VERSION 5.8 ;
BUSBITCHARS "[]" ;
DIVIDERCHAR "/" ;
UNITS
    DATABASE MICRONS 1000 ;
END UNITS

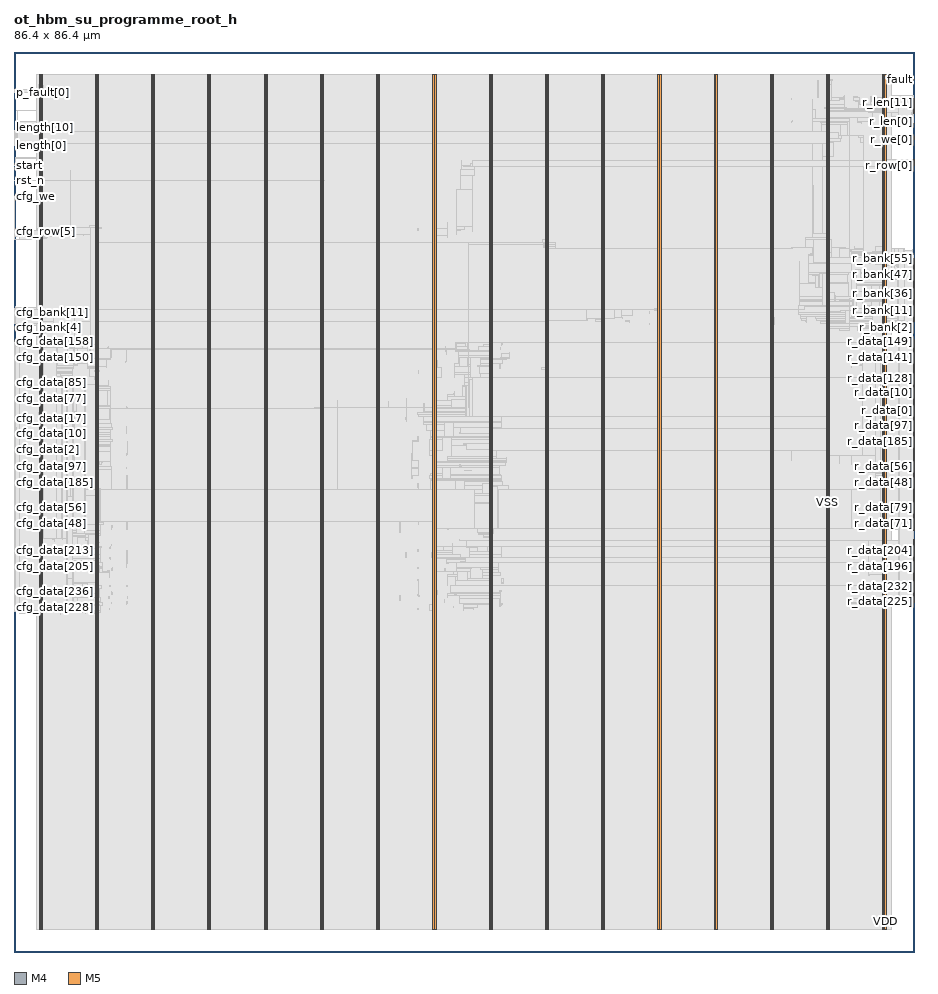
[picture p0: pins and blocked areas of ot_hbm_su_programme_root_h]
MACRO ot_hbm_su_programme_root_h
  FOREIGN ot_hbm_su_programme_root_h 0 0 ;
  CLASS BLOCK ;
  SIZE 86.4 BY 86.4 ;
  PIN cfg_bank[0]
    DIRECTION INPUT ;
    USE SIGNAL ;
    PORT
      LAYER M4 ;
        RECT  0 60.336 0.084 60.36 ;
    END
  END cfg_bank[0]
  PIN cfg_bank[10]
    DIRECTION INPUT ;
    USE SIGNAL ;
    PORT
      LAYER M4 ;
        RECT  0 61.296 0.084 61.32 ;
    END
  END cfg_bank[10]
  PIN cfg_bank[11]
    DIRECTION INPUT ;
    USE SIGNAL ;
    PORT
      LAYER M4 ;
        RECT  0 61.392 0.084 61.416 ;
    END
  END cfg_bank[11]
  PIN cfg_bank[12]
    DIRECTION INPUT ;
    USE SIGNAL ;
    PORT
      LAYER M4 ;
        RECT  0 61.488 0.084 61.512 ;
    END
  END cfg_bank[12]
  PIN cfg_bank[13]
    DIRECTION INPUT ;
    USE SIGNAL ;
    PORT
      LAYER M4 ;
        RECT  0 61.584 0.084 61.608 ;
    END
  END cfg_bank[13]
  PIN cfg_bank[14]
    DIRECTION INPUT ;
    USE SIGNAL ;
    PORT
      LAYER M4 ;
        RECT  0 61.68 0.084 61.704 ;
    END
  END cfg_bank[14]
  PIN cfg_bank[15]
    DIRECTION INPUT ;
    USE SIGNAL ;
    PORT
      LAYER M4 ;
        RECT  0 61.776 0.084 61.8 ;
    END
  END cfg_bank[15]
  PIN cfg_bank[1]
    DIRECTION INPUT ;
    USE SIGNAL ;
    PORT
      LAYER M4 ;
        RECT  0 60.432 0.084 60.456 ;
    END
  END cfg_bank[1]
  PIN cfg_bank[2]
    DIRECTION INPUT ;
    USE SIGNAL ;
    PORT
      LAYER M4 ;
        RECT  0 60.528 0.084 60.552 ;
    END
  END cfg_bank[2]
  PIN cfg_bank[3]
    DIRECTION INPUT ;
    USE SIGNAL ;
    PORT
      LAYER M4 ;
        RECT  0 60.624 0.084 60.648 ;
    END
  END cfg_bank[3]
  PIN cfg_bank[4]
    DIRECTION INPUT ;
    USE SIGNAL ;
    PORT
      LAYER M4 ;
        RECT  0 60.72 0.084 60.744 ;
    END
  END cfg_bank[4]
  PIN cfg_bank[5]
    DIRECTION INPUT ;
    USE SIGNAL ;
    PORT
      LAYER M4 ;
        RECT  0 60.816 0.084 60.84 ;
    END
  END cfg_bank[5]
  PIN cfg_bank[6]
    DIRECTION INPUT ;
    USE SIGNAL ;
    PORT
      LAYER M4 ;
        RECT  0 60.912 0.084 60.936 ;
    END
  END cfg_bank[6]
  PIN cfg_bank[7]
    DIRECTION INPUT ;
    USE SIGNAL ;
    PORT
      LAYER M4 ;
        RECT  0 61.008 0.084 61.032 ;
    END
  END cfg_bank[7]
  PIN cfg_bank[8]
    DIRECTION INPUT ;
    USE SIGNAL ;
    PORT
      LAYER M4 ;
        RECT  0 61.104 0.084 61.128 ;
    END
  END cfg_bank[8]
  PIN cfg_bank[9]
    DIRECTION INPUT ;
    USE SIGNAL ;
    PORT
      LAYER M4 ;
        RECT  0 61.2 0.084 61.224 ;
    END
  END cfg_bank[9]
  PIN cfg_data[0]
    DIRECTION INPUT ;
    USE SIGNAL ;
    PORT
      LAYER M4 ;
        RECT  0 48.816 0.084 48.84 ;
    END
  END cfg_data[0]
  PIN cfg_data[100]
    DIRECTION INPUT ;
    USE SIGNAL ;
    PORT
      LAYER M4 ;
        RECT  0 46.128 0.084 46.152 ;
    END
  END cfg_data[100]
  PIN cfg_data[101]
    DIRECTION INPUT ;
    USE SIGNAL ;
    PORT
      LAYER M4 ;
        RECT  0 46.224 0.084 46.248 ;
    END
  END cfg_data[101]
  PIN cfg_data[102]
    DIRECTION INPUT ;
    USE SIGNAL ;
    PORT
      LAYER M4 ;
        RECT  0 46.32 0.084 46.344 ;
    END
  END cfg_data[102]
  PIN cfg_data[103]
    DIRECTION INPUT ;
    USE SIGNAL ;
    PORT
      LAYER M4 ;
        RECT  0 46.416 0.084 46.44 ;
    END
  END cfg_data[103]
  PIN cfg_data[104]
    DIRECTION INPUT ;
    USE SIGNAL ;
    PORT
      LAYER M4 ;
        RECT  0 46.512 0.084 46.536 ;
    END
  END cfg_data[104]
  PIN cfg_data[105]
    DIRECTION INPUT ;
    USE SIGNAL ;
    PORT
      LAYER M4 ;
        RECT  0 46.608 0.084 46.632 ;
    END
  END cfg_data[105]
  PIN cfg_data[106]
    DIRECTION INPUT ;
    USE SIGNAL ;
    PORT
      LAYER M4 ;
        RECT  0 46.704 0.084 46.728 ;
    END
  END cfg_data[106]
  PIN cfg_data[107]
    DIRECTION INPUT ;
    USE SIGNAL ;
    PORT
      LAYER M4 ;
        RECT  0 46.8 0.084 46.824 ;
    END
  END cfg_data[107]
  PIN cfg_data[108]
    DIRECTION INPUT ;
    USE SIGNAL ;
    PORT
      LAYER M4 ;
        RECT  0 46.896 0.084 46.92 ;
    END
  END cfg_data[108]
  PIN cfg_data[109]
    DIRECTION INPUT ;
    USE SIGNAL ;
    PORT
      LAYER M4 ;
        RECT  0 46.992 0.084 47.016 ;
    END
  END cfg_data[109]
  PIN cfg_data[10]
    DIRECTION INPUT ;
    USE SIGNAL ;
    PORT
      LAYER M4 ;
        RECT  0 49.776 0.084 49.8 ;
    END
  END cfg_data[10]
  PIN cfg_data[110]
    DIRECTION INPUT ;
    USE SIGNAL ;
    PORT
      LAYER M4 ;
        RECT  0 47.088 0.084 47.112 ;
    END
  END cfg_data[110]
  PIN cfg_data[111]
    DIRECTION INPUT ;
    USE SIGNAL ;
    PORT
      LAYER M4 ;
        RECT  0 47.184 0.084 47.208 ;
    END
  END cfg_data[111]
  PIN cfg_data[112]
    DIRECTION INPUT ;
    USE SIGNAL ;
    PORT
      LAYER M4 ;
        RECT  0 47.28 0.084 47.304 ;
    END
  END cfg_data[112]
  PIN cfg_data[113]
    DIRECTION INPUT ;
    USE SIGNAL ;
    PORT
      LAYER M4 ;
        RECT  0 47.376 0.084 47.4 ;
    END
  END cfg_data[113]
  PIN cfg_data[114]
    DIRECTION INPUT ;
    USE SIGNAL ;
    PORT
      LAYER M4 ;
        RECT  0 47.472 0.084 47.496 ;
    END
  END cfg_data[114]
  PIN cfg_data[115]
    DIRECTION INPUT ;
    USE SIGNAL ;
    PORT
      LAYER M4 ;
        RECT  0 47.568 0.084 47.592 ;
    END
  END cfg_data[115]
  PIN cfg_data[116]
    DIRECTION INPUT ;
    USE SIGNAL ;
    PORT
      LAYER M4 ;
        RECT  0 47.664 0.084 47.688 ;
    END
  END cfg_data[116]
  PIN cfg_data[117]
    DIRECTION INPUT ;
    USE SIGNAL ;
    PORT
      LAYER M4 ;
        RECT  0 47.76 0.084 47.784 ;
    END
  END cfg_data[117]
  PIN cfg_data[118]
    DIRECTION INPUT ;
    USE SIGNAL ;
    PORT
      LAYER M4 ;
        RECT  0 47.856 0.084 47.88 ;
    END
  END cfg_data[118]
  PIN cfg_data[119]
    DIRECTION INPUT ;
    USE SIGNAL ;
    PORT
      LAYER M4 ;
        RECT  0 47.952 0.084 47.976 ;
    END
  END cfg_data[119]
  PIN cfg_data[11]
    DIRECTION INPUT ;
    USE SIGNAL ;
    PORT
      LAYER M4 ;
        RECT  0 49.872 0.084 49.896 ;
    END
  END cfg_data[11]
  PIN cfg_data[120]
    DIRECTION INPUT ;
    USE SIGNAL ;
    PORT
      LAYER M4 ;
        RECT  0 48.048 0.084 48.072 ;
    END
  END cfg_data[120]
  PIN cfg_data[121]
    DIRECTION INPUT ;
    USE SIGNAL ;
    PORT
      LAYER M4 ;
        RECT  0 48.144 0.084 48.168 ;
    END
  END cfg_data[121]
  PIN cfg_data[122]
    DIRECTION INPUT ;
    USE SIGNAL ;
    PORT
      LAYER M4 ;
        RECT  0 48.24 0.084 48.264 ;
    END
  END cfg_data[122]
  PIN cfg_data[123]
    DIRECTION INPUT ;
    USE SIGNAL ;
    PORT
      LAYER M4 ;
        RECT  0 48.336 0.084 48.36 ;
    END
  END cfg_data[123]
  PIN cfg_data[124]
    DIRECTION INPUT ;
    USE SIGNAL ;
    PORT
      LAYER M4 ;
        RECT  0 48.432 0.084 48.456 ;
    END
  END cfg_data[124]
  PIN cfg_data[125]
    DIRECTION INPUT ;
    USE SIGNAL ;
    PORT
      LAYER M4 ;
        RECT  0 48.528 0.084 48.552 ;
    END
  END cfg_data[125]
  PIN cfg_data[126]
    DIRECTION INPUT ;
    USE SIGNAL ;
    PORT
      LAYER M4 ;
        RECT  0 48.624 0.084 48.648 ;
    END
  END cfg_data[126]
  PIN cfg_data[127]
    DIRECTION INPUT ;
    USE SIGNAL ;
    PORT
      LAYER M4 ;
        RECT  0 48.72 0.084 48.744 ;
    END
  END cfg_data[127]
  PIN cfg_data[128]
    DIRECTION INPUT ;
    USE SIGNAL ;
    PORT
      LAYER M4 ;
        RECT  0 54.96 0.084 54.984 ;
    END
  END cfg_data[128]
  PIN cfg_data[129]
    DIRECTION INPUT ;
    USE SIGNAL ;
    PORT
      LAYER M4 ;
        RECT  0 55.056 0.084 55.08 ;
    END
  END cfg_data[129]
  PIN cfg_data[12]
    DIRECTION INPUT ;
    USE SIGNAL ;
    PORT
      LAYER M4 ;
        RECT  0 49.968 0.084 49.992 ;
    END
  END cfg_data[12]
  PIN cfg_data[130]
    DIRECTION INPUT ;
    USE SIGNAL ;
    PORT
      LAYER M4 ;
        RECT  0 55.152 0.084 55.176 ;
    END
  END cfg_data[130]
  PIN cfg_data[131]
    DIRECTION INPUT ;
    USE SIGNAL ;
    PORT
      LAYER M4 ;
        RECT  0 55.248 0.084 55.272 ;
    END
  END cfg_data[131]
  PIN cfg_data[132]
    DIRECTION INPUT ;
    USE SIGNAL ;
    PORT
      LAYER M4 ;
        RECT  0 55.344 0.084 55.368 ;
    END
  END cfg_data[132]
  PIN cfg_data[133]
    DIRECTION INPUT ;
    USE SIGNAL ;
    PORT
      LAYER M4 ;
        RECT  0 55.44 0.084 55.464 ;
    END
  END cfg_data[133]
  PIN cfg_data[134]
    DIRECTION INPUT ;
    USE SIGNAL ;
    PORT
      LAYER M4 ;
        RECT  0 55.536 0.084 55.56 ;
    END
  END cfg_data[134]
  PIN cfg_data[135]
    DIRECTION INPUT ;
    USE SIGNAL ;
    PORT
      LAYER M4 ;
        RECT  0 55.632 0.084 55.656 ;
    END
  END cfg_data[135]
  PIN cfg_data[136]
    DIRECTION INPUT ;
    USE SIGNAL ;
    PORT
      LAYER M4 ;
        RECT  0 55.728 0.084 55.752 ;
    END
  END cfg_data[136]
  PIN cfg_data[137]
    DIRECTION INPUT ;
    USE SIGNAL ;
    PORT
      LAYER M4 ;
        RECT  0 55.824 0.084 55.848 ;
    END
  END cfg_data[137]
  PIN cfg_data[138]
    DIRECTION INPUT ;
    USE SIGNAL ;
    PORT
      LAYER M4 ;
        RECT  0 55.92 0.084 55.944 ;
    END
  END cfg_data[138]
  PIN cfg_data[139]
    DIRECTION INPUT ;
    USE SIGNAL ;
    PORT
      LAYER M4 ;
        RECT  0 56.016 0.084 56.04 ;
    END
  END cfg_data[139]
  PIN cfg_data[13]
    DIRECTION INPUT ;
    USE SIGNAL ;
    PORT
      LAYER M4 ;
        RECT  0 50.064 0.084 50.088 ;
    END
  END cfg_data[13]
  PIN cfg_data[140]
    DIRECTION INPUT ;
    USE SIGNAL ;
    PORT
      LAYER M4 ;
        RECT  0 56.112 0.084 56.136 ;
    END
  END cfg_data[140]
  PIN cfg_data[141]
    DIRECTION INPUT ;
    USE SIGNAL ;
    PORT
      LAYER M4 ;
        RECT  0 56.208 0.084 56.232 ;
    END
  END cfg_data[141]
  PIN cfg_data[142]
    DIRECTION INPUT ;
    USE SIGNAL ;
    PORT
      LAYER M4 ;
        RECT  0 56.304 0.084 56.328 ;
    END
  END cfg_data[142]
  PIN cfg_data[143]
    DIRECTION INPUT ;
    USE SIGNAL ;
    PORT
      LAYER M4 ;
        RECT  0 56.4 0.084 56.424 ;
    END
  END cfg_data[143]
  PIN cfg_data[144]
    DIRECTION INPUT ;
    USE SIGNAL ;
    PORT
      LAYER M4 ;
        RECT  0 56.496 0.084 56.52 ;
    END
  END cfg_data[144]
  PIN cfg_data[145]
    DIRECTION INPUT ;
    USE SIGNAL ;
    PORT
      LAYER M4 ;
        RECT  0 56.592 0.084 56.616 ;
    END
  END cfg_data[145]
  PIN cfg_data[146]
    DIRECTION INPUT ;
    USE SIGNAL ;
    PORT
      LAYER M4 ;
        RECT  0 56.688 0.084 56.712 ;
    END
  END cfg_data[146]
  PIN cfg_data[147]
    DIRECTION INPUT ;
    USE SIGNAL ;
    PORT
      LAYER M4 ;
        RECT  0 56.784 0.084 56.808 ;
    END
  END cfg_data[147]
  PIN cfg_data[148]
    DIRECTION INPUT ;
    USE SIGNAL ;
    PORT
      LAYER M4 ;
        RECT  0 56.88 0.084 56.904 ;
    END
  END cfg_data[148]
  PIN cfg_data[149]
    DIRECTION INPUT ;
    USE SIGNAL ;
    PORT
      LAYER M4 ;
        RECT  0 56.976 0.084 57 ;
    END
  END cfg_data[149]
  PIN cfg_data[14]
    DIRECTION INPUT ;
    USE SIGNAL ;
    PORT
      LAYER M4 ;
        RECT  0 50.16 0.084 50.184 ;
    END
  END cfg_data[14]
  PIN cfg_data[150]
    DIRECTION INPUT ;
    USE SIGNAL ;
    PORT
      LAYER M4 ;
        RECT  0 57.072 0.084 57.096 ;
    END
  END cfg_data[150]
  PIN cfg_data[151]
    DIRECTION INPUT ;
    USE SIGNAL ;
    PORT
      LAYER M4 ;
        RECT  0 57.168 0.084 57.192 ;
    END
  END cfg_data[151]
  PIN cfg_data[152]
    DIRECTION INPUT ;
    USE SIGNAL ;
    PORT
      LAYER M4 ;
        RECT  0 57.264 0.084 57.288 ;
    END
  END cfg_data[152]
  PIN cfg_data[153]
    DIRECTION INPUT ;
    USE SIGNAL ;
    PORT
      LAYER M4 ;
        RECT  0 57.36 0.084 57.384 ;
    END
  END cfg_data[153]
  PIN cfg_data[154]
    DIRECTION INPUT ;
    USE SIGNAL ;
    PORT
      LAYER M4 ;
        RECT  0 57.456 0.084 57.48 ;
    END
  END cfg_data[154]
  PIN cfg_data[155]
    DIRECTION INPUT ;
    USE SIGNAL ;
    PORT
      LAYER M4 ;
        RECT  0 57.552 0.084 57.576 ;
    END
  END cfg_data[155]
  PIN cfg_data[156]
    DIRECTION INPUT ;
    USE SIGNAL ;
    PORT
      LAYER M4 ;
        RECT  0 57.648 0.084 57.672 ;
    END
  END cfg_data[156]
  PIN cfg_data[157]
    DIRECTION INPUT ;
    USE SIGNAL ;
    PORT
      LAYER M4 ;
        RECT  0 57.744 0.084 57.768 ;
    END
  END cfg_data[157]
  PIN cfg_data[158]
    DIRECTION INPUT ;
    USE SIGNAL ;
    PORT
      LAYER M4 ;
        RECT  0 57.84 0.084 57.864 ;
    END
  END cfg_data[158]
  PIN cfg_data[159]
    DIRECTION INPUT ;
    USE SIGNAL ;
    PORT
      LAYER M4 ;
        RECT  0 57.936 0.084 57.96 ;
    END
  END cfg_data[159]
  PIN cfg_data[15]
    DIRECTION INPUT ;
    USE SIGNAL ;
    PORT
      LAYER M4 ;
        RECT  0 50.256 0.084 50.28 ;
    END
  END cfg_data[15]
  PIN cfg_data[160]
    DIRECTION INPUT ;
    USE SIGNAL ;
    PORT
      LAYER M4 ;
        RECT  0 42.672 0.084 42.696 ;
    END
  END cfg_data[160]
  PIN cfg_data[161]
    DIRECTION INPUT ;
    USE SIGNAL ;
    PORT
      LAYER M4 ;
        RECT  0 42.768 0.084 42.792 ;
    END
  END cfg_data[161]
  PIN cfg_data[162]
    DIRECTION INPUT ;
    USE SIGNAL ;
    PORT
      LAYER M4 ;
        RECT  0 42.864 0.084 42.888 ;
    END
  END cfg_data[162]
  PIN cfg_data[163]
    DIRECTION INPUT ;
    USE SIGNAL ;
    PORT
      LAYER M4 ;
        RECT  0 42.96 0.084 42.984 ;
    END
  END cfg_data[163]
  PIN cfg_data[164]
    DIRECTION INPUT ;
    USE SIGNAL ;
    PORT
      LAYER M4 ;
        RECT  0 43.056 0.084 43.08 ;
    END
  END cfg_data[164]
  PIN cfg_data[165]
    DIRECTION INPUT ;
    USE SIGNAL ;
    PORT
      LAYER M4 ;
        RECT  0 43.152 0.084 43.176 ;
    END
  END cfg_data[165]
  PIN cfg_data[166]
    DIRECTION INPUT ;
    USE SIGNAL ;
    PORT
      LAYER M4 ;
        RECT  0 43.248 0.084 43.272 ;
    END
  END cfg_data[166]
  PIN cfg_data[167]
    DIRECTION INPUT ;
    USE SIGNAL ;
    PORT
      LAYER M4 ;
        RECT  0 43.344 0.084 43.368 ;
    END
  END cfg_data[167]
  PIN cfg_data[168]
    DIRECTION INPUT ;
    USE SIGNAL ;
    PORT
      LAYER M4 ;
        RECT  0 43.44 0.084 43.464 ;
    END
  END cfg_data[168]
  PIN cfg_data[169]
    DIRECTION INPUT ;
    USE SIGNAL ;
    PORT
      LAYER M4 ;
        RECT  0 43.536 0.084 43.56 ;
    END
  END cfg_data[169]
  PIN cfg_data[16]
    DIRECTION INPUT ;
    USE SIGNAL ;
    PORT
      LAYER M4 ;
        RECT  0 50.352 0.084 50.376 ;
    END
  END cfg_data[16]
  PIN cfg_data[170]
    DIRECTION INPUT ;
    USE SIGNAL ;
    PORT
      LAYER M4 ;
        RECT  0 43.632 0.084 43.656 ;
    END
  END cfg_data[170]
  PIN cfg_data[171]
    DIRECTION INPUT ;
    USE SIGNAL ;
    PORT
      LAYER M4 ;
        RECT  0 43.728 0.084 43.752 ;
    END
  END cfg_data[171]
  PIN cfg_data[172]
    DIRECTION INPUT ;
    USE SIGNAL ;
    PORT
      LAYER M4 ;
        RECT  0 43.824 0.084 43.848 ;
    END
  END cfg_data[172]
  PIN cfg_data[173]
    DIRECTION INPUT ;
    USE SIGNAL ;
    PORT
      LAYER M4 ;
        RECT  0 43.92 0.084 43.944 ;
    END
  END cfg_data[173]
  PIN cfg_data[174]
    DIRECTION INPUT ;
    USE SIGNAL ;
    PORT
      LAYER M4 ;
        RECT  0 44.016 0.084 44.04 ;
    END
  END cfg_data[174]
  PIN cfg_data[175]
    DIRECTION INPUT ;
    USE SIGNAL ;
    PORT
      LAYER M4 ;
        RECT  0 44.112 0.084 44.136 ;
    END
  END cfg_data[175]
  PIN cfg_data[176]
    DIRECTION INPUT ;
    USE SIGNAL ;
    PORT
      LAYER M4 ;
        RECT  0 44.208 0.084 44.232 ;
    END
  END cfg_data[176]
  PIN cfg_data[177]
    DIRECTION INPUT ;
    USE SIGNAL ;
    PORT
      LAYER M4 ;
        RECT  0 44.304 0.084 44.328 ;
    END
  END cfg_data[177]
  PIN cfg_data[178]
    DIRECTION INPUT ;
    USE SIGNAL ;
    PORT
      LAYER M4 ;
        RECT  0 44.4 0.084 44.424 ;
    END
  END cfg_data[178]
  PIN cfg_data[179]
    DIRECTION INPUT ;
    USE SIGNAL ;
    PORT
      LAYER M4 ;
        RECT  0 44.496 0.084 44.52 ;
    END
  END cfg_data[179]
  PIN cfg_data[17]
    DIRECTION INPUT ;
    USE SIGNAL ;
    PORT
      LAYER M4 ;
        RECT  0 50.448 0.084 50.472 ;
    END
  END cfg_data[17]
  PIN cfg_data[180]
    DIRECTION INPUT ;
    USE SIGNAL ;
    PORT
      LAYER M4 ;
        RECT  0 44.592 0.084 44.616 ;
    END
  END cfg_data[180]
  PIN cfg_data[181]
    DIRECTION INPUT ;
    USE SIGNAL ;
    PORT
      LAYER M4 ;
        RECT  0 44.688 0.084 44.712 ;
    END
  END cfg_data[181]
  PIN cfg_data[182]
    DIRECTION INPUT ;
    USE SIGNAL ;
    PORT
      LAYER M4 ;
        RECT  0 44.784 0.084 44.808 ;
    END
  END cfg_data[182]
  PIN cfg_data[183]
    DIRECTION INPUT ;
    USE SIGNAL ;
    PORT
      LAYER M4 ;
        RECT  0 44.88 0.084 44.904 ;
    END
  END cfg_data[183]
  PIN cfg_data[184]
    DIRECTION INPUT ;
    USE SIGNAL ;
    PORT
      LAYER M4 ;
        RECT  0 44.976 0.084 45 ;
    END
  END cfg_data[184]
  PIN cfg_data[185]
    DIRECTION INPUT ;
    USE SIGNAL ;
    PORT
      LAYER M4 ;
        RECT  0 45.072 0.084 45.096 ;
    END
  END cfg_data[185]
  PIN cfg_data[186]
    DIRECTION INPUT ;
    USE SIGNAL ;
    PORT
      LAYER M4 ;
        RECT  0 45.168 0.084 45.192 ;
    END
  END cfg_data[186]
  PIN cfg_data[187]
    DIRECTION INPUT ;
    USE SIGNAL ;
    PORT
      LAYER M4 ;
        RECT  0 45.264 0.084 45.288 ;
    END
  END cfg_data[187]
  PIN cfg_data[188]
    DIRECTION INPUT ;
    USE SIGNAL ;
    PORT
      LAYER M4 ;
        RECT  0 45.36 0.084 45.384 ;
    END
  END cfg_data[188]
  PIN cfg_data[189]
    DIRECTION INPUT ;
    USE SIGNAL ;
    PORT
      LAYER M4 ;
        RECT  0 45.456 0.084 45.48 ;
    END
  END cfg_data[189]
  PIN cfg_data[18]
    DIRECTION INPUT ;
    USE SIGNAL ;
    PORT
      LAYER M4 ;
        RECT  0 50.544 0.084 50.568 ;
    END
  END cfg_data[18]
  PIN cfg_data[190]
    DIRECTION INPUT ;
    USE SIGNAL ;
    PORT
      LAYER M4 ;
        RECT  0 45.552 0.084 45.576 ;
    END
  END cfg_data[190]
  PIN cfg_data[191]
    DIRECTION INPUT ;
    USE SIGNAL ;
    PORT
      LAYER M4 ;
        RECT  0 45.648 0.084 45.672 ;
    END
  END cfg_data[191]
  PIN cfg_data[192]
    DIRECTION INPUT ;
    USE SIGNAL ;
    PORT
      LAYER M4 ;
        RECT  0 35.76 0.084 35.784 ;
    END
  END cfg_data[192]
  PIN cfg_data[193]
    DIRECTION INPUT ;
    USE SIGNAL ;
    PORT
      LAYER M4 ;
        RECT  0 35.856 0.084 35.88 ;
    END
  END cfg_data[193]
  PIN cfg_data[194]
    DIRECTION INPUT ;
    USE SIGNAL ;
    PORT
      LAYER M4 ;
        RECT  0 35.952 0.084 35.976 ;
    END
  END cfg_data[194]
  PIN cfg_data[195]
    DIRECTION INPUT ;
    USE SIGNAL ;
    PORT
      LAYER M4 ;
        RECT  0 36.048 0.084 36.072 ;
    END
  END cfg_data[195]
  PIN cfg_data[196]
    DIRECTION INPUT ;
    USE SIGNAL ;
    PORT
      LAYER M4 ;
        RECT  0 36.144 0.084 36.168 ;
    END
  END cfg_data[196]
  PIN cfg_data[197]
    DIRECTION INPUT ;
    USE SIGNAL ;
    PORT
      LAYER M4 ;
        RECT  0 36.24 0.084 36.264 ;
    END
  END cfg_data[197]
  PIN cfg_data[198]
    DIRECTION INPUT ;
    USE SIGNAL ;
    PORT
      LAYER M4 ;
        RECT  0 36.336 0.084 36.36 ;
    END
  END cfg_data[198]
  PIN cfg_data[199]
    DIRECTION INPUT ;
    USE SIGNAL ;
    PORT
      LAYER M4 ;
        RECT  0 36.432 0.084 36.456 ;
    END
  END cfg_data[199]
  PIN cfg_data[19]
    DIRECTION INPUT ;
    USE SIGNAL ;
    PORT
      LAYER M4 ;
        RECT  0 50.64 0.084 50.664 ;
    END
  END cfg_data[19]
  PIN cfg_data[1]
    DIRECTION INPUT ;
    USE SIGNAL ;
    PORT
      LAYER M4 ;
        RECT  0 48.912 0.084 48.936 ;
    END
  END cfg_data[1]
  PIN cfg_data[200]
    DIRECTION INPUT ;
    USE SIGNAL ;
    PORT
      LAYER M4 ;
        RECT  0 36.528 0.084 36.552 ;
    END
  END cfg_data[200]
  PIN cfg_data[201]
    DIRECTION INPUT ;
    USE SIGNAL ;
    PORT
      LAYER M4 ;
        RECT  0 36.624 0.084 36.648 ;
    END
  END cfg_data[201]
  PIN cfg_data[202]
    DIRECTION INPUT ;
    USE SIGNAL ;
    PORT
      LAYER M4 ;
        RECT  0 36.72 0.084 36.744 ;
    END
  END cfg_data[202]
  PIN cfg_data[203]
    DIRECTION INPUT ;
    USE SIGNAL ;
    PORT
      LAYER M4 ;
        RECT  0 36.816 0.084 36.84 ;
    END
  END cfg_data[203]
  PIN cfg_data[204]
    DIRECTION INPUT ;
    USE SIGNAL ;
    PORT
      LAYER M4 ;
        RECT  0 36.912 0.084 36.936 ;
    END
  END cfg_data[204]
  PIN cfg_data[205]
    DIRECTION INPUT ;
    USE SIGNAL ;
    PORT
      LAYER M4 ;
        RECT  0 37.008 0.084 37.032 ;
    END
  END cfg_data[205]
  PIN cfg_data[206]
    DIRECTION INPUT ;
    USE SIGNAL ;
    PORT
      LAYER M4 ;
        RECT  0 37.104 0.084 37.128 ;
    END
  END cfg_data[206]
  PIN cfg_data[207]
    DIRECTION INPUT ;
    USE SIGNAL ;
    PORT
      LAYER M4 ;
        RECT  0 37.2 0.084 37.224 ;
    END
  END cfg_data[207]
  PIN cfg_data[208]
    DIRECTION INPUT ;
    USE SIGNAL ;
    PORT
      LAYER M4 ;
        RECT  0 37.296 0.084 37.32 ;
    END
  END cfg_data[208]
  PIN cfg_data[209]
    DIRECTION INPUT ;
    USE SIGNAL ;
    PORT
      LAYER M4 ;
        RECT  0 37.392 0.084 37.416 ;
    END
  END cfg_data[209]
  PIN cfg_data[20]
    DIRECTION INPUT ;
    USE SIGNAL ;
    PORT
      LAYER M4 ;
        RECT  0 50.736 0.084 50.76 ;
    END
  END cfg_data[20]
  PIN cfg_data[210]
    DIRECTION INPUT ;
    USE SIGNAL ;
    PORT
      LAYER M4 ;
        RECT  0 37.488 0.084 37.512 ;
    END
  END cfg_data[210]
  PIN cfg_data[211]
    DIRECTION INPUT ;
    USE SIGNAL ;
    PORT
      LAYER M4 ;
        RECT  0 37.584 0.084 37.608 ;
    END
  END cfg_data[211]
  PIN cfg_data[212]
    DIRECTION INPUT ;
    USE SIGNAL ;
    PORT
      LAYER M4 ;
        RECT  0 37.68 0.084 37.704 ;
    END
  END cfg_data[212]
  PIN cfg_data[213]
    DIRECTION INPUT ;
    USE SIGNAL ;
    PORT
      LAYER M4 ;
        RECT  0 37.776 0.084 37.8 ;
    END
  END cfg_data[213]
  PIN cfg_data[214]
    DIRECTION INPUT ;
    USE SIGNAL ;
    PORT
      LAYER M4 ;
        RECT  0 37.872 0.084 37.896 ;
    END
  END cfg_data[214]
  PIN cfg_data[215]
    DIRECTION INPUT ;
    USE SIGNAL ;
    PORT
      LAYER M4 ;
        RECT  0 37.968 0.084 37.992 ;
    END
  END cfg_data[215]
  PIN cfg_data[216]
    DIRECTION INPUT ;
    USE SIGNAL ;
    PORT
      LAYER M4 ;
        RECT  0 38.064 0.084 38.088 ;
    END
  END cfg_data[216]
  PIN cfg_data[217]
    DIRECTION INPUT ;
    USE SIGNAL ;
    PORT
      LAYER M4 ;
        RECT  0 38.16 0.084 38.184 ;
    END
  END cfg_data[217]
  PIN cfg_data[218]
    DIRECTION INPUT ;
    USE SIGNAL ;
    PORT
      LAYER M4 ;
        RECT  0 38.256 0.084 38.28 ;
    END
  END cfg_data[218]
  PIN cfg_data[219]
    DIRECTION INPUT ;
    USE SIGNAL ;
    PORT
      LAYER M4 ;
        RECT  0 38.352 0.084 38.376 ;
    END
  END cfg_data[219]
  PIN cfg_data[21]
    DIRECTION INPUT ;
    USE SIGNAL ;
    PORT
      LAYER M4 ;
        RECT  0 50.832 0.084 50.856 ;
    END
  END cfg_data[21]
  PIN cfg_data[220]
    DIRECTION INPUT ;
    USE SIGNAL ;
    PORT
      LAYER M4 ;
        RECT  0 38.448 0.084 38.472 ;
    END
  END cfg_data[220]
  PIN cfg_data[221]
    DIRECTION INPUT ;
    USE SIGNAL ;
    PORT
      LAYER M4 ;
        RECT  0 38.544 0.084 38.568 ;
    END
  END cfg_data[221]
  PIN cfg_data[222]
    DIRECTION INPUT ;
    USE SIGNAL ;
    PORT
      LAYER M4 ;
        RECT  0 38.64 0.084 38.664 ;
    END
  END cfg_data[222]
  PIN cfg_data[223]
    DIRECTION INPUT ;
    USE SIGNAL ;
    PORT
      LAYER M4 ;
        RECT  0 38.736 0.084 38.76 ;
    END
  END cfg_data[223]
  PIN cfg_data[224]
    DIRECTION INPUT ;
    USE SIGNAL ;
    PORT
      LAYER M4 ;
        RECT  0 32.688 0.084 32.712 ;
    END
  END cfg_data[224]
  PIN cfg_data[225]
    DIRECTION INPUT ;
    USE SIGNAL ;
    PORT
      LAYER M4 ;
        RECT  0 32.784 0.084 32.808 ;
    END
  END cfg_data[225]
  PIN cfg_data[226]
    DIRECTION INPUT ;
    USE SIGNAL ;
    PORT
      LAYER M4 ;
        RECT  0 32.88 0.084 32.904 ;
    END
  END cfg_data[226]
  PIN cfg_data[227]
    DIRECTION INPUT ;
    USE SIGNAL ;
    PORT
      LAYER M4 ;
        RECT  0 32.976 0.084 33 ;
    END
  END cfg_data[227]
  PIN cfg_data[228]
    DIRECTION INPUT ;
    USE SIGNAL ;
    PORT
      LAYER M4 ;
        RECT  0 33.072 0.084 33.096 ;
    END
  END cfg_data[228]
  PIN cfg_data[229]
    DIRECTION INPUT ;
    USE SIGNAL ;
    PORT
      LAYER M4 ;
        RECT  0 33.168 0.084 33.192 ;
    END
  END cfg_data[229]
  PIN cfg_data[22]
    DIRECTION INPUT ;
    USE SIGNAL ;
    PORT
      LAYER M4 ;
        RECT  0 50.928 0.084 50.952 ;
    END
  END cfg_data[22]
  PIN cfg_data[230]
    DIRECTION INPUT ;
    USE SIGNAL ;
    PORT
      LAYER M4 ;
        RECT  0 33.264 0.084 33.288 ;
    END
  END cfg_data[230]
  PIN cfg_data[231]
    DIRECTION INPUT ;
    USE SIGNAL ;
    PORT
      LAYER M4 ;
        RECT  0 33.36 0.084 33.384 ;
    END
  END cfg_data[231]
  PIN cfg_data[232]
    DIRECTION INPUT ;
    USE SIGNAL ;
    PORT
      LAYER M4 ;
        RECT  0 33.456 0.084 33.48 ;
    END
  END cfg_data[232]
  PIN cfg_data[233]
    DIRECTION INPUT ;
    USE SIGNAL ;
    PORT
      LAYER M4 ;
        RECT  0 33.552 0.084 33.576 ;
    END
  END cfg_data[233]
  PIN cfg_data[234]
    DIRECTION INPUT ;
    USE SIGNAL ;
    PORT
      LAYER M4 ;
        RECT  0 33.648 0.084 33.672 ;
    END
  END cfg_data[234]
  PIN cfg_data[235]
    DIRECTION INPUT ;
    USE SIGNAL ;
    PORT
      LAYER M4 ;
        RECT  0 33.744 0.084 33.768 ;
    END
  END cfg_data[235]
  PIN cfg_data[236]
    DIRECTION INPUT ;
    USE SIGNAL ;
    PORT
      LAYER M4 ;
        RECT  0 33.84 0.084 33.864 ;
    END
  END cfg_data[236]
  PIN cfg_data[237]
    DIRECTION INPUT ;
    USE SIGNAL ;
    PORT
      LAYER M4 ;
        RECT  0 33.936 0.084 33.96 ;
    END
  END cfg_data[237]
  PIN cfg_data[238]
    DIRECTION INPUT ;
    USE SIGNAL ;
    PORT
      LAYER M4 ;
        RECT  0 34.032 0.084 34.056 ;
    END
  END cfg_data[238]
  PIN cfg_data[239]
    DIRECTION INPUT ;
    USE SIGNAL ;
    PORT
      LAYER M4 ;
        RECT  0 34.128 0.084 34.152 ;
    END
  END cfg_data[239]
  PIN cfg_data[23]
    DIRECTION INPUT ;
    USE SIGNAL ;
    PORT
      LAYER M4 ;
        RECT  0 51.024 0.084 51.048 ;
    END
  END cfg_data[23]
  PIN cfg_data[240]
    DIRECTION INPUT ;
    USE SIGNAL ;
    PORT
      LAYER M4 ;
        RECT  0 34.224 0.084 34.248 ;
    END
  END cfg_data[240]
  PIN cfg_data[241]
    DIRECTION INPUT ;
    USE SIGNAL ;
    PORT
      LAYER M4 ;
        RECT  0 34.32 0.084 34.344 ;
    END
  END cfg_data[241]
  PIN cfg_data[242]
    DIRECTION INPUT ;
    USE SIGNAL ;
    PORT
      LAYER M4 ;
        RECT  0 34.416 0.084 34.44 ;
    END
  END cfg_data[242]
  PIN cfg_data[243]
    DIRECTION INPUT ;
    USE SIGNAL ;
    PORT
      LAYER M4 ;
        RECT  0 34.512 0.084 34.536 ;
    END
  END cfg_data[243]
  PIN cfg_data[244]
    DIRECTION INPUT ;
    USE SIGNAL ;
    PORT
      LAYER M4 ;
        RECT  0 34.608 0.084 34.632 ;
    END
  END cfg_data[244]
  PIN cfg_data[245]
    DIRECTION INPUT ;
    USE SIGNAL ;
    PORT
      LAYER M4 ;
        RECT  0 34.704 0.084 34.728 ;
    END
  END cfg_data[245]
  PIN cfg_data[246]
    DIRECTION INPUT ;
    USE SIGNAL ;
    PORT
      LAYER M4 ;
        RECT  0 34.8 0.084 34.824 ;
    END
  END cfg_data[246]
  PIN cfg_data[247]
    DIRECTION INPUT ;
    USE SIGNAL ;
    PORT
      LAYER M4 ;
        RECT  0 34.896 0.084 34.92 ;
    END
  END cfg_data[247]
  PIN cfg_data[248]
    DIRECTION INPUT ;
    USE SIGNAL ;
    PORT
      LAYER M4 ;
        RECT  0 34.992 0.084 35.016 ;
    END
  END cfg_data[248]
  PIN cfg_data[249]
    DIRECTION INPUT ;
    USE SIGNAL ;
    PORT
      LAYER M4 ;
        RECT  0 35.088 0.084 35.112 ;
    END
  END cfg_data[249]
  PIN cfg_data[24]
    DIRECTION INPUT ;
    USE SIGNAL ;
    PORT
      LAYER M4 ;
        RECT  0 51.12 0.084 51.144 ;
    END
  END cfg_data[24]
  PIN cfg_data[250]
    DIRECTION INPUT ;
    USE SIGNAL ;
    PORT
      LAYER M4 ;
        RECT  0 35.184 0.084 35.208 ;
    END
  END cfg_data[250]
  PIN cfg_data[251]
    DIRECTION INPUT ;
    USE SIGNAL ;
    PORT
      LAYER M4 ;
        RECT  0 35.28 0.084 35.304 ;
    END
  END cfg_data[251]
  PIN cfg_data[252]
    DIRECTION INPUT ;
    USE SIGNAL ;
    PORT
      LAYER M4 ;
        RECT  0 35.376 0.084 35.4 ;
    END
  END cfg_data[252]
  PIN cfg_data[253]
    DIRECTION INPUT ;
    USE SIGNAL ;
    PORT
      LAYER M4 ;
        RECT  0 35.472 0.084 35.496 ;
    END
  END cfg_data[253]
  PIN cfg_data[254]
    DIRECTION INPUT ;
    USE SIGNAL ;
    PORT
      LAYER M4 ;
        RECT  0 35.568 0.084 35.592 ;
    END
  END cfg_data[254]
  PIN cfg_data[255]
    DIRECTION INPUT ;
    USE SIGNAL ;
    PORT
      LAYER M4 ;
        RECT  0 35.664 0.084 35.688 ;
    END
  END cfg_data[255]
  PIN cfg_data[25]
    DIRECTION INPUT ;
    USE SIGNAL ;
    PORT
      LAYER M4 ;
        RECT  0 51.216 0.084 51.24 ;
    END
  END cfg_data[25]
  PIN cfg_data[26]
    DIRECTION INPUT ;
    USE SIGNAL ;
    PORT
      LAYER M4 ;
        RECT  0 51.312 0.084 51.336 ;
    END
  END cfg_data[26]
  PIN cfg_data[27]
    DIRECTION INPUT ;
    USE SIGNAL ;
    PORT
      LAYER M4 ;
        RECT  0 51.408 0.084 51.432 ;
    END
  END cfg_data[27]
  PIN cfg_data[28]
    DIRECTION INPUT ;
    USE SIGNAL ;
    PORT
      LAYER M4 ;
        RECT  0 51.504 0.084 51.528 ;
    END
  END cfg_data[28]
  PIN cfg_data[29]
    DIRECTION INPUT ;
    USE SIGNAL ;
    PORT
      LAYER M4 ;
        RECT  0 51.6 0.084 51.624 ;
    END
  END cfg_data[29]
  PIN cfg_data[2]
    DIRECTION INPUT ;
    USE SIGNAL ;
    PORT
      LAYER M4 ;
        RECT  0 49.008 0.084 49.032 ;
    END
  END cfg_data[2]
  PIN cfg_data[30]
    DIRECTION INPUT ;
    USE SIGNAL ;
    PORT
      LAYER M4 ;
        RECT  0 51.696 0.084 51.72 ;
    END
  END cfg_data[30]
  PIN cfg_data[31]
    DIRECTION INPUT ;
    USE SIGNAL ;
    PORT
      LAYER M4 ;
        RECT  0 51.792 0.084 51.816 ;
    END
  END cfg_data[31]
  PIN cfg_data[32]
    DIRECTION INPUT ;
    USE SIGNAL ;
    PORT
      LAYER M4 ;
        RECT  0 39.6 0.084 39.624 ;
    END
  END cfg_data[32]
  PIN cfg_data[33]
    DIRECTION INPUT ;
    USE SIGNAL ;
    PORT
      LAYER M4 ;
        RECT  0 39.696 0.084 39.72 ;
    END
  END cfg_data[33]
  PIN cfg_data[34]
    DIRECTION INPUT ;
    USE SIGNAL ;
    PORT
      LAYER M4 ;
        RECT  0 39.792 0.084 39.816 ;
    END
  END cfg_data[34]
  PIN cfg_data[35]
    DIRECTION INPUT ;
    USE SIGNAL ;
    PORT
      LAYER M4 ;
        RECT  0 39.888 0.084 39.912 ;
    END
  END cfg_data[35]
  PIN cfg_data[36]
    DIRECTION INPUT ;
    USE SIGNAL ;
    PORT
      LAYER M4 ;
        RECT  0 39.984 0.084 40.008 ;
    END
  END cfg_data[36]
  PIN cfg_data[37]
    DIRECTION INPUT ;
    USE SIGNAL ;
    PORT
      LAYER M4 ;
        RECT  0 40.08 0.084 40.104 ;
    END
  END cfg_data[37]
  PIN cfg_data[38]
    DIRECTION INPUT ;
    USE SIGNAL ;
    PORT
      LAYER M4 ;
        RECT  0 40.176 0.084 40.2 ;
    END
  END cfg_data[38]
  PIN cfg_data[39]
    DIRECTION INPUT ;
    USE SIGNAL ;
    PORT
      LAYER M4 ;
        RECT  0 40.272 0.084 40.296 ;
    END
  END cfg_data[39]
  PIN cfg_data[3]
    DIRECTION INPUT ;
    USE SIGNAL ;
    PORT
      LAYER M4 ;
        RECT  0 49.104 0.084 49.128 ;
    END
  END cfg_data[3]
  PIN cfg_data[40]
    DIRECTION INPUT ;
    USE SIGNAL ;
    PORT
      LAYER M4 ;
        RECT  0 40.368 0.084 40.392 ;
    END
  END cfg_data[40]
  PIN cfg_data[41]
    DIRECTION INPUT ;
    USE SIGNAL ;
    PORT
      LAYER M4 ;
        RECT  0 40.464 0.084 40.488 ;
    END
  END cfg_data[41]
  PIN cfg_data[42]
    DIRECTION INPUT ;
    USE SIGNAL ;
    PORT
      LAYER M4 ;
        RECT  0 40.56 0.084 40.584 ;
    END
  END cfg_data[42]
  PIN cfg_data[43]
    DIRECTION INPUT ;
    USE SIGNAL ;
    PORT
      LAYER M4 ;
        RECT  0 40.656 0.084 40.68 ;
    END
  END cfg_data[43]
  PIN cfg_data[44]
    DIRECTION INPUT ;
    USE SIGNAL ;
    PORT
      LAYER M4 ;
        RECT  0 40.752 0.084 40.776 ;
    END
  END cfg_data[44]
  PIN cfg_data[45]
    DIRECTION INPUT ;
    USE SIGNAL ;
    PORT
      LAYER M4 ;
        RECT  0 40.848 0.084 40.872 ;
    END
  END cfg_data[45]
  PIN cfg_data[46]
    DIRECTION INPUT ;
    USE SIGNAL ;
    PORT
      LAYER M4 ;
        RECT  0 40.944 0.084 40.968 ;
    END
  END cfg_data[46]
  PIN cfg_data[47]
    DIRECTION INPUT ;
    USE SIGNAL ;
    PORT
      LAYER M4 ;
        RECT  0 41.04 0.084 41.064 ;
    END
  END cfg_data[47]
  PIN cfg_data[48]
    DIRECTION INPUT ;
    USE SIGNAL ;
    PORT
      LAYER M4 ;
        RECT  0 41.136 0.084 41.16 ;
    END
  END cfg_data[48]
  PIN cfg_data[49]
    DIRECTION INPUT ;
    USE SIGNAL ;
    PORT
      LAYER M4 ;
        RECT  0 41.232 0.084 41.256 ;
    END
  END cfg_data[49]
  PIN cfg_data[4]
    DIRECTION INPUT ;
    USE SIGNAL ;
    PORT
      LAYER M4 ;
        RECT  0 49.2 0.084 49.224 ;
    END
  END cfg_data[4]
  PIN cfg_data[50]
    DIRECTION INPUT ;
    USE SIGNAL ;
    PORT
      LAYER M4 ;
        RECT  0 41.328 0.084 41.352 ;
    END
  END cfg_data[50]
  PIN cfg_data[51]
    DIRECTION INPUT ;
    USE SIGNAL ;
    PORT
      LAYER M4 ;
        RECT  0 41.424 0.084 41.448 ;
    END
  END cfg_data[51]
  PIN cfg_data[52]
    DIRECTION INPUT ;
    USE SIGNAL ;
    PORT
      LAYER M4 ;
        RECT  0 41.52 0.084 41.544 ;
    END
  END cfg_data[52]
  PIN cfg_data[53]
    DIRECTION INPUT ;
    USE SIGNAL ;
    PORT
      LAYER M4 ;
        RECT  0 41.616 0.084 41.64 ;
    END
  END cfg_data[53]
  PIN cfg_data[54]
    DIRECTION INPUT ;
    USE SIGNAL ;
    PORT
      LAYER M4 ;
        RECT  0 41.712 0.084 41.736 ;
    END
  END cfg_data[54]
  PIN cfg_data[55]
    DIRECTION INPUT ;
    USE SIGNAL ;
    PORT
      LAYER M4 ;
        RECT  0 41.808 0.084 41.832 ;
    END
  END cfg_data[55]
  PIN cfg_data[56]
    DIRECTION INPUT ;
    USE SIGNAL ;
    PORT
      LAYER M4 ;
        RECT  0 41.904 0.084 41.928 ;
    END
  END cfg_data[56]
  PIN cfg_data[57]
    DIRECTION INPUT ;
    USE SIGNAL ;
    PORT
      LAYER M4 ;
        RECT  0 42 0.084 42.024 ;
    END
  END cfg_data[57]
  PIN cfg_data[58]
    DIRECTION INPUT ;
    USE SIGNAL ;
    PORT
      LAYER M4 ;
        RECT  0 42.096 0.084 42.12 ;
    END
  END cfg_data[58]
  PIN cfg_data[59]
    DIRECTION INPUT ;
    USE SIGNAL ;
    PORT
      LAYER M4 ;
        RECT  0 42.192 0.084 42.216 ;
    END
  END cfg_data[59]
  PIN cfg_data[5]
    DIRECTION INPUT ;
    USE SIGNAL ;
    PORT
      LAYER M4 ;
        RECT  0 49.296 0.084 49.32 ;
    END
  END cfg_data[5]
  PIN cfg_data[60]
    DIRECTION INPUT ;
    USE SIGNAL ;
    PORT
      LAYER M4 ;
        RECT  0 42.288 0.084 42.312 ;
    END
  END cfg_data[60]
  PIN cfg_data[61]
    DIRECTION INPUT ;
    USE SIGNAL ;
    PORT
      LAYER M4 ;
        RECT  0 42.384 0.084 42.408 ;
    END
  END cfg_data[61]
  PIN cfg_data[62]
    DIRECTION INPUT ;
    USE SIGNAL ;
    PORT
      LAYER M4 ;
        RECT  0 42.48 0.084 42.504 ;
    END
  END cfg_data[62]
  PIN cfg_data[63]
    DIRECTION INPUT ;
    USE SIGNAL ;
    PORT
      LAYER M4 ;
        RECT  0 42.576 0.084 42.6 ;
    END
  END cfg_data[63]
  PIN cfg_data[64]
    DIRECTION INPUT ;
    USE SIGNAL ;
    PORT
      LAYER M4 ;
        RECT  0 51.888 0.084 51.912 ;
    END
  END cfg_data[64]
  PIN cfg_data[65]
    DIRECTION INPUT ;
    USE SIGNAL ;
    PORT
      LAYER M4 ;
        RECT  0 51.984 0.084 52.008 ;
    END
  END cfg_data[65]
  PIN cfg_data[66]
    DIRECTION INPUT ;
    USE SIGNAL ;
    PORT
      LAYER M4 ;
        RECT  0 52.08 0.084 52.104 ;
    END
  END cfg_data[66]
  PIN cfg_data[67]
    DIRECTION INPUT ;
    USE SIGNAL ;
    PORT
      LAYER M4 ;
        RECT  0 52.176 0.084 52.2 ;
    END
  END cfg_data[67]
  PIN cfg_data[68]
    DIRECTION INPUT ;
    USE SIGNAL ;
    PORT
      LAYER M4 ;
        RECT  0 52.272 0.084 52.296 ;
    END
  END cfg_data[68]
  PIN cfg_data[69]
    DIRECTION INPUT ;
    USE SIGNAL ;
    PORT
      LAYER M4 ;
        RECT  0 52.368 0.084 52.392 ;
    END
  END cfg_data[69]
  PIN cfg_data[6]
    DIRECTION INPUT ;
    USE SIGNAL ;
    PORT
      LAYER M4 ;
        RECT  0 49.392 0.084 49.416 ;
    END
  END cfg_data[6]
  PIN cfg_data[70]
    DIRECTION INPUT ;
    USE SIGNAL ;
    PORT
      LAYER M4 ;
        RECT  0 52.464 0.084 52.488 ;
    END
  END cfg_data[70]
  PIN cfg_data[71]
    DIRECTION INPUT ;
    USE SIGNAL ;
    PORT
      LAYER M4 ;
        RECT  0 52.56 0.084 52.584 ;
    END
  END cfg_data[71]
  PIN cfg_data[72]
    DIRECTION INPUT ;
    USE SIGNAL ;
    PORT
      LAYER M4 ;
        RECT  0 52.656 0.084 52.68 ;
    END
  END cfg_data[72]
  PIN cfg_data[73]
    DIRECTION INPUT ;
    USE SIGNAL ;
    PORT
      LAYER M4 ;
        RECT  0 52.752 0.084 52.776 ;
    END
  END cfg_data[73]
  PIN cfg_data[74]
    DIRECTION INPUT ;
    USE SIGNAL ;
    PORT
      LAYER M4 ;
        RECT  0 52.848 0.084 52.872 ;
    END
  END cfg_data[74]
  PIN cfg_data[75]
    DIRECTION INPUT ;
    USE SIGNAL ;
    PORT
      LAYER M4 ;
        RECT  0 52.944 0.084 52.968 ;
    END
  END cfg_data[75]
  PIN cfg_data[76]
    DIRECTION INPUT ;
    USE SIGNAL ;
    PORT
      LAYER M4 ;
        RECT  0 53.04 0.084 53.064 ;
    END
  END cfg_data[76]
  PIN cfg_data[77]
    DIRECTION INPUT ;
    USE SIGNAL ;
    PORT
      LAYER M4 ;
        RECT  0 53.136 0.084 53.16 ;
    END
  END cfg_data[77]
  PIN cfg_data[78]
    DIRECTION INPUT ;
    USE SIGNAL ;
    PORT
      LAYER M4 ;
        RECT  0 53.232 0.084 53.256 ;
    END
  END cfg_data[78]
  PIN cfg_data[79]
    DIRECTION INPUT ;
    USE SIGNAL ;
    PORT
      LAYER M4 ;
        RECT  0 53.328 0.084 53.352 ;
    END
  END cfg_data[79]
  PIN cfg_data[7]
    DIRECTION INPUT ;
    USE SIGNAL ;
    PORT
      LAYER M4 ;
        RECT  0 49.488 0.084 49.512 ;
    END
  END cfg_data[7]
  PIN cfg_data[80]
    DIRECTION INPUT ;
    USE SIGNAL ;
    PORT
      LAYER M4 ;
        RECT  0 53.424 0.084 53.448 ;
    END
  END cfg_data[80]
  PIN cfg_data[81]
    DIRECTION INPUT ;
    USE SIGNAL ;
    PORT
      LAYER M4 ;
        RECT  0 53.52 0.084 53.544 ;
    END
  END cfg_data[81]
  PIN cfg_data[82]
    DIRECTION INPUT ;
    USE SIGNAL ;
    PORT
      LAYER M4 ;
        RECT  0 53.616 0.084 53.64 ;
    END
  END cfg_data[82]
  PIN cfg_data[83]
    DIRECTION INPUT ;
    USE SIGNAL ;
    PORT
      LAYER M4 ;
        RECT  0 53.712 0.084 53.736 ;
    END
  END cfg_data[83]
  PIN cfg_data[84]
    DIRECTION INPUT ;
    USE SIGNAL ;
    PORT
      LAYER M4 ;
        RECT  0 53.808 0.084 53.832 ;
    END
  END cfg_data[84]
  PIN cfg_data[85]
    DIRECTION INPUT ;
    USE SIGNAL ;
    PORT
      LAYER M4 ;
        RECT  0 53.904 0.084 53.928 ;
    END
  END cfg_data[85]
  PIN cfg_data[86]
    DIRECTION INPUT ;
    USE SIGNAL ;
    PORT
      LAYER M4 ;
        RECT  0 54 0.084 54.024 ;
    END
  END cfg_data[86]
  PIN cfg_data[87]
    DIRECTION INPUT ;
    USE SIGNAL ;
    PORT
      LAYER M4 ;
        RECT  0 54.096 0.084 54.12 ;
    END
  END cfg_data[87]
  PIN cfg_data[88]
    DIRECTION INPUT ;
    USE SIGNAL ;
    PORT
      LAYER M4 ;
        RECT  0 54.192 0.084 54.216 ;
    END
  END cfg_data[88]
  PIN cfg_data[89]
    DIRECTION INPUT ;
    USE SIGNAL ;
    PORT
      LAYER M4 ;
        RECT  0 54.288 0.084 54.312 ;
    END
  END cfg_data[89]
  PIN cfg_data[8]
    DIRECTION INPUT ;
    USE SIGNAL ;
    PORT
      LAYER M4 ;
        RECT  0 49.584 0.084 49.608 ;
    END
  END cfg_data[8]
  PIN cfg_data[90]
    DIRECTION INPUT ;
    USE SIGNAL ;
    PORT
      LAYER M4 ;
        RECT  0 54.384 0.084 54.408 ;
    END
  END cfg_data[90]
  PIN cfg_data[91]
    DIRECTION INPUT ;
    USE SIGNAL ;
    PORT
      LAYER M4 ;
        RECT  0 54.48 0.084 54.504 ;
    END
  END cfg_data[91]
  PIN cfg_data[92]
    DIRECTION INPUT ;
    USE SIGNAL ;
    PORT
      LAYER M4 ;
        RECT  0 54.576 0.084 54.6 ;
    END
  END cfg_data[92]
  PIN cfg_data[93]
    DIRECTION INPUT ;
    USE SIGNAL ;
    PORT
      LAYER M4 ;
        RECT  0 54.672 0.084 54.696 ;
    END
  END cfg_data[93]
  PIN cfg_data[94]
    DIRECTION INPUT ;
    USE SIGNAL ;
    PORT
      LAYER M4 ;
        RECT  0 54.768 0.084 54.792 ;
    END
  END cfg_data[94]
  PIN cfg_data[95]
    DIRECTION INPUT ;
    USE SIGNAL ;
    PORT
      LAYER M4 ;
        RECT  0 54.864 0.084 54.888 ;
    END
  END cfg_data[95]
  PIN cfg_data[96]
    DIRECTION INPUT ;
    USE SIGNAL ;
    PORT
      LAYER M4 ;
        RECT  0 45.744 0.084 45.768 ;
    END
  END cfg_data[96]
  PIN cfg_data[97]
    DIRECTION INPUT ;
    USE SIGNAL ;
    PORT
      LAYER M4 ;
        RECT  0 45.84 0.084 45.864 ;
    END
  END cfg_data[97]
  PIN cfg_data[98]
    DIRECTION INPUT ;
    USE SIGNAL ;
    PORT
      LAYER M4 ;
        RECT  0 45.936 0.084 45.96 ;
    END
  END cfg_data[98]
  PIN cfg_data[99]
    DIRECTION INPUT ;
    USE SIGNAL ;
    PORT
      LAYER M4 ;
        RECT  0 46.032 0.084 46.056 ;
    END
  END cfg_data[99]
  PIN cfg_data[9]
    DIRECTION INPUT ;
    USE SIGNAL ;
    PORT
      LAYER M4 ;
        RECT  0 49.68 0.084 49.704 ;
    END
  END cfg_data[9]
  PIN cfg_row[0]
    DIRECTION INPUT ;
    USE SIGNAL ;
    PORT
      LAYER M4 ;
        RECT  0 68.688 0.084 68.712 ;
    END
  END cfg_row[0]
  PIN cfg_row[1]
    DIRECTION INPUT ;
    USE SIGNAL ;
    PORT
      LAYER M4 ;
        RECT  0 68.784 0.084 68.808 ;
    END
  END cfg_row[1]
  PIN cfg_row[2]
    DIRECTION INPUT ;
    USE SIGNAL ;
    PORT
      LAYER M4 ;
        RECT  0 68.88 0.084 68.904 ;
    END
  END cfg_row[2]
  PIN cfg_row[3]
    DIRECTION INPUT ;
    USE SIGNAL ;
    PORT
      LAYER M4 ;
        RECT  0 68.976 0.084 69 ;
    END
  END cfg_row[3]
  PIN cfg_row[4]
    DIRECTION INPUT ;
    USE SIGNAL ;
    PORT
      LAYER M4 ;
        RECT  0 69.072 0.084 69.096 ;
    END
  END cfg_row[4]
  PIN cfg_row[5]
    DIRECTION INPUT ;
    USE SIGNAL ;
    PORT
      LAYER M4 ;
        RECT  0 69.168 0.084 69.192 ;
    END
  END cfg_row[5]
  PIN cfg_row[6]
    DIRECTION INPUT ;
    USE SIGNAL ;
    PORT
      LAYER M4 ;
        RECT  0 69.264 0.084 69.288 ;
    END
  END cfg_row[6]
  PIN cfg_we
    DIRECTION INPUT ;
    USE SIGNAL ;
    PORT
      LAYER M4 ;
        RECT  0 72.528 0.084 72.552 ;
    END
  END cfg_we
  PIN clk
    DIRECTION INPUT ;
    USE SIGNAL ;
    PORT
      LAYER M4 ;
        RECT  0 58.512 0.084 58.536 ;
    END
  END clk
  PIN fault
    DIRECTION OUTPUT ;
    USE SIGNAL ;
    PORT
      LAYER M4 ;
        RECT  86.316 83.76 86.4 83.784 ;
    END
  END fault
  PIN length[0]
    DIRECTION INPUT ;
    USE SIGNAL ;
    PORT
      LAYER M4 ;
        RECT  0 77.424 0.084 77.448 ;
    END
  END length[0]
  PIN length[10]
    DIRECTION INPUT ;
    USE SIGNAL ;
    PORT
      LAYER M4 ;
        RECT  0 78.384 0.084 78.408 ;
    END
  END length[10]
  PIN length[11]
    DIRECTION INPUT ;
    USE SIGNAL ;
    PORT
      LAYER M4 ;
        RECT  0 78.48 0.084 78.504 ;
    END
  END length[11]
  PIN length[12]
    DIRECTION INPUT ;
    USE SIGNAL ;
    PORT
      LAYER M4 ;
        RECT  0 78.576 0.084 78.6 ;
    END
  END length[12]
  PIN length[13]
    DIRECTION INPUT ;
    USE SIGNAL ;
    PORT
      LAYER M4 ;
        RECT  0 78.672 0.084 78.696 ;
    END
  END length[13]
  PIN length[14]
    DIRECTION INPUT ;
    USE SIGNAL ;
    PORT
      LAYER M4 ;
        RECT  0 78.768 0.084 78.792 ;
    END
  END length[14]
  PIN length[15]
    DIRECTION INPUT ;
    USE SIGNAL ;
    PORT
      LAYER M4 ;
        RECT  0 78.864 0.084 78.888 ;
    END
  END length[15]
  PIN length[1]
    DIRECTION INPUT ;
    USE SIGNAL ;
    PORT
      LAYER M4 ;
        RECT  0 77.52 0.084 77.544 ;
    END
  END length[1]
  PIN length[2]
    DIRECTION INPUT ;
    USE SIGNAL ;
    PORT
      LAYER M4 ;
        RECT  0 77.616 0.084 77.64 ;
    END
  END length[2]
  PIN length[3]
    DIRECTION INPUT ;
    USE SIGNAL ;
    PORT
      LAYER M4 ;
        RECT  0 77.712 0.084 77.736 ;
    END
  END length[3]
  PIN length[4]
    DIRECTION INPUT ;
    USE SIGNAL ;
    PORT
      LAYER M4 ;
        RECT  0 77.808 0.084 77.832 ;
    END
  END length[4]
  PIN length[5]
    DIRECTION INPUT ;
    USE SIGNAL ;
    PORT
      LAYER M4 ;
        RECT  0 77.904 0.084 77.928 ;
    END
  END length[5]
  PIN length[6]
    DIRECTION INPUT ;
    USE SIGNAL ;
    PORT
      LAYER M4 ;
        RECT  0 78 0.084 78.024 ;
    END
  END length[6]
  PIN length[7]
    DIRECTION INPUT ;
    USE SIGNAL ;
    PORT
      LAYER M4 ;
        RECT  0 78.096 0.084 78.12 ;
    END
  END length[7]
  PIN length[8]
    DIRECTION INPUT ;
    USE SIGNAL ;
    PORT
      LAYER M4 ;
        RECT  0 78.192 0.084 78.216 ;
    END
  END length[8]
  PIN length[9]
    DIRECTION INPUT ;
    USE SIGNAL ;
    PORT
      LAYER M4 ;
        RECT  0 78.288 0.084 78.312 ;
    END
  END length[9]
  PIN p_fault[0]
    DIRECTION INPUT ;
    USE SIGNAL ;
    PORT
      LAYER M4 ;
        RECT  0 82.512 0.084 82.536 ;
    END
  END p_fault[0]
  PIN p_fault[1]
    DIRECTION INPUT ;
    USE SIGNAL ;
    PORT
      LAYER M4 ;
        RECT  0 82.608 0.084 82.632 ;
    END
  END p_fault[1]
  PIN p_fault[2]
    DIRECTION INPUT ;
    USE SIGNAL ;
    PORT
      LAYER M4 ;
        RECT  0 82.704 0.084 82.728 ;
    END
  END p_fault[2]
  PIN p_fault[3]
    DIRECTION INPUT ;
    USE SIGNAL ;
    PORT
      LAYER M4 ;
        RECT  0 82.8 0.084 82.824 ;
    END
  END p_fault[3]
  PIN r_bank[0]
    DIRECTION OUTPUT ;
    USE SIGNAL ;
    PORT
      LAYER M4 ;
        RECT  86.316 60.528 86.4 60.552 ;
    END
  END r_bank[0]
  PIN r_bank[10]
    DIRECTION OUTPUT ;
    USE SIGNAL ;
    PORT
      LAYER M4 ;
        RECT  86.316 61.488 86.4 61.512 ;
    END
  END r_bank[10]
  PIN r_bank[11]
    DIRECTION OUTPUT ;
    USE SIGNAL ;
    PORT
      LAYER M4 ;
        RECT  86.316 61.584 86.4 61.608 ;
    END
  END r_bank[11]
  PIN r_bank[12]
    DIRECTION OUTPUT ;
    USE SIGNAL ;
    PORT
      LAYER M4 ;
        RECT  86.316 61.68 86.4 61.704 ;
    END
  END r_bank[12]
  PIN r_bank[13]
    DIRECTION OUTPUT ;
    USE SIGNAL ;
    PORT
      LAYER M4 ;
        RECT  86.316 61.776 86.4 61.8 ;
    END
  END r_bank[13]
  PIN r_bank[14]
    DIRECTION OUTPUT ;
    USE SIGNAL ;
    PORT
      LAYER M4 ;
        RECT  86.316 61.872 86.4 61.896 ;
    END
  END r_bank[14]
  PIN r_bank[15]
    DIRECTION OUTPUT ;
    USE SIGNAL ;
    PORT
      LAYER M4 ;
        RECT  86.316 61.968 86.4 61.992 ;
    END
  END r_bank[15]
  PIN r_bank[16]
    DIRECTION OUTPUT ;
    USE SIGNAL ;
    PORT
      LAYER M4 ;
        RECT  86.316 62.064 86.4 62.088 ;
    END
  END r_bank[16]
  PIN r_bank[17]
    DIRECTION OUTPUT ;
    USE SIGNAL ;
    PORT
      LAYER M4 ;
        RECT  86.316 62.16 86.4 62.184 ;
    END
  END r_bank[17]
  PIN r_bank[18]
    DIRECTION OUTPUT ;
    USE SIGNAL ;
    PORT
      LAYER M4 ;
        RECT  86.316 62.256 86.4 62.28 ;
    END
  END r_bank[18]
  PIN r_bank[19]
    DIRECTION OUTPUT ;
    USE SIGNAL ;
    PORT
      LAYER M4 ;
        RECT  86.316 62.352 86.4 62.376 ;
    END
  END r_bank[19]
  PIN r_bank[1]
    DIRECTION OUTPUT ;
    USE SIGNAL ;
    PORT
      LAYER M4 ;
        RECT  86.316 60.624 86.4 60.648 ;
    END
  END r_bank[1]
  PIN r_bank[20]
    DIRECTION OUTPUT ;
    USE SIGNAL ;
    PORT
      LAYER M4 ;
        RECT  86.316 62.448 86.4 62.472 ;
    END
  END r_bank[20]
  PIN r_bank[21]
    DIRECTION OUTPUT ;
    USE SIGNAL ;
    PORT
      LAYER M4 ;
        RECT  86.316 62.544 86.4 62.568 ;
    END
  END r_bank[21]
  PIN r_bank[22]
    DIRECTION OUTPUT ;
    USE SIGNAL ;
    PORT
      LAYER M4 ;
        RECT  86.316 62.64 86.4 62.664 ;
    END
  END r_bank[22]
  PIN r_bank[23]
    DIRECTION OUTPUT ;
    USE SIGNAL ;
    PORT
      LAYER M4 ;
        RECT  86.316 62.736 86.4 62.76 ;
    END
  END r_bank[23]
  PIN r_bank[24]
    DIRECTION OUTPUT ;
    USE SIGNAL ;
    PORT
      LAYER M4 ;
        RECT  86.316 62.832 86.4 62.856 ;
    END
  END r_bank[24]
  PIN r_bank[25]
    DIRECTION OUTPUT ;
    USE SIGNAL ;
    PORT
      LAYER M4 ;
        RECT  86.316 62.928 86.4 62.952 ;
    END
  END r_bank[25]
  PIN r_bank[26]
    DIRECTION OUTPUT ;
    USE SIGNAL ;
    PORT
      LAYER M4 ;
        RECT  86.316 63.024 86.4 63.048 ;
    END
  END r_bank[26]
  PIN r_bank[27]
    DIRECTION OUTPUT ;
    USE SIGNAL ;
    PORT
      LAYER M4 ;
        RECT  86.316 63.12 86.4 63.144 ;
    END
  END r_bank[27]
  PIN r_bank[28]
    DIRECTION OUTPUT ;
    USE SIGNAL ;
    PORT
      LAYER M4 ;
        RECT  86.316 63.216 86.4 63.24 ;
    END
  END r_bank[28]
  PIN r_bank[29]
    DIRECTION OUTPUT ;
    USE SIGNAL ;
    PORT
      LAYER M4 ;
        RECT  86.316 63.312 86.4 63.336 ;
    END
  END r_bank[29]
  PIN r_bank[2]
    DIRECTION OUTPUT ;
    USE SIGNAL ;
    PORT
      LAYER M4 ;
        RECT  86.316 60.72 86.4 60.744 ;
    END
  END r_bank[2]
  PIN r_bank[30]
    DIRECTION OUTPUT ;
    USE SIGNAL ;
    PORT
      LAYER M4 ;
        RECT  86.316 63.408 86.4 63.432 ;
    END
  END r_bank[30]
  PIN r_bank[31]
    DIRECTION OUTPUT ;
    USE SIGNAL ;
    PORT
      LAYER M4 ;
        RECT  86.316 63.504 86.4 63.528 ;
    END
  END r_bank[31]
  PIN r_bank[32]
    DIRECTION OUTPUT ;
    USE SIGNAL ;
    PORT
      LAYER M4 ;
        RECT  86.316 63.6 86.4 63.624 ;
    END
  END r_bank[32]
  PIN r_bank[33]
    DIRECTION OUTPUT ;
    USE SIGNAL ;
    PORT
      LAYER M4 ;
        RECT  86.316 63.696 86.4 63.72 ;
    END
  END r_bank[33]
  PIN r_bank[34]
    DIRECTION OUTPUT ;
    USE SIGNAL ;
    PORT
      LAYER M4 ;
        RECT  86.316 63.792 86.4 63.816 ;
    END
  END r_bank[34]
  PIN r_bank[35]
    DIRECTION OUTPUT ;
    USE SIGNAL ;
    PORT
      LAYER M4 ;
        RECT  86.316 63.888 86.4 63.912 ;
    END
  END r_bank[35]
  PIN r_bank[36]
    DIRECTION OUTPUT ;
    USE SIGNAL ;
    PORT
      LAYER M4 ;
        RECT  86.316 63.984 86.4 64.008 ;
    END
  END r_bank[36]
  PIN r_bank[37]
    DIRECTION OUTPUT ;
    USE SIGNAL ;
    PORT
      LAYER M4 ;
        RECT  86.316 64.08 86.4 64.104 ;
    END
  END r_bank[37]
  PIN r_bank[38]
    DIRECTION OUTPUT ;
    USE SIGNAL ;
    PORT
      LAYER M4 ;
        RECT  86.316 64.176 86.4 64.2 ;
    END
  END r_bank[38]
  PIN r_bank[39]
    DIRECTION OUTPUT ;
    USE SIGNAL ;
    PORT
      LAYER M4 ;
        RECT  86.316 64.272 86.4 64.296 ;
    END
  END r_bank[39]
  PIN r_bank[3]
    DIRECTION OUTPUT ;
    USE SIGNAL ;
    PORT
      LAYER M4 ;
        RECT  86.316 60.816 86.4 60.84 ;
    END
  END r_bank[3]
  PIN r_bank[40]
    DIRECTION OUTPUT ;
    USE SIGNAL ;
    PORT
      LAYER M4 ;
        RECT  86.316 64.368 86.4 64.392 ;
    END
  END r_bank[40]
  PIN r_bank[41]
    DIRECTION OUTPUT ;
    USE SIGNAL ;
    PORT
      LAYER M4 ;
        RECT  86.316 64.464 86.4 64.488 ;
    END
  END r_bank[41]
  PIN r_bank[42]
    DIRECTION OUTPUT ;
    USE SIGNAL ;
    PORT
      LAYER M4 ;
        RECT  86.316 64.56 86.4 64.584 ;
    END
  END r_bank[42]
  PIN r_bank[43]
    DIRECTION OUTPUT ;
    USE SIGNAL ;
    PORT
      LAYER M4 ;
        RECT  86.316 64.656 86.4 64.68 ;
    END
  END r_bank[43]
  PIN r_bank[44]
    DIRECTION OUTPUT ;
    USE SIGNAL ;
    PORT
      LAYER M4 ;
        RECT  86.316 64.752 86.4 64.776 ;
    END
  END r_bank[44]
  PIN r_bank[45]
    DIRECTION OUTPUT ;
    USE SIGNAL ;
    PORT
      LAYER M4 ;
        RECT  86.316 64.848 86.4 64.872 ;
    END
  END r_bank[45]
  PIN r_bank[46]
    DIRECTION OUTPUT ;
    USE SIGNAL ;
    PORT
      LAYER M4 ;
        RECT  86.316 64.944 86.4 64.968 ;
    END
  END r_bank[46]
  PIN r_bank[47]
    DIRECTION OUTPUT ;
    USE SIGNAL ;
    PORT
      LAYER M4 ;
        RECT  86.316 65.04 86.4 65.064 ;
    END
  END r_bank[47]
  PIN r_bank[48]
    DIRECTION OUTPUT ;
    USE SIGNAL ;
    PORT
      LAYER M4 ;
        RECT  86.316 65.136 86.4 65.16 ;
    END
  END r_bank[48]
  PIN r_bank[49]
    DIRECTION OUTPUT ;
    USE SIGNAL ;
    PORT
      LAYER M4 ;
        RECT  86.316 65.232 86.4 65.256 ;
    END
  END r_bank[49]
  PIN r_bank[4]
    DIRECTION OUTPUT ;
    USE SIGNAL ;
    PORT
      LAYER M4 ;
        RECT  86.316 60.912 86.4 60.936 ;
    END
  END r_bank[4]
  PIN r_bank[50]
    DIRECTION OUTPUT ;
    USE SIGNAL ;
    PORT
      LAYER M4 ;
        RECT  86.316 65.328 86.4 65.352 ;
    END
  END r_bank[50]
  PIN r_bank[51]
    DIRECTION OUTPUT ;
    USE SIGNAL ;
    PORT
      LAYER M4 ;
        RECT  86.316 65.424 86.4 65.448 ;
    END
  END r_bank[51]
  PIN r_bank[52]
    DIRECTION OUTPUT ;
    USE SIGNAL ;
    PORT
      LAYER M4 ;
        RECT  86.316 65.52 86.4 65.544 ;
    END
  END r_bank[52]
  PIN r_bank[53]
    DIRECTION OUTPUT ;
    USE SIGNAL ;
    PORT
      LAYER M4 ;
        RECT  86.316 65.616 86.4 65.64 ;
    END
  END r_bank[53]
  PIN r_bank[54]
    DIRECTION OUTPUT ;
    USE SIGNAL ;
    PORT
      LAYER M4 ;
        RECT  86.316 65.712 86.4 65.736 ;
    END
  END r_bank[54]
  PIN r_bank[55]
    DIRECTION OUTPUT ;
    USE SIGNAL ;
    PORT
      LAYER M4 ;
        RECT  86.316 65.808 86.4 65.832 ;
    END
  END r_bank[55]
  PIN r_bank[56]
    DIRECTION OUTPUT ;
    USE SIGNAL ;
    PORT
      LAYER M4 ;
        RECT  86.316 65.904 86.4 65.928 ;
    END
  END r_bank[56]
  PIN r_bank[57]
    DIRECTION OUTPUT ;
    USE SIGNAL ;
    PORT
      LAYER M4 ;
        RECT  86.316 66 86.4 66.024 ;
    END
  END r_bank[57]
  PIN r_bank[58]
    DIRECTION OUTPUT ;
    USE SIGNAL ;
    PORT
      LAYER M4 ;
        RECT  86.316 66.096 86.4 66.12 ;
    END
  END r_bank[58]
  PIN r_bank[59]
    DIRECTION OUTPUT ;
    USE SIGNAL ;
    PORT
      LAYER M4 ;
        RECT  86.316 66.192 86.4 66.216 ;
    END
  END r_bank[59]
  PIN r_bank[5]
    DIRECTION OUTPUT ;
    USE SIGNAL ;
    PORT
      LAYER M4 ;
        RECT  86.316 61.008 86.4 61.032 ;
    END
  END r_bank[5]
  PIN r_bank[60]
    DIRECTION OUTPUT ;
    USE SIGNAL ;
    PORT
      LAYER M4 ;
        RECT  86.316 66.288 86.4 66.312 ;
    END
  END r_bank[60]
  PIN r_bank[61]
    DIRECTION OUTPUT ;
    USE SIGNAL ;
    PORT
      LAYER M4 ;
        RECT  86.316 66.384 86.4 66.408 ;
    END
  END r_bank[61]
  PIN r_bank[62]
    DIRECTION OUTPUT ;
    USE SIGNAL ;
    PORT
      LAYER M4 ;
        RECT  86.316 66.48 86.4 66.504 ;
    END
  END r_bank[62]
  PIN r_bank[63]
    DIRECTION OUTPUT ;
    USE SIGNAL ;
    PORT
      LAYER M4 ;
        RECT  86.316 66.576 86.4 66.6 ;
    END
  END r_bank[63]
  PIN r_bank[6]
    DIRECTION OUTPUT ;
    USE SIGNAL ;
    PORT
      LAYER M4 ;
        RECT  86.316 61.104 86.4 61.128 ;
    END
  END r_bank[6]
  PIN r_bank[7]
    DIRECTION OUTPUT ;
    USE SIGNAL ;
    PORT
      LAYER M4 ;
        RECT  86.316 61.2 86.4 61.224 ;
    END
  END r_bank[7]
  PIN r_bank[8]
    DIRECTION OUTPUT ;
    USE SIGNAL ;
    PORT
      LAYER M4 ;
        RECT  86.316 61.296 86.4 61.32 ;
    END
  END r_bank[8]
  PIN r_bank[9]
    DIRECTION OUTPUT ;
    USE SIGNAL ;
    PORT
      LAYER M4 ;
        RECT  86.316 61.392 86.4 61.416 ;
    END
  END r_bank[9]
  PIN r_data[0]
    DIRECTION OUTPUT ;
    USE SIGNAL ;
    PORT
      LAYER M4 ;
        RECT  86.316 52.752 86.4 52.776 ;
    END
  END r_data[0]
  PIN r_data[100]
    DIRECTION OUTPUT ;
    USE SIGNAL ;
    PORT
      LAYER M4 ;
        RECT  86.316 50.064 86.4 50.088 ;
    END
  END r_data[100]
  PIN r_data[101]
    DIRECTION OUTPUT ;
    USE SIGNAL ;
    PORT
      LAYER M4 ;
        RECT  86.316 50.16 86.4 50.184 ;
    END
  END r_data[101]
  PIN r_data[102]
    DIRECTION OUTPUT ;
    USE SIGNAL ;
    PORT
      LAYER M4 ;
        RECT  86.316 50.256 86.4 50.28 ;
    END
  END r_data[102]
  PIN r_data[103]
    DIRECTION OUTPUT ;
    USE SIGNAL ;
    PORT
      LAYER M4 ;
        RECT  86.316 50.352 86.4 50.376 ;
    END
  END r_data[103]
  PIN r_data[104]
    DIRECTION OUTPUT ;
    USE SIGNAL ;
    PORT
      LAYER M4 ;
        RECT  86.316 50.448 86.4 50.472 ;
    END
  END r_data[104]
  PIN r_data[105]
    DIRECTION OUTPUT ;
    USE SIGNAL ;
    PORT
      LAYER M4 ;
        RECT  86.316 50.544 86.4 50.568 ;
    END
  END r_data[105]
  PIN r_data[106]
    DIRECTION OUTPUT ;
    USE SIGNAL ;
    PORT
      LAYER M4 ;
        RECT  86.316 50.64 86.4 50.664 ;
    END
  END r_data[106]
  PIN r_data[107]
    DIRECTION OUTPUT ;
    USE SIGNAL ;
    PORT
      LAYER M4 ;
        RECT  86.316 50.736 86.4 50.76 ;
    END
  END r_data[107]
  PIN r_data[108]
    DIRECTION OUTPUT ;
    USE SIGNAL ;
    PORT
      LAYER M4 ;
        RECT  86.316 50.832 86.4 50.856 ;
    END
  END r_data[108]
  PIN r_data[109]
    DIRECTION OUTPUT ;
    USE SIGNAL ;
    PORT
      LAYER M4 ;
        RECT  86.316 50.928 86.4 50.952 ;
    END
  END r_data[109]
  PIN r_data[10]
    DIRECTION OUTPUT ;
    USE SIGNAL ;
    PORT
      LAYER M4 ;
        RECT  86.316 53.712 86.4 53.736 ;
    END
  END r_data[10]
  PIN r_data[110]
    DIRECTION OUTPUT ;
    USE SIGNAL ;
    PORT
      LAYER M4 ;
        RECT  86.316 51.024 86.4 51.048 ;
    END
  END r_data[110]
  PIN r_data[111]
    DIRECTION OUTPUT ;
    USE SIGNAL ;
    PORT
      LAYER M4 ;
        RECT  86.316 51.12 86.4 51.144 ;
    END
  END r_data[111]
  PIN r_data[112]
    DIRECTION OUTPUT ;
    USE SIGNAL ;
    PORT
      LAYER M4 ;
        RECT  86.316 51.216 86.4 51.24 ;
    END
  END r_data[112]
  PIN r_data[113]
    DIRECTION OUTPUT ;
    USE SIGNAL ;
    PORT
      LAYER M4 ;
        RECT  86.316 51.312 86.4 51.336 ;
    END
  END r_data[113]
  PIN r_data[114]
    DIRECTION OUTPUT ;
    USE SIGNAL ;
    PORT
      LAYER M4 ;
        RECT  86.316 51.408 86.4 51.432 ;
    END
  END r_data[114]
  PIN r_data[115]
    DIRECTION OUTPUT ;
    USE SIGNAL ;
    PORT
      LAYER M4 ;
        RECT  86.316 51.504 86.4 51.528 ;
    END
  END r_data[115]
  PIN r_data[116]
    DIRECTION OUTPUT ;
    USE SIGNAL ;
    PORT
      LAYER M4 ;
        RECT  86.316 51.6 86.4 51.624 ;
    END
  END r_data[116]
  PIN r_data[117]
    DIRECTION OUTPUT ;
    USE SIGNAL ;
    PORT
      LAYER M4 ;
        RECT  86.316 51.696 86.4 51.72 ;
    END
  END r_data[117]
  PIN r_data[118]
    DIRECTION OUTPUT ;
    USE SIGNAL ;
    PORT
      LAYER M4 ;
        RECT  86.316 51.792 86.4 51.816 ;
    END
  END r_data[118]
  PIN r_data[119]
    DIRECTION OUTPUT ;
    USE SIGNAL ;
    PORT
      LAYER M4 ;
        RECT  86.316 51.888 86.4 51.912 ;
    END
  END r_data[119]
  PIN r_data[11]
    DIRECTION OUTPUT ;
    USE SIGNAL ;
    PORT
      LAYER M4 ;
        RECT  86.316 53.808 86.4 53.832 ;
    END
  END r_data[11]
  PIN r_data[120]
    DIRECTION OUTPUT ;
    USE SIGNAL ;
    PORT
      LAYER M4 ;
        RECT  86.316 51.984 86.4 52.008 ;
    END
  END r_data[120]
  PIN r_data[121]
    DIRECTION OUTPUT ;
    USE SIGNAL ;
    PORT
      LAYER M4 ;
        RECT  86.316 52.08 86.4 52.104 ;
    END
  END r_data[121]
  PIN r_data[122]
    DIRECTION OUTPUT ;
    USE SIGNAL ;
    PORT
      LAYER M4 ;
        RECT  86.316 52.176 86.4 52.2 ;
    END
  END r_data[122]
  PIN r_data[123]
    DIRECTION OUTPUT ;
    USE SIGNAL ;
    PORT
      LAYER M4 ;
        RECT  86.316 52.272 86.4 52.296 ;
    END
  END r_data[123]
  PIN r_data[124]
    DIRECTION OUTPUT ;
    USE SIGNAL ;
    PORT
      LAYER M4 ;
        RECT  86.316 52.368 86.4 52.392 ;
    END
  END r_data[124]
  PIN r_data[125]
    DIRECTION OUTPUT ;
    USE SIGNAL ;
    PORT
      LAYER M4 ;
        RECT  86.316 52.464 86.4 52.488 ;
    END
  END r_data[125]
  PIN r_data[126]
    DIRECTION OUTPUT ;
    USE SIGNAL ;
    PORT
      LAYER M4 ;
        RECT  86.316 52.56 86.4 52.584 ;
    END
  END r_data[126]
  PIN r_data[127]
    DIRECTION OUTPUT ;
    USE SIGNAL ;
    PORT
      LAYER M4 ;
        RECT  86.316 52.656 86.4 52.68 ;
    END
  END r_data[127]
  PIN r_data[128]
    DIRECTION OUTPUT ;
    USE SIGNAL ;
    PORT
      LAYER M4 ;
        RECT  86.316 55.824 86.4 55.848 ;
    END
  END r_data[128]
  PIN r_data[129]
    DIRECTION OUTPUT ;
    USE SIGNAL ;
    PORT
      LAYER M4 ;
        RECT  86.316 55.92 86.4 55.944 ;
    END
  END r_data[129]
  PIN r_data[12]
    DIRECTION OUTPUT ;
    USE SIGNAL ;
    PORT
      LAYER M4 ;
        RECT  86.316 53.904 86.4 53.928 ;
    END
  END r_data[12]
  PIN r_data[130]
    DIRECTION OUTPUT ;
    USE SIGNAL ;
    PORT
      LAYER M4 ;
        RECT  86.316 56.016 86.4 56.04 ;
    END
  END r_data[130]
  PIN r_data[131]
    DIRECTION OUTPUT ;
    USE SIGNAL ;
    PORT
      LAYER M4 ;
        RECT  86.316 56.112 86.4 56.136 ;
    END
  END r_data[131]
  PIN r_data[132]
    DIRECTION OUTPUT ;
    USE SIGNAL ;
    PORT
      LAYER M4 ;
        RECT  86.316 56.208 86.4 56.232 ;
    END
  END r_data[132]
  PIN r_data[133]
    DIRECTION OUTPUT ;
    USE SIGNAL ;
    PORT
      LAYER M4 ;
        RECT  86.316 56.304 86.4 56.328 ;
    END
  END r_data[133]
  PIN r_data[134]
    DIRECTION OUTPUT ;
    USE SIGNAL ;
    PORT
      LAYER M4 ;
        RECT  86.316 56.4 86.4 56.424 ;
    END
  END r_data[134]
  PIN r_data[135]
    DIRECTION OUTPUT ;
    USE SIGNAL ;
    PORT
      LAYER M4 ;
        RECT  86.316 56.496 86.4 56.52 ;
    END
  END r_data[135]
  PIN r_data[136]
    DIRECTION OUTPUT ;
    USE SIGNAL ;
    PORT
      LAYER M4 ;
        RECT  86.316 56.592 86.4 56.616 ;
    END
  END r_data[136]
  PIN r_data[137]
    DIRECTION OUTPUT ;
    USE SIGNAL ;
    PORT
      LAYER M4 ;
        RECT  86.316 56.688 86.4 56.712 ;
    END
  END r_data[137]
  PIN r_data[138]
    DIRECTION OUTPUT ;
    USE SIGNAL ;
    PORT
      LAYER M4 ;
        RECT  86.316 56.784 86.4 56.808 ;
    END
  END r_data[138]
  PIN r_data[139]
    DIRECTION OUTPUT ;
    USE SIGNAL ;
    PORT
      LAYER M4 ;
        RECT  86.316 56.88 86.4 56.904 ;
    END
  END r_data[139]
  PIN r_data[13]
    DIRECTION OUTPUT ;
    USE SIGNAL ;
    PORT
      LAYER M4 ;
        RECT  86.316 54 86.4 54.024 ;
    END
  END r_data[13]
  PIN r_data[140]
    DIRECTION OUTPUT ;
    USE SIGNAL ;
    PORT
      LAYER M4 ;
        RECT  86.316 56.976 86.4 57 ;
    END
  END r_data[140]
  PIN r_data[141]
    DIRECTION OUTPUT ;
    USE SIGNAL ;
    PORT
      LAYER M4 ;
        RECT  86.316 57.072 86.4 57.096 ;
    END
  END r_data[141]
  PIN r_data[142]
    DIRECTION OUTPUT ;
    USE SIGNAL ;
    PORT
      LAYER M4 ;
        RECT  86.316 57.168 86.4 57.192 ;
    END
  END r_data[142]
  PIN r_data[143]
    DIRECTION OUTPUT ;
    USE SIGNAL ;
    PORT
      LAYER M4 ;
        RECT  86.316 57.264 86.4 57.288 ;
    END
  END r_data[143]
  PIN r_data[144]
    DIRECTION OUTPUT ;
    USE SIGNAL ;
    PORT
      LAYER M4 ;
        RECT  86.316 57.36 86.4 57.384 ;
    END
  END r_data[144]
  PIN r_data[145]
    DIRECTION OUTPUT ;
    USE SIGNAL ;
    PORT
      LAYER M4 ;
        RECT  86.316 57.456 86.4 57.48 ;
    END
  END r_data[145]
  PIN r_data[146]
    DIRECTION OUTPUT ;
    USE SIGNAL ;
    PORT
      LAYER M4 ;
        RECT  86.316 57.552 86.4 57.576 ;
    END
  END r_data[146]
  PIN r_data[147]
    DIRECTION OUTPUT ;
    USE SIGNAL ;
    PORT
      LAYER M4 ;
        RECT  86.316 57.648 86.4 57.672 ;
    END
  END r_data[147]
  PIN r_data[148]
    DIRECTION OUTPUT ;
    USE SIGNAL ;
    PORT
      LAYER M4 ;
        RECT  86.316 57.744 86.4 57.768 ;
    END
  END r_data[148]
  PIN r_data[149]
    DIRECTION OUTPUT ;
    USE SIGNAL ;
    PORT
      LAYER M4 ;
        RECT  86.316 57.84 86.4 57.864 ;
    END
  END r_data[149]
  PIN r_data[14]
    DIRECTION OUTPUT ;
    USE SIGNAL ;
    PORT
      LAYER M4 ;
        RECT  86.316 54.096 86.4 54.12 ;
    END
  END r_data[14]
  PIN r_data[150]
    DIRECTION OUTPUT ;
    USE SIGNAL ;
    PORT
      LAYER M4 ;
        RECT  86.316 57.936 86.4 57.96 ;
    END
  END r_data[150]
  PIN r_data[151]
    DIRECTION OUTPUT ;
    USE SIGNAL ;
    PORT
      LAYER M4 ;
        RECT  86.316 58.032 86.4 58.056 ;
    END
  END r_data[151]
  PIN r_data[152]
    DIRECTION OUTPUT ;
    USE SIGNAL ;
    PORT
      LAYER M4 ;
        RECT  86.316 58.128 86.4 58.152 ;
    END
  END r_data[152]
  PIN r_data[153]
    DIRECTION OUTPUT ;
    USE SIGNAL ;
    PORT
      LAYER M4 ;
        RECT  86.316 58.224 86.4 58.248 ;
    END
  END r_data[153]
  PIN r_data[154]
    DIRECTION OUTPUT ;
    USE SIGNAL ;
    PORT
      LAYER M4 ;
        RECT  86.316 58.32 86.4 58.344 ;
    END
  END r_data[154]
  PIN r_data[155]
    DIRECTION OUTPUT ;
    USE SIGNAL ;
    PORT
      LAYER M4 ;
        RECT  86.316 58.416 86.4 58.44 ;
    END
  END r_data[155]
  PIN r_data[156]
    DIRECTION OUTPUT ;
    USE SIGNAL ;
    PORT
      LAYER M4 ;
        RECT  86.316 58.512 86.4 58.536 ;
    END
  END r_data[156]
  PIN r_data[157]
    DIRECTION OUTPUT ;
    USE SIGNAL ;
    PORT
      LAYER M4 ;
        RECT  86.316 58.608 86.4 58.632 ;
    END
  END r_data[157]
  PIN r_data[158]
    DIRECTION OUTPUT ;
    USE SIGNAL ;
    PORT
      LAYER M4 ;
        RECT  86.316 58.704 86.4 58.728 ;
    END
  END r_data[158]
  PIN r_data[159]
    DIRECTION OUTPUT ;
    USE SIGNAL ;
    PORT
      LAYER M4 ;
        RECT  86.316 58.8 86.4 58.824 ;
    END
  END r_data[159]
  PIN r_data[15]
    DIRECTION OUTPUT ;
    USE SIGNAL ;
    PORT
      LAYER M4 ;
        RECT  86.316 54.192 86.4 54.216 ;
    END
  END r_data[15]
  PIN r_data[160]
    DIRECTION OUTPUT ;
    USE SIGNAL ;
    PORT
      LAYER M4 ;
        RECT  86.316 46.608 86.4 46.632 ;
    END
  END r_data[160]
  PIN r_data[161]
    DIRECTION OUTPUT ;
    USE SIGNAL ;
    PORT
      LAYER M4 ;
        RECT  86.316 46.704 86.4 46.728 ;
    END
  END r_data[161]
  PIN r_data[162]
    DIRECTION OUTPUT ;
    USE SIGNAL ;
    PORT
      LAYER M4 ;
        RECT  86.316 46.8 86.4 46.824 ;
    END
  END r_data[162]
  PIN r_data[163]
    DIRECTION OUTPUT ;
    USE SIGNAL ;
    PORT
      LAYER M4 ;
        RECT  86.316 46.896 86.4 46.92 ;
    END
  END r_data[163]
  PIN r_data[164]
    DIRECTION OUTPUT ;
    USE SIGNAL ;
    PORT
      LAYER M4 ;
        RECT  86.316 46.992 86.4 47.016 ;
    END
  END r_data[164]
  PIN r_data[165]
    DIRECTION OUTPUT ;
    USE SIGNAL ;
    PORT
      LAYER M4 ;
        RECT  86.316 47.088 86.4 47.112 ;
    END
  END r_data[165]
  PIN r_data[166]
    DIRECTION OUTPUT ;
    USE SIGNAL ;
    PORT
      LAYER M4 ;
        RECT  86.316 47.184 86.4 47.208 ;
    END
  END r_data[166]
  PIN r_data[167]
    DIRECTION OUTPUT ;
    USE SIGNAL ;
    PORT
      LAYER M4 ;
        RECT  86.316 47.28 86.4 47.304 ;
    END
  END r_data[167]
  PIN r_data[168]
    DIRECTION OUTPUT ;
    USE SIGNAL ;
    PORT
      LAYER M4 ;
        RECT  86.316 47.376 86.4 47.4 ;
    END
  END r_data[168]
  PIN r_data[169]
    DIRECTION OUTPUT ;
    USE SIGNAL ;
    PORT
      LAYER M4 ;
        RECT  86.316 47.472 86.4 47.496 ;
    END
  END r_data[169]
  PIN r_data[16]
    DIRECTION OUTPUT ;
    USE SIGNAL ;
    PORT
      LAYER M4 ;
        RECT  86.316 54.288 86.4 54.312 ;
    END
  END r_data[16]
  PIN r_data[170]
    DIRECTION OUTPUT ;
    USE SIGNAL ;
    PORT
      LAYER M4 ;
        RECT  86.316 47.568 86.4 47.592 ;
    END
  END r_data[170]
  PIN r_data[171]
    DIRECTION OUTPUT ;
    USE SIGNAL ;
    PORT
      LAYER M4 ;
        RECT  86.316 47.664 86.4 47.688 ;
    END
  END r_data[171]
  PIN r_data[172]
    DIRECTION OUTPUT ;
    USE SIGNAL ;
    PORT
      LAYER M4 ;
        RECT  86.316 47.76 86.4 47.784 ;
    END
  END r_data[172]
  PIN r_data[173]
    DIRECTION OUTPUT ;
    USE SIGNAL ;
    PORT
      LAYER M4 ;
        RECT  86.316 47.856 86.4 47.88 ;
    END
  END r_data[173]
  PIN r_data[174]
    DIRECTION OUTPUT ;
    USE SIGNAL ;
    PORT
      LAYER M4 ;
        RECT  86.316 47.952 86.4 47.976 ;
    END
  END r_data[174]
  PIN r_data[175]
    DIRECTION OUTPUT ;
    USE SIGNAL ;
    PORT
      LAYER M4 ;
        RECT  86.316 48.048 86.4 48.072 ;
    END
  END r_data[175]
  PIN r_data[176]
    DIRECTION OUTPUT ;
    USE SIGNAL ;
    PORT
      LAYER M4 ;
        RECT  86.316 48.144 86.4 48.168 ;
    END
  END r_data[176]
  PIN r_data[177]
    DIRECTION OUTPUT ;
    USE SIGNAL ;
    PORT
      LAYER M4 ;
        RECT  86.316 48.24 86.4 48.264 ;
    END
  END r_data[177]
  PIN r_data[178]
    DIRECTION OUTPUT ;
    USE SIGNAL ;
    PORT
      LAYER M4 ;
        RECT  86.316 48.336 86.4 48.36 ;
    END
  END r_data[178]
  PIN r_data[179]
    DIRECTION OUTPUT ;
    USE SIGNAL ;
    PORT
      LAYER M4 ;
        RECT  86.316 48.432 86.4 48.456 ;
    END
  END r_data[179]
  PIN r_data[17]
    DIRECTION OUTPUT ;
    USE SIGNAL ;
    PORT
      LAYER M4 ;
        RECT  86.316 54.384 86.4 54.408 ;
    END
  END r_data[17]
  PIN r_data[180]
    DIRECTION OUTPUT ;
    USE SIGNAL ;
    PORT
      LAYER M4 ;
        RECT  86.316 48.528 86.4 48.552 ;
    END
  END r_data[180]
  PIN r_data[181]
    DIRECTION OUTPUT ;
    USE SIGNAL ;
    PORT
      LAYER M4 ;
        RECT  86.316 48.624 86.4 48.648 ;
    END
  END r_data[181]
  PIN r_data[182]
    DIRECTION OUTPUT ;
    USE SIGNAL ;
    PORT
      LAYER M4 ;
        RECT  86.316 48.72 86.4 48.744 ;
    END
  END r_data[182]
  PIN r_data[183]
    DIRECTION OUTPUT ;
    USE SIGNAL ;
    PORT
      LAYER M4 ;
        RECT  86.316 48.816 86.4 48.84 ;
    END
  END r_data[183]
  PIN r_data[184]
    DIRECTION OUTPUT ;
    USE SIGNAL ;
    PORT
      LAYER M4 ;
        RECT  86.316 48.912 86.4 48.936 ;
    END
  END r_data[184]
  PIN r_data[185]
    DIRECTION OUTPUT ;
    USE SIGNAL ;
    PORT
      LAYER M4 ;
        RECT  86.316 49.008 86.4 49.032 ;
    END
  END r_data[185]
  PIN r_data[186]
    DIRECTION OUTPUT ;
    USE SIGNAL ;
    PORT
      LAYER M4 ;
        RECT  86.316 49.104 86.4 49.128 ;
    END
  END r_data[186]
  PIN r_data[187]
    DIRECTION OUTPUT ;
    USE SIGNAL ;
    PORT
      LAYER M4 ;
        RECT  86.316 49.2 86.4 49.224 ;
    END
  END r_data[187]
  PIN r_data[188]
    DIRECTION OUTPUT ;
    USE SIGNAL ;
    PORT
      LAYER M4 ;
        RECT  86.316 49.296 86.4 49.32 ;
    END
  END r_data[188]
  PIN r_data[189]
    DIRECTION OUTPUT ;
    USE SIGNAL ;
    PORT
      LAYER M4 ;
        RECT  86.316 49.392 86.4 49.416 ;
    END
  END r_data[189]
  PIN r_data[18]
    DIRECTION OUTPUT ;
    USE SIGNAL ;
    PORT
      LAYER M4 ;
        RECT  86.316 54.48 86.4 54.504 ;
    END
  END r_data[18]
  PIN r_data[190]
    DIRECTION OUTPUT ;
    USE SIGNAL ;
    PORT
      LAYER M4 ;
        RECT  86.316 49.488 86.4 49.512 ;
    END
  END r_data[190]
  PIN r_data[191]
    DIRECTION OUTPUT ;
    USE SIGNAL ;
    PORT
      LAYER M4 ;
        RECT  86.316 49.584 86.4 49.608 ;
    END
  END r_data[191]
  PIN r_data[192]
    DIRECTION OUTPUT ;
    USE SIGNAL ;
    PORT
      LAYER M4 ;
        RECT  86.316 36.624 86.4 36.648 ;
    END
  END r_data[192]
  PIN r_data[193]
    DIRECTION OUTPUT ;
    USE SIGNAL ;
    PORT
      LAYER M4 ;
        RECT  86.316 36.72 86.4 36.744 ;
    END
  END r_data[193]
  PIN r_data[194]
    DIRECTION OUTPUT ;
    USE SIGNAL ;
    PORT
      LAYER M4 ;
        RECT  86.316 36.816 86.4 36.84 ;
    END
  END r_data[194]
  PIN r_data[195]
    DIRECTION OUTPUT ;
    USE SIGNAL ;
    PORT
      LAYER M4 ;
        RECT  86.316 36.912 86.4 36.936 ;
    END
  END r_data[195]
  PIN r_data[196]
    DIRECTION OUTPUT ;
    USE SIGNAL ;
    PORT
      LAYER M4 ;
        RECT  86.316 37.008 86.4 37.032 ;
    END
  END r_data[196]
  PIN r_data[197]
    DIRECTION OUTPUT ;
    USE SIGNAL ;
    PORT
      LAYER M4 ;
        RECT  86.316 37.104 86.4 37.128 ;
    END
  END r_data[197]
  PIN r_data[198]
    DIRECTION OUTPUT ;
    USE SIGNAL ;
    PORT
      LAYER M4 ;
        RECT  86.316 37.2 86.4 37.224 ;
    END
  END r_data[198]
  PIN r_data[199]
    DIRECTION OUTPUT ;
    USE SIGNAL ;
    PORT
      LAYER M4 ;
        RECT  86.316 37.296 86.4 37.32 ;
    END
  END r_data[199]
  PIN r_data[19]
    DIRECTION OUTPUT ;
    USE SIGNAL ;
    PORT
      LAYER M4 ;
        RECT  86.316 54.576 86.4 54.6 ;
    END
  END r_data[19]
  PIN r_data[1]
    DIRECTION OUTPUT ;
    USE SIGNAL ;
    PORT
      LAYER M4 ;
        RECT  86.316 52.848 86.4 52.872 ;
    END
  END r_data[1]
  PIN r_data[200]
    DIRECTION OUTPUT ;
    USE SIGNAL ;
    PORT
      LAYER M4 ;
        RECT  86.316 37.392 86.4 37.416 ;
    END
  END r_data[200]
  PIN r_data[201]
    DIRECTION OUTPUT ;
    USE SIGNAL ;
    PORT
      LAYER M4 ;
        RECT  86.316 37.488 86.4 37.512 ;
    END
  END r_data[201]
  PIN r_data[202]
    DIRECTION OUTPUT ;
    USE SIGNAL ;
    PORT
      LAYER M4 ;
        RECT  86.316 37.584 86.4 37.608 ;
    END
  END r_data[202]
  PIN r_data[203]
    DIRECTION OUTPUT ;
    USE SIGNAL ;
    PORT
      LAYER M4 ;
        RECT  86.316 37.68 86.4 37.704 ;
    END
  END r_data[203]
  PIN r_data[204]
    DIRECTION OUTPUT ;
    USE SIGNAL ;
    PORT
      LAYER M4 ;
        RECT  86.316 37.776 86.4 37.8 ;
    END
  END r_data[204]
  PIN r_data[205]
    DIRECTION OUTPUT ;
    USE SIGNAL ;
    PORT
      LAYER M4 ;
        RECT  86.316 37.872 86.4 37.896 ;
    END
  END r_data[205]
  PIN r_data[206]
    DIRECTION OUTPUT ;
    USE SIGNAL ;
    PORT
      LAYER M4 ;
        RECT  86.316 37.968 86.4 37.992 ;
    END
  END r_data[206]
  PIN r_data[207]
    DIRECTION OUTPUT ;
    USE SIGNAL ;
    PORT
      LAYER M4 ;
        RECT  86.316 38.064 86.4 38.088 ;
    END
  END r_data[207]
  PIN r_data[208]
    DIRECTION OUTPUT ;
    USE SIGNAL ;
    PORT
      LAYER M4 ;
        RECT  86.316 38.16 86.4 38.184 ;
    END
  END r_data[208]
  PIN r_data[209]
    DIRECTION OUTPUT ;
    USE SIGNAL ;
    PORT
      LAYER M4 ;
        RECT  86.316 38.256 86.4 38.28 ;
    END
  END r_data[209]
  PIN r_data[20]
    DIRECTION OUTPUT ;
    USE SIGNAL ;
    PORT
      LAYER M4 ;
        RECT  86.316 54.672 86.4 54.696 ;
    END
  END r_data[20]
  PIN r_data[210]
    DIRECTION OUTPUT ;
    USE SIGNAL ;
    PORT
      LAYER M4 ;
        RECT  86.316 38.352 86.4 38.376 ;
    END
  END r_data[210]
  PIN r_data[211]
    DIRECTION OUTPUT ;
    USE SIGNAL ;
    PORT
      LAYER M4 ;
        RECT  86.316 38.448 86.4 38.472 ;
    END
  END r_data[211]
  PIN r_data[212]
    DIRECTION OUTPUT ;
    USE SIGNAL ;
    PORT
      LAYER M4 ;
        RECT  86.316 38.544 86.4 38.568 ;
    END
  END r_data[212]
  PIN r_data[213]
    DIRECTION OUTPUT ;
    USE SIGNAL ;
    PORT
      LAYER M4 ;
        RECT  86.316 38.64 86.4 38.664 ;
    END
  END r_data[213]
  PIN r_data[214]
    DIRECTION OUTPUT ;
    USE SIGNAL ;
    PORT
      LAYER M4 ;
        RECT  86.316 38.736 86.4 38.76 ;
    END
  END r_data[214]
  PIN r_data[215]
    DIRECTION OUTPUT ;
    USE SIGNAL ;
    PORT
      LAYER M4 ;
        RECT  86.316 38.832 86.4 38.856 ;
    END
  END r_data[215]
  PIN r_data[216]
    DIRECTION OUTPUT ;
    USE SIGNAL ;
    PORT
      LAYER M4 ;
        RECT  86.316 38.928 86.4 38.952 ;
    END
  END r_data[216]
  PIN r_data[217]
    DIRECTION OUTPUT ;
    USE SIGNAL ;
    PORT
      LAYER M4 ;
        RECT  86.316 39.024 86.4 39.048 ;
    END
  END r_data[217]
  PIN r_data[218]
    DIRECTION OUTPUT ;
    USE SIGNAL ;
    PORT
      LAYER M4 ;
        RECT  86.316 39.12 86.4 39.144 ;
    END
  END r_data[218]
  PIN r_data[219]
    DIRECTION OUTPUT ;
    USE SIGNAL ;
    PORT
      LAYER M4 ;
        RECT  86.316 39.216 86.4 39.24 ;
    END
  END r_data[219]
  PIN r_data[21]
    DIRECTION OUTPUT ;
    USE SIGNAL ;
    PORT
      LAYER M4 ;
        RECT  86.316 54.768 86.4 54.792 ;
    END
  END r_data[21]
  PIN r_data[220]
    DIRECTION OUTPUT ;
    USE SIGNAL ;
    PORT
      LAYER M4 ;
        RECT  86.316 39.312 86.4 39.336 ;
    END
  END r_data[220]
  PIN r_data[221]
    DIRECTION OUTPUT ;
    USE SIGNAL ;
    PORT
      LAYER M4 ;
        RECT  86.316 39.408 86.4 39.432 ;
    END
  END r_data[221]
  PIN r_data[222]
    DIRECTION OUTPUT ;
    USE SIGNAL ;
    PORT
      LAYER M4 ;
        RECT  86.316 39.504 86.4 39.528 ;
    END
  END r_data[222]
  PIN r_data[223]
    DIRECTION OUTPUT ;
    USE SIGNAL ;
    PORT
      LAYER M4 ;
        RECT  86.316 39.6 86.4 39.624 ;
    END
  END r_data[223]
  PIN r_data[224]
    DIRECTION OUTPUT ;
    USE SIGNAL ;
    PORT
      LAYER M4 ;
        RECT  86.316 33.552 86.4 33.576 ;
    END
  END r_data[224]
  PIN r_data[225]
    DIRECTION OUTPUT ;
    USE SIGNAL ;
    PORT
      LAYER M4 ;
        RECT  86.316 33.648 86.4 33.672 ;
    END
  END r_data[225]
  PIN r_data[226]
    DIRECTION OUTPUT ;
    USE SIGNAL ;
    PORT
      LAYER M4 ;
        RECT  86.316 33.744 86.4 33.768 ;
    END
  END r_data[226]
  PIN r_data[227]
    DIRECTION OUTPUT ;
    USE SIGNAL ;
    PORT
      LAYER M4 ;
        RECT  86.316 33.84 86.4 33.864 ;
    END
  END r_data[227]
  PIN r_data[228]
    DIRECTION OUTPUT ;
    USE SIGNAL ;
    PORT
      LAYER M4 ;
        RECT  86.316 33.936 86.4 33.96 ;
    END
  END r_data[228]
  PIN r_data[229]
    DIRECTION OUTPUT ;
    USE SIGNAL ;
    PORT
      LAYER M4 ;
        RECT  86.316 34.032 86.4 34.056 ;
    END
  END r_data[229]
  PIN r_data[22]
    DIRECTION OUTPUT ;
    USE SIGNAL ;
    PORT
      LAYER M4 ;
        RECT  86.316 54.864 86.4 54.888 ;
    END
  END r_data[22]
  PIN r_data[230]
    DIRECTION OUTPUT ;
    USE SIGNAL ;
    PORT
      LAYER M4 ;
        RECT  86.316 34.128 86.4 34.152 ;
    END
  END r_data[230]
  PIN r_data[231]
    DIRECTION OUTPUT ;
    USE SIGNAL ;
    PORT
      LAYER M4 ;
        RECT  86.316 34.224 86.4 34.248 ;
    END
  END r_data[231]
  PIN r_data[232]
    DIRECTION OUTPUT ;
    USE SIGNAL ;
    PORT
      LAYER M4 ;
        RECT  86.316 34.32 86.4 34.344 ;
    END
  END r_data[232]
  PIN r_data[233]
    DIRECTION OUTPUT ;
    USE SIGNAL ;
    PORT
      LAYER M4 ;
        RECT  86.316 34.416 86.4 34.44 ;
    END
  END r_data[233]
  PIN r_data[234]
    DIRECTION OUTPUT ;
    USE SIGNAL ;
    PORT
      LAYER M4 ;
        RECT  86.316 34.512 86.4 34.536 ;
    END
  END r_data[234]
  PIN r_data[235]
    DIRECTION OUTPUT ;
    USE SIGNAL ;
    PORT
      LAYER M4 ;
        RECT  86.316 34.608 86.4 34.632 ;
    END
  END r_data[235]
  PIN r_data[236]
    DIRECTION OUTPUT ;
    USE SIGNAL ;
    PORT
      LAYER M4 ;
        RECT  86.316 34.704 86.4 34.728 ;
    END
  END r_data[236]
  PIN r_data[237]
    DIRECTION OUTPUT ;
    USE SIGNAL ;
    PORT
      LAYER M4 ;
        RECT  86.316 34.8 86.4 34.824 ;
    END
  END r_data[237]
  PIN r_data[238]
    DIRECTION OUTPUT ;
    USE SIGNAL ;
    PORT
      LAYER M4 ;
        RECT  86.316 34.896 86.4 34.92 ;
    END
  END r_data[238]
  PIN r_data[239]
    DIRECTION OUTPUT ;
    USE SIGNAL ;
    PORT
      LAYER M4 ;
        RECT  86.316 34.992 86.4 35.016 ;
    END
  END r_data[239]
  PIN r_data[23]
    DIRECTION OUTPUT ;
    USE SIGNAL ;
    PORT
      LAYER M4 ;
        RECT  86.316 54.96 86.4 54.984 ;
    END
  END r_data[23]
  PIN r_data[240]
    DIRECTION OUTPUT ;
    USE SIGNAL ;
    PORT
      LAYER M4 ;
        RECT  86.316 35.088 86.4 35.112 ;
    END
  END r_data[240]
  PIN r_data[241]
    DIRECTION OUTPUT ;
    USE SIGNAL ;
    PORT
      LAYER M4 ;
        RECT  86.316 35.184 86.4 35.208 ;
    END
  END r_data[241]
  PIN r_data[242]
    DIRECTION OUTPUT ;
    USE SIGNAL ;
    PORT
      LAYER M4 ;
        RECT  86.316 35.28 86.4 35.304 ;
    END
  END r_data[242]
  PIN r_data[243]
    DIRECTION OUTPUT ;
    USE SIGNAL ;
    PORT
      LAYER M4 ;
        RECT  86.316 35.376 86.4 35.4 ;
    END
  END r_data[243]
  PIN r_data[244]
    DIRECTION OUTPUT ;
    USE SIGNAL ;
    PORT
      LAYER M4 ;
        RECT  86.316 35.472 86.4 35.496 ;
    END
  END r_data[244]
  PIN r_data[245]
    DIRECTION OUTPUT ;
    USE SIGNAL ;
    PORT
      LAYER M4 ;
        RECT  86.316 35.568 86.4 35.592 ;
    END
  END r_data[245]
  PIN r_data[246]
    DIRECTION OUTPUT ;
    USE SIGNAL ;
    PORT
      LAYER M4 ;
        RECT  86.316 35.664 86.4 35.688 ;
    END
  END r_data[246]
  PIN r_data[247]
    DIRECTION OUTPUT ;
    USE SIGNAL ;
    PORT
      LAYER M4 ;
        RECT  86.316 35.76 86.4 35.784 ;
    END
  END r_data[247]
  PIN r_data[248]
    DIRECTION OUTPUT ;
    USE SIGNAL ;
    PORT
      LAYER M4 ;
        RECT  86.316 35.856 86.4 35.88 ;
    END
  END r_data[248]
  PIN r_data[249]
    DIRECTION OUTPUT ;
    USE SIGNAL ;
    PORT
      LAYER M4 ;
        RECT  86.316 35.952 86.4 35.976 ;
    END
  END r_data[249]
  PIN r_data[24]
    DIRECTION OUTPUT ;
    USE SIGNAL ;
    PORT
      LAYER M4 ;
        RECT  86.316 55.056 86.4 55.08 ;
    END
  END r_data[24]
  PIN r_data[250]
    DIRECTION OUTPUT ;
    USE SIGNAL ;
    PORT
      LAYER M4 ;
        RECT  86.316 36.048 86.4 36.072 ;
    END
  END r_data[250]
  PIN r_data[251]
    DIRECTION OUTPUT ;
    USE SIGNAL ;
    PORT
      LAYER M4 ;
        RECT  86.316 36.144 86.4 36.168 ;
    END
  END r_data[251]
  PIN r_data[252]
    DIRECTION OUTPUT ;
    USE SIGNAL ;
    PORT
      LAYER M4 ;
        RECT  86.316 36.24 86.4 36.264 ;
    END
  END r_data[252]
  PIN r_data[253]
    DIRECTION OUTPUT ;
    USE SIGNAL ;
    PORT
      LAYER M4 ;
        RECT  86.316 36.336 86.4 36.36 ;
    END
  END r_data[253]
  PIN r_data[254]
    DIRECTION OUTPUT ;
    USE SIGNAL ;
    PORT
      LAYER M4 ;
        RECT  86.316 36.432 86.4 36.456 ;
    END
  END r_data[254]
  PIN r_data[255]
    DIRECTION OUTPUT ;
    USE SIGNAL ;
    PORT
      LAYER M4 ;
        RECT  86.316 36.528 86.4 36.552 ;
    END
  END r_data[255]
  PIN r_data[25]
    DIRECTION OUTPUT ;
    USE SIGNAL ;
    PORT
      LAYER M4 ;
        RECT  86.316 55.152 86.4 55.176 ;
    END
  END r_data[25]
  PIN r_data[26]
    DIRECTION OUTPUT ;
    USE SIGNAL ;
    PORT
      LAYER M4 ;
        RECT  86.316 55.248 86.4 55.272 ;
    END
  END r_data[26]
  PIN r_data[27]
    DIRECTION OUTPUT ;
    USE SIGNAL ;
    PORT
      LAYER M4 ;
        RECT  86.316 55.344 86.4 55.368 ;
    END
  END r_data[27]
  PIN r_data[28]
    DIRECTION OUTPUT ;
    USE SIGNAL ;
    PORT
      LAYER M4 ;
        RECT  86.316 55.44 86.4 55.464 ;
    END
  END r_data[28]
  PIN r_data[29]
    DIRECTION OUTPUT ;
    USE SIGNAL ;
    PORT
      LAYER M4 ;
        RECT  86.316 55.536 86.4 55.56 ;
    END
  END r_data[29]
  PIN r_data[2]
    DIRECTION OUTPUT ;
    USE SIGNAL ;
    PORT
      LAYER M4 ;
        RECT  86.316 52.944 86.4 52.968 ;
    END
  END r_data[2]
  PIN r_data[30]
    DIRECTION OUTPUT ;
    USE SIGNAL ;
    PORT
      LAYER M4 ;
        RECT  86.316 55.632 86.4 55.656 ;
    END
  END r_data[30]
  PIN r_data[31]
    DIRECTION OUTPUT ;
    USE SIGNAL ;
    PORT
      LAYER M4 ;
        RECT  86.316 55.728 86.4 55.752 ;
    END
  END r_data[31]
  PIN r_data[32]
    DIRECTION OUTPUT ;
    USE SIGNAL ;
    PORT
      LAYER M4 ;
        RECT  86.316 43.536 86.4 43.56 ;
    END
  END r_data[32]
  PIN r_data[33]
    DIRECTION OUTPUT ;
    USE SIGNAL ;
    PORT
      LAYER M4 ;
        RECT  86.316 43.632 86.4 43.656 ;
    END
  END r_data[33]
  PIN r_data[34]
    DIRECTION OUTPUT ;
    USE SIGNAL ;
    PORT
      LAYER M4 ;
        RECT  86.316 43.728 86.4 43.752 ;
    END
  END r_data[34]
  PIN r_data[35]
    DIRECTION OUTPUT ;
    USE SIGNAL ;
    PORT
      LAYER M4 ;
        RECT  86.316 43.824 86.4 43.848 ;
    END
  END r_data[35]
  PIN r_data[36]
    DIRECTION OUTPUT ;
    USE SIGNAL ;
    PORT
      LAYER M4 ;
        RECT  86.316 43.92 86.4 43.944 ;
    END
  END r_data[36]
  PIN r_data[37]
    DIRECTION OUTPUT ;
    USE SIGNAL ;
    PORT
      LAYER M4 ;
        RECT  86.316 44.016 86.4 44.04 ;
    END
  END r_data[37]
  PIN r_data[38]
    DIRECTION OUTPUT ;
    USE SIGNAL ;
    PORT
      LAYER M4 ;
        RECT  86.316 44.112 86.4 44.136 ;
    END
  END r_data[38]
  PIN r_data[39]
    DIRECTION OUTPUT ;
    USE SIGNAL ;
    PORT
      LAYER M4 ;
        RECT  86.316 44.208 86.4 44.232 ;
    END
  END r_data[39]
  PIN r_data[3]
    DIRECTION OUTPUT ;
    USE SIGNAL ;
    PORT
      LAYER M4 ;
        RECT  86.316 53.04 86.4 53.064 ;
    END
  END r_data[3]
  PIN r_data[40]
    DIRECTION OUTPUT ;
    USE SIGNAL ;
    PORT
      LAYER M4 ;
        RECT  86.316 44.304 86.4 44.328 ;
    END
  END r_data[40]
  PIN r_data[41]
    DIRECTION OUTPUT ;
    USE SIGNAL ;
    PORT
      LAYER M4 ;
        RECT  86.316 44.4 86.4 44.424 ;
    END
  END r_data[41]
  PIN r_data[42]
    DIRECTION OUTPUT ;
    USE SIGNAL ;
    PORT
      LAYER M4 ;
        RECT  86.316 44.496 86.4 44.52 ;
    END
  END r_data[42]
  PIN r_data[43]
    DIRECTION OUTPUT ;
    USE SIGNAL ;
    PORT
      LAYER M4 ;
        RECT  86.316 44.592 86.4 44.616 ;
    END
  END r_data[43]
  PIN r_data[44]
    DIRECTION OUTPUT ;
    USE SIGNAL ;
    PORT
      LAYER M4 ;
        RECT  86.316 44.688 86.4 44.712 ;
    END
  END r_data[44]
  PIN r_data[45]
    DIRECTION OUTPUT ;
    USE SIGNAL ;
    PORT
      LAYER M4 ;
        RECT  86.316 44.784 86.4 44.808 ;
    END
  END r_data[45]
  PIN r_data[46]
    DIRECTION OUTPUT ;
    USE SIGNAL ;
    PORT
      LAYER M4 ;
        RECT  86.316 44.88 86.4 44.904 ;
    END
  END r_data[46]
  PIN r_data[47]
    DIRECTION OUTPUT ;
    USE SIGNAL ;
    PORT
      LAYER M4 ;
        RECT  86.316 44.976 86.4 45 ;
    END
  END r_data[47]
  PIN r_data[48]
    DIRECTION OUTPUT ;
    USE SIGNAL ;
    PORT
      LAYER M4 ;
        RECT  86.316 45.072 86.4 45.096 ;
    END
  END r_data[48]
  PIN r_data[49]
    DIRECTION OUTPUT ;
    USE SIGNAL ;
    PORT
      LAYER M4 ;
        RECT  86.316 45.168 86.4 45.192 ;
    END
  END r_data[49]
  PIN r_data[4]
    DIRECTION OUTPUT ;
    USE SIGNAL ;
    PORT
      LAYER M4 ;
        RECT  86.316 53.136 86.4 53.16 ;
    END
  END r_data[4]
  PIN r_data[50]
    DIRECTION OUTPUT ;
    USE SIGNAL ;
    PORT
      LAYER M4 ;
        RECT  86.316 45.264 86.4 45.288 ;
    END
  END r_data[50]
  PIN r_data[51]
    DIRECTION OUTPUT ;
    USE SIGNAL ;
    PORT
      LAYER M4 ;
        RECT  86.316 45.36 86.4 45.384 ;
    END
  END r_data[51]
  PIN r_data[52]
    DIRECTION OUTPUT ;
    USE SIGNAL ;
    PORT
      LAYER M4 ;
        RECT  86.316 45.456 86.4 45.48 ;
    END
  END r_data[52]
  PIN r_data[53]
    DIRECTION OUTPUT ;
    USE SIGNAL ;
    PORT
      LAYER M4 ;
        RECT  86.316 45.552 86.4 45.576 ;
    END
  END r_data[53]
  PIN r_data[54]
    DIRECTION OUTPUT ;
    USE SIGNAL ;
    PORT
      LAYER M4 ;
        RECT  86.316 45.648 86.4 45.672 ;
    END
  END r_data[54]
  PIN r_data[55]
    DIRECTION OUTPUT ;
    USE SIGNAL ;
    PORT
      LAYER M4 ;
        RECT  86.316 45.744 86.4 45.768 ;
    END
  END r_data[55]
  PIN r_data[56]
    DIRECTION OUTPUT ;
    USE SIGNAL ;
    PORT
      LAYER M4 ;
        RECT  86.316 45.84 86.4 45.864 ;
    END
  END r_data[56]
  PIN r_data[57]
    DIRECTION OUTPUT ;
    USE SIGNAL ;
    PORT
      LAYER M4 ;
        RECT  86.316 45.936 86.4 45.96 ;
    END
  END r_data[57]
  PIN r_data[58]
    DIRECTION OUTPUT ;
    USE SIGNAL ;
    PORT
      LAYER M4 ;
        RECT  86.316 46.032 86.4 46.056 ;
    END
  END r_data[58]
  PIN r_data[59]
    DIRECTION OUTPUT ;
    USE SIGNAL ;
    PORT
      LAYER M4 ;
        RECT  86.316 46.128 86.4 46.152 ;
    END
  END r_data[59]
  PIN r_data[5]
    DIRECTION OUTPUT ;
    USE SIGNAL ;
    PORT
      LAYER M4 ;
        RECT  86.316 53.232 86.4 53.256 ;
    END
  END r_data[5]
  PIN r_data[60]
    DIRECTION OUTPUT ;
    USE SIGNAL ;
    PORT
      LAYER M4 ;
        RECT  86.316 46.224 86.4 46.248 ;
    END
  END r_data[60]
  PIN r_data[61]
    DIRECTION OUTPUT ;
    USE SIGNAL ;
    PORT
      LAYER M4 ;
        RECT  86.316 46.32 86.4 46.344 ;
    END
  END r_data[61]
  PIN r_data[62]
    DIRECTION OUTPUT ;
    USE SIGNAL ;
    PORT
      LAYER M4 ;
        RECT  86.316 46.416 86.4 46.44 ;
    END
  END r_data[62]
  PIN r_data[63]
    DIRECTION OUTPUT ;
    USE SIGNAL ;
    PORT
      LAYER M4 ;
        RECT  86.316 46.512 86.4 46.536 ;
    END
  END r_data[63]
  PIN r_data[64]
    DIRECTION OUTPUT ;
    USE SIGNAL ;
    PORT
      LAYER M4 ;
        RECT  86.316 40.464 86.4 40.488 ;
    END
  END r_data[64]
  PIN r_data[65]
    DIRECTION OUTPUT ;
    USE SIGNAL ;
    PORT
      LAYER M4 ;
        RECT  86.316 40.56 86.4 40.584 ;
    END
  END r_data[65]
  PIN r_data[66]
    DIRECTION OUTPUT ;
    USE SIGNAL ;
    PORT
      LAYER M4 ;
        RECT  86.316 40.656 86.4 40.68 ;
    END
  END r_data[66]
  PIN r_data[67]
    DIRECTION OUTPUT ;
    USE SIGNAL ;
    PORT
      LAYER M4 ;
        RECT  86.316 40.752 86.4 40.776 ;
    END
  END r_data[67]
  PIN r_data[68]
    DIRECTION OUTPUT ;
    USE SIGNAL ;
    PORT
      LAYER M4 ;
        RECT  86.316 40.848 86.4 40.872 ;
    END
  END r_data[68]
  PIN r_data[69]
    DIRECTION OUTPUT ;
    USE SIGNAL ;
    PORT
      LAYER M4 ;
        RECT  86.316 40.944 86.4 40.968 ;
    END
  END r_data[69]
  PIN r_data[6]
    DIRECTION OUTPUT ;
    USE SIGNAL ;
    PORT
      LAYER M4 ;
        RECT  86.316 53.328 86.4 53.352 ;
    END
  END r_data[6]
  PIN r_data[70]
    DIRECTION OUTPUT ;
    USE SIGNAL ;
    PORT
      LAYER M4 ;
        RECT  86.316 41.04 86.4 41.064 ;
    END
  END r_data[70]
  PIN r_data[71]
    DIRECTION OUTPUT ;
    USE SIGNAL ;
    PORT
      LAYER M4 ;
        RECT  86.316 41.136 86.4 41.16 ;
    END
  END r_data[71]
  PIN r_data[72]
    DIRECTION OUTPUT ;
    USE SIGNAL ;
    PORT
      LAYER M4 ;
        RECT  86.316 41.232 86.4 41.256 ;
    END
  END r_data[72]
  PIN r_data[73]
    DIRECTION OUTPUT ;
    USE SIGNAL ;
    PORT
      LAYER M4 ;
        RECT  86.316 41.328 86.4 41.352 ;
    END
  END r_data[73]
  PIN r_data[74]
    DIRECTION OUTPUT ;
    USE SIGNAL ;
    PORT
      LAYER M4 ;
        RECT  86.316 41.424 86.4 41.448 ;
    END
  END r_data[74]
  PIN r_data[75]
    DIRECTION OUTPUT ;
    USE SIGNAL ;
    PORT
      LAYER M4 ;
        RECT  86.316 41.52 86.4 41.544 ;
    END
  END r_data[75]
  PIN r_data[76]
    DIRECTION OUTPUT ;
    USE SIGNAL ;
    PORT
      LAYER M4 ;
        RECT  86.316 41.616 86.4 41.64 ;
    END
  END r_data[76]
  PIN r_data[77]
    DIRECTION OUTPUT ;
    USE SIGNAL ;
    PORT
      LAYER M4 ;
        RECT  86.316 41.712 86.4 41.736 ;
    END
  END r_data[77]
  PIN r_data[78]
    DIRECTION OUTPUT ;
    USE SIGNAL ;
    PORT
      LAYER M4 ;
        RECT  86.316 41.808 86.4 41.832 ;
    END
  END r_data[78]
  PIN r_data[79]
    DIRECTION OUTPUT ;
    USE SIGNAL ;
    PORT
      LAYER M4 ;
        RECT  86.316 41.904 86.4 41.928 ;
    END
  END r_data[79]
  PIN r_data[7]
    DIRECTION OUTPUT ;
    USE SIGNAL ;
    PORT
      LAYER M4 ;
        RECT  86.316 53.424 86.4 53.448 ;
    END
  END r_data[7]
  PIN r_data[80]
    DIRECTION OUTPUT ;
    USE SIGNAL ;
    PORT
      LAYER M4 ;
        RECT  86.316 42 86.4 42.024 ;
    END
  END r_data[80]
  PIN r_data[81]
    DIRECTION OUTPUT ;
    USE SIGNAL ;
    PORT
      LAYER M4 ;
        RECT  86.316 42.096 86.4 42.12 ;
    END
  END r_data[81]
  PIN r_data[82]
    DIRECTION OUTPUT ;
    USE SIGNAL ;
    PORT
      LAYER M4 ;
        RECT  86.316 42.192 86.4 42.216 ;
    END
  END r_data[82]
  PIN r_data[83]
    DIRECTION OUTPUT ;
    USE SIGNAL ;
    PORT
      LAYER M4 ;
        RECT  86.316 42.288 86.4 42.312 ;
    END
  END r_data[83]
  PIN r_data[84]
    DIRECTION OUTPUT ;
    USE SIGNAL ;
    PORT
      LAYER M4 ;
        RECT  86.316 42.384 86.4 42.408 ;
    END
  END r_data[84]
  PIN r_data[85]
    DIRECTION OUTPUT ;
    USE SIGNAL ;
    PORT
      LAYER M4 ;
        RECT  86.316 42.48 86.4 42.504 ;
    END
  END r_data[85]
  PIN r_data[86]
    DIRECTION OUTPUT ;
    USE SIGNAL ;
    PORT
      LAYER M4 ;
        RECT  86.316 42.576 86.4 42.6 ;
    END
  END r_data[86]
  PIN r_data[87]
    DIRECTION OUTPUT ;
    USE SIGNAL ;
    PORT
      LAYER M4 ;
        RECT  86.316 42.672 86.4 42.696 ;
    END
  END r_data[87]
  PIN r_data[88]
    DIRECTION OUTPUT ;
    USE SIGNAL ;
    PORT
      LAYER M4 ;
        RECT  86.316 42.768 86.4 42.792 ;
    END
  END r_data[88]
  PIN r_data[89]
    DIRECTION OUTPUT ;
    USE SIGNAL ;
    PORT
      LAYER M4 ;
        RECT  86.316 42.864 86.4 42.888 ;
    END
  END r_data[89]
  PIN r_data[8]
    DIRECTION OUTPUT ;
    USE SIGNAL ;
    PORT
      LAYER M4 ;
        RECT  86.316 53.52 86.4 53.544 ;
    END
  END r_data[8]
  PIN r_data[90]
    DIRECTION OUTPUT ;
    USE SIGNAL ;
    PORT
      LAYER M4 ;
        RECT  86.316 42.96 86.4 42.984 ;
    END
  END r_data[90]
  PIN r_data[91]
    DIRECTION OUTPUT ;
    USE SIGNAL ;
    PORT
      LAYER M4 ;
        RECT  86.316 43.056 86.4 43.08 ;
    END
  END r_data[91]
  PIN r_data[92]
    DIRECTION OUTPUT ;
    USE SIGNAL ;
    PORT
      LAYER M4 ;
        RECT  86.316 43.152 86.4 43.176 ;
    END
  END r_data[92]
  PIN r_data[93]
    DIRECTION OUTPUT ;
    USE SIGNAL ;
    PORT
      LAYER M4 ;
        RECT  86.316 43.248 86.4 43.272 ;
    END
  END r_data[93]
  PIN r_data[94]
    DIRECTION OUTPUT ;
    USE SIGNAL ;
    PORT
      LAYER M4 ;
        RECT  86.316 43.344 86.4 43.368 ;
    END
  END r_data[94]
  PIN r_data[95]
    DIRECTION OUTPUT ;
    USE SIGNAL ;
    PORT
      LAYER M4 ;
        RECT  86.316 43.44 86.4 43.464 ;
    END
  END r_data[95]
  PIN r_data[96]
    DIRECTION OUTPUT ;
    USE SIGNAL ;
    PORT
      LAYER M4 ;
        RECT  86.316 49.68 86.4 49.704 ;
    END
  END r_data[96]
  PIN r_data[97]
    DIRECTION OUTPUT ;
    USE SIGNAL ;
    PORT
      LAYER M4 ;
        RECT  86.316 49.776 86.4 49.8 ;
    END
  END r_data[97]
  PIN r_data[98]
    DIRECTION OUTPUT ;
    USE SIGNAL ;
    PORT
      LAYER M4 ;
        RECT  86.316 49.872 86.4 49.896 ;
    END
  END r_data[98]
  PIN r_data[99]
    DIRECTION OUTPUT ;
    USE SIGNAL ;
    PORT
      LAYER M4 ;
        RECT  86.316 49.968 86.4 49.992 ;
    END
  END r_data[99]
  PIN r_data[9]
    DIRECTION OUTPUT ;
    USE SIGNAL ;
    PORT
      LAYER M4 ;
        RECT  86.316 53.616 86.4 53.64 ;
    END
  END r_data[9]
  PIN r_len[0]
    DIRECTION OUTPUT ;
    USE SIGNAL ;
    PORT
      LAYER M4 ;
        RECT  86.316 80.496 86.4 80.52 ;
    END
  END r_len[0]
  PIN r_len[10]
    DIRECTION OUTPUT ;
    USE SIGNAL ;
    PORT
      LAYER M4 ;
        RECT  86.316 81.456 86.4 81.48 ;
    END
  END r_len[10]
  PIN r_len[11]
    DIRECTION OUTPUT ;
    USE SIGNAL ;
    PORT
      LAYER M4 ;
        RECT  86.316 81.552 86.4 81.576 ;
    END
  END r_len[11]
  PIN r_len[12]
    DIRECTION OUTPUT ;
    USE SIGNAL ;
    PORT
      LAYER M4 ;
        RECT  86.316 81.648 86.4 81.672 ;
    END
  END r_len[12]
  PIN r_len[13]
    DIRECTION OUTPUT ;
    USE SIGNAL ;
    PORT
      LAYER M4 ;
        RECT  86.316 81.744 86.4 81.768 ;
    END
  END r_len[13]
  PIN r_len[14]
    DIRECTION OUTPUT ;
    USE SIGNAL ;
    PORT
      LAYER M4 ;
        RECT  86.316 81.84 86.4 81.864 ;
    END
  END r_len[14]
  PIN r_len[15]
    DIRECTION OUTPUT ;
    USE SIGNAL ;
    PORT
      LAYER M4 ;
        RECT  86.316 81.936 86.4 81.96 ;
    END
  END r_len[15]
  PIN r_len[1]
    DIRECTION OUTPUT ;
    USE SIGNAL ;
    PORT
      LAYER M4 ;
        RECT  86.316 80.592 86.4 80.616 ;
    END
  END r_len[1]
  PIN r_len[2]
    DIRECTION OUTPUT ;
    USE SIGNAL ;
    PORT
      LAYER M4 ;
        RECT  86.316 80.688 86.4 80.712 ;
    END
  END r_len[2]
  PIN r_len[3]
    DIRECTION OUTPUT ;
    USE SIGNAL ;
    PORT
      LAYER M4 ;
        RECT  86.316 80.784 86.4 80.808 ;
    END
  END r_len[3]
  PIN r_len[4]
    DIRECTION OUTPUT ;
    USE SIGNAL ;
    PORT
      LAYER M4 ;
        RECT  86.316 80.88 86.4 80.904 ;
    END
  END r_len[4]
  PIN r_len[5]
    DIRECTION OUTPUT ;
    USE SIGNAL ;
    PORT
      LAYER M4 ;
        RECT  86.316 80.976 86.4 81 ;
    END
  END r_len[5]
  PIN r_len[6]
    DIRECTION OUTPUT ;
    USE SIGNAL ;
    PORT
      LAYER M4 ;
        RECT  86.316 81.072 86.4 81.096 ;
    END
  END r_len[6]
  PIN r_len[7]
    DIRECTION OUTPUT ;
    USE SIGNAL ;
    PORT
      LAYER M4 ;
        RECT  86.316 81.168 86.4 81.192 ;
    END
  END r_len[7]
  PIN r_len[8]
    DIRECTION OUTPUT ;
    USE SIGNAL ;
    PORT
      LAYER M4 ;
        RECT  86.316 81.264 86.4 81.288 ;
    END
  END r_len[8]
  PIN r_len[9]
    DIRECTION OUTPUT ;
    USE SIGNAL ;
    PORT
      LAYER M4 ;
        RECT  86.316 81.36 86.4 81.384 ;
    END
  END r_len[9]
  PIN r_row[0]
    DIRECTION OUTPUT ;
    USE SIGNAL ;
    PORT
      LAYER M4 ;
        RECT  86.316 75.504 86.4 75.528 ;
    END
  END r_row[0]
  PIN r_row[1]
    DIRECTION OUTPUT ;
    USE SIGNAL ;
    PORT
      LAYER M4 ;
        RECT  86.316 75.6 86.4 75.624 ;
    END
  END r_row[1]
  PIN r_row[2]
    DIRECTION OUTPUT ;
    USE SIGNAL ;
    PORT
      LAYER M4 ;
        RECT  86.316 75.696 86.4 75.72 ;
    END
  END r_row[2]
  PIN r_row[3]
    DIRECTION OUTPUT ;
    USE SIGNAL ;
    PORT
      LAYER M4 ;
        RECT  86.316 75.792 86.4 75.816 ;
    END
  END r_row[3]
  PIN r_row[4]
    DIRECTION OUTPUT ;
    USE SIGNAL ;
    PORT
      LAYER M4 ;
        RECT  86.316 75.888 86.4 75.912 ;
    END
  END r_row[4]
  PIN r_row[5]
    DIRECTION OUTPUT ;
    USE SIGNAL ;
    PORT
      LAYER M4 ;
        RECT  86.316 75.984 86.4 76.008 ;
    END
  END r_row[5]
  PIN r_row[6]
    DIRECTION OUTPUT ;
    USE SIGNAL ;
    PORT
      LAYER M4 ;
        RECT  86.316 76.08 86.4 76.104 ;
    END
  END r_row[6]
  PIN r_start
    DIRECTION OUTPUT ;
    USE SIGNAL ;
    PORT
      LAYER M4 ;
        RECT  86.316 79.536 86.4 79.56 ;
    END
  END r_start
  PIN r_we[0]
    DIRECTION OUTPUT ;
    USE SIGNAL ;
    PORT
      LAYER M4 ;
        RECT  86.316 78 86.4 78.024 ;
    END
  END r_we[0]
  PIN r_we[1]
    DIRECTION OUTPUT ;
    USE SIGNAL ;
    PORT
      LAYER M4 ;
        RECT  86.316 78.096 86.4 78.12 ;
    END
  END r_we[1]
  PIN r_we[2]
    DIRECTION OUTPUT ;
    USE SIGNAL ;
    PORT
      LAYER M4 ;
        RECT  86.316 78.192 86.4 78.216 ;
    END
  END r_we[2]
  PIN r_we[3]
    DIRECTION OUTPUT ;
    USE SIGNAL ;
    PORT
      LAYER M4 ;
        RECT  86.316 78.288 86.4 78.312 ;
    END
  END r_we[3]
  PIN rst_n
    DIRECTION INPUT ;
    USE SIGNAL ;
    PORT
      LAYER M4 ;
        RECT  0 74.064 0.084 74.088 ;
    END
  END rst_n
  PIN start
    DIRECTION INPUT ;
    USE SIGNAL ;
    PORT
      LAYER M4 ;
        RECT  0 75.504 0.084 75.528 ;
    END
  END start
  PIN VDD
    DIRECTION INOUT ;
    USE POWER ;
    PORT
      LAYER M5 ;
        RECT  83.592 2.151 83.712 84.249 ;
        RECT  78.192 2.151 78.312 84.249 ;
        RECT  72.792 2.151 72.912 84.249 ;
        RECT  67.392 2.151 67.512 84.249 ;
        RECT  61.992 2.151 62.112 84.249 ;
        RECT  56.592 2.151 56.712 84.249 ;
        RECT  51.192 2.151 51.312 84.249 ;
        RECT  45.792 2.151 45.912 84.249 ;
        RECT  40.392 2.151 40.512 84.249 ;
        RECT  34.992 2.151 35.112 84.249 ;
        RECT  29.592 2.151 29.712 84.249 ;
        RECT  24.192 2.151 24.312 84.249 ;
        RECT  18.792 2.151 18.912 84.249 ;
        RECT  13.392 2.151 13.512 84.249 ;
        RECT  7.992 2.151 8.112 84.249 ;
        RECT  2.592 2.151 2.712 84.249 ;
    END
  END VDD
  PIN VSS
    DIRECTION INOUT ;
    USE GROUND ;
    PORT
      LAYER M5 ;
        RECT  83.4 2.137 83.52 84.263 ;
        RECT  78 2.137 78.12 84.263 ;
        RECT  72.6 2.137 72.72 84.263 ;
        RECT  67.2 2.137 67.32 84.263 ;
        RECT  61.8 2.137 61.92 84.263 ;
        RECT  56.4 2.137 56.52 84.263 ;
        RECT  51 2.137 51.12 84.263 ;
        RECT  45.6 2.137 45.72 84.263 ;
        RECT  40.2 2.137 40.32 84.263 ;
        RECT  34.8 2.137 34.92 84.263 ;
        RECT  29.4 2.137 29.52 84.263 ;
        RECT  24 2.137 24.12 84.263 ;
        RECT  18.6 2.137 18.72 84.263 ;
        RECT  13.2 2.137 13.32 84.263 ;
        RECT  7.8 2.137 7.92 84.263 ;
        RECT  2.4 2.137 2.52 84.263 ;
    END
  END VSS
  OBS
    LAYER RVTN ;
     RECT  2.16 2.16 84.24 2.295 ;
     RECT  2.16 2.565 84.24 2.835 ;
     RECT  2.16 3.105 84.24 3.375 ;
     RECT  2.16 3.645 84.24 3.915 ;
     RECT  2.16 4.185 84.24 4.455 ;
     RECT  2.16 4.725 84.24 4.995 ;
     RECT  2.16 5.265 84.24 5.535 ;
     RECT  2.16 5.805 84.24 6.075 ;
     RECT  2.16 6.345 84.24 6.615 ;
     RECT  2.16 6.885 84.24 7.155 ;
     RECT  2.16 7.425 84.24 7.695 ;
     RECT  2.16 7.965 84.24 8.235 ;
     RECT  2.16 8.505 84.24 8.775 ;
     RECT  2.16 9.045 84.24 9.315 ;
     RECT  2.16 9.585 84.24 9.855 ;
     RECT  2.16 10.125 84.24 10.395 ;
     RECT  2.16 10.665 84.24 10.935 ;
     RECT  2.16 11.205 84.24 11.475 ;
     RECT  2.16 11.745 84.24 12.015 ;
     RECT  2.16 12.285 84.24 12.555 ;
     RECT  2.16 12.825 84.24 13.095 ;
     RECT  2.16 13.365 84.24 13.635 ;
     RECT  2.16 13.905 84.24 14.175 ;
     RECT  2.16 14.445 84.24 14.715 ;
     RECT  2.16 14.985 84.24 15.255 ;
     RECT  2.16 15.525 84.24 15.795 ;
     RECT  2.16 16.065 84.24 16.335 ;
     RECT  2.16 16.605 84.24 16.875 ;
     RECT  2.16 17.145 84.24 17.415 ;
     RECT  2.16 17.685 84.24 17.955 ;
     RECT  2.16 18.225 84.24 18.495 ;
     RECT  2.16 18.765 84.24 19.035 ;
     RECT  2.16 19.305 84.24 19.575 ;
     RECT  2.16 19.845 84.24 20.115 ;
     RECT  2.16 20.385 84.24 20.655 ;
     RECT  2.16 20.925 84.24 21.195 ;
     RECT  2.16 21.465 84.24 21.735 ;
     RECT  2.16 22.005 84.24 22.275 ;
     RECT  2.16 22.545 84.24 22.815 ;
     RECT  2.16 23.085 84.24 23.355 ;
     RECT  2.16 23.625 84.24 23.895 ;
     RECT  2.16 24.165 84.24 24.435 ;
     RECT  2.16 24.705 84.24 24.975 ;
     RECT  2.16 25.245 84.24 25.515 ;
     RECT  2.16 25.785 84.24 26.055 ;
     RECT  2.16 26.325 84.24 26.595 ;
     RECT  2.16 26.865 84.24 27.135 ;
     RECT  2.16 27.405 84.24 27.675 ;
     RECT  2.16 27.945 84.24 28.215 ;
     RECT  2.16 28.485 84.24 28.755 ;
     RECT  2.16 29.025 84.24 29.295 ;
     RECT  2.16 29.565 84.24 29.835 ;
     RECT  2.16 30.105 84.24 30.375 ;
     RECT  2.16 30.645 84.24 30.915 ;
     RECT  2.16 31.185 84.24 31.455 ;
     RECT  2.16 31.725 84.24 31.995 ;
     RECT  2.16 32.265 84.24 32.535 ;
     RECT  2.16 32.805 84.24 33.075 ;
     RECT  2.16 33.345 84.24 33.615 ;
     RECT  2.16 33.885 84.24 34.155 ;
     RECT  2.16 34.425 84.24 34.695 ;
     RECT  2.16 34.965 84.24 35.235 ;
     RECT  2.16 35.505 84.24 35.775 ;
     RECT  2.16 36.045 84.24 36.315 ;
     RECT  2.16 36.585 84.24 36.855 ;
     RECT  2.16 37.125 84.24 37.395 ;
     RECT  2.16 37.665 84.24 37.935 ;
     RECT  2.16 38.205 84.24 38.475 ;
     RECT  2.16 38.745 84.24 39.015 ;
     RECT  2.16 39.285 84.24 39.555 ;
     RECT  2.16 39.825 84.24 40.095 ;
     RECT  2.16 40.365 84.24 40.635 ;
     RECT  2.16 40.905 84.24 41.175 ;
     RECT  2.16 41.445 84.24 41.715 ;
     RECT  2.16 41.985 84.24 42.255 ;
     RECT  2.16 42.525 84.24 42.795 ;
     RECT  2.16 43.065 84.24 43.335 ;
     RECT  2.16 43.605 84.24 43.875 ;
     RECT  2.16 44.145 84.24 44.415 ;
     RECT  2.16 44.685 84.24 44.955 ;
     RECT  2.16 45.225 84.24 45.495 ;
     RECT  2.16 45.765 84.24 46.035 ;
     RECT  2.16 46.305 84.24 46.575 ;
     RECT  2.16 46.845 84.24 47.115 ;
     RECT  2.16 47.385 84.24 47.655 ;
     RECT  2.16 47.925 84.24 48.195 ;
     RECT  2.16 48.465 84.24 48.735 ;
     RECT  2.16 49.005 84.24 49.275 ;
     RECT  2.16 49.545 84.24 49.815 ;
     RECT  2.16 50.085 84.24 50.355 ;
     RECT  2.16 50.625 84.24 50.895 ;
     RECT  2.16 51.165 84.24 51.435 ;
     RECT  2.16 51.705 84.24 51.975 ;
     RECT  2.16 52.245 84.24 52.515 ;
     RECT  2.16 52.785 84.24 53.055 ;
     RECT  2.16 53.325 84.24 53.595 ;
     RECT  2.16 53.865 84.24 54.135 ;
     RECT  2.16 54.405 84.24 54.675 ;
     RECT  2.16 54.945 84.24 55.215 ;
     RECT  2.16 55.485 84.24 55.755 ;
     RECT  2.16 56.025 84.24 56.295 ;
     RECT  2.16 56.565 84.24 56.835 ;
     RECT  2.16 57.105 84.24 57.375 ;
     RECT  2.16 57.645 84.24 57.915 ;
     RECT  2.16 58.185 84.24 58.455 ;
     RECT  2.16 58.725 84.24 58.995 ;
     RECT  2.16 59.265 84.24 59.535 ;
     RECT  2.16 59.805 84.24 60.075 ;
     RECT  2.16 60.345 84.24 60.615 ;
     RECT  2.16 60.885 84.24 61.155 ;
     RECT  2.16 61.425 84.24 61.695 ;
     RECT  2.16 61.965 84.24 62.235 ;
     RECT  2.16 62.505 84.24 62.775 ;
     RECT  2.16 63.045 84.24 63.315 ;
     RECT  2.16 63.585 84.24 63.855 ;
     RECT  2.16 64.125 84.24 64.395 ;
     RECT  2.16 64.665 84.24 64.935 ;
     RECT  2.16 65.205 84.24 65.475 ;
     RECT  2.16 65.745 84.24 66.015 ;
     RECT  2.16 66.285 84.24 66.555 ;
     RECT  2.16 66.825 84.24 67.095 ;
     RECT  2.16 67.365 84.24 67.635 ;
     RECT  2.16 67.905 84.24 68.175 ;
     RECT  2.16 68.445 84.24 68.715 ;
     RECT  2.16 68.985 84.24 69.255 ;
     RECT  2.16 69.525 84.24 69.795 ;
     RECT  2.16 70.065 84.24 70.335 ;
     RECT  2.16 70.605 84.24 70.875 ;
     RECT  2.16 71.145 84.24 71.415 ;
     RECT  2.16 71.685 84.24 71.955 ;
     RECT  2.16 72.225 84.24 72.495 ;
     RECT  2.16 72.765 84.24 73.035 ;
     RECT  2.16 73.305 84.24 73.575 ;
     RECT  2.16 73.845 84.24 74.115 ;
     RECT  2.16 74.385 84.24 74.655 ;
     RECT  2.16 74.925 84.24 75.195 ;
     RECT  2.16 75.465 84.24 75.735 ;
     RECT  2.16 76.005 84.24 76.275 ;
     RECT  2.16 76.545 84.24 76.815 ;
     RECT  2.16 77.085 84.24 77.355 ;
     RECT  2.16 77.625 84.24 77.895 ;
     RECT  2.16 78.165 84.24 78.435 ;
     RECT  2.16 78.705 84.24 78.975 ;
     RECT  2.16 79.245 84.24 79.515 ;
     RECT  2.16 79.785 84.24 80.055 ;
     RECT  2.16 80.325 84.24 80.595 ;
     RECT  2.16 80.865 84.24 81.135 ;
     RECT  2.16 81.405 84.24 81.675 ;
     RECT  2.16 81.945 84.24 82.215 ;
     RECT  2.16 82.485 84.24 82.755 ;
     RECT  2.16 83.025 84.24 83.295 ;
     RECT  2.16 83.565 84.24 83.835 ;
     RECT  2.16 84.105 84.24 84.24 ;
    LAYER RVTP ;
     RECT  2.16 2.295 84.24 2.565 ;
     RECT  2.16 2.835 84.24 3.105 ;
     RECT  2.16 3.375 84.24 3.645 ;
     RECT  2.16 3.915 84.24 4.185 ;
     RECT  2.16 4.455 84.24 4.725 ;
     RECT  2.16 4.995 84.24 5.265 ;
     RECT  2.16 5.535 84.24 5.805 ;
     RECT  2.16 6.075 84.24 6.345 ;
     RECT  2.16 6.615 84.24 6.885 ;
     RECT  2.16 7.155 84.24 7.425 ;
     RECT  2.16 7.695 84.24 7.965 ;
     RECT  2.16 8.235 84.24 8.505 ;
     RECT  2.16 8.775 84.24 9.045 ;
     RECT  2.16 9.315 84.24 9.585 ;
     RECT  2.16 9.855 84.24 10.125 ;
     RECT  2.16 10.395 84.24 10.665 ;
     RECT  2.16 10.935 84.24 11.205 ;
     RECT  2.16 11.475 84.24 11.745 ;
     RECT  2.16 12.015 84.24 12.285 ;
     RECT  2.16 12.555 84.24 12.825 ;
     RECT  2.16 13.095 84.24 13.365 ;
     RECT  2.16 13.635 84.24 13.905 ;
     RECT  2.16 14.175 84.24 14.445 ;
     RECT  2.16 14.715 84.24 14.985 ;
     RECT  2.16 15.255 84.24 15.525 ;
     RECT  2.16 15.795 84.24 16.065 ;
     RECT  2.16 16.335 84.24 16.605 ;
     RECT  2.16 16.875 84.24 17.145 ;
     RECT  2.16 17.415 84.24 17.685 ;
     RECT  2.16 17.955 84.24 18.225 ;
     RECT  2.16 18.495 84.24 18.765 ;
     RECT  2.16 19.035 84.24 19.305 ;
     RECT  2.16 19.575 84.24 19.845 ;
     RECT  2.16 20.115 84.24 20.385 ;
     RECT  2.16 20.655 84.24 20.925 ;
     RECT  2.16 21.195 84.24 21.465 ;
     RECT  2.16 21.735 84.24 22.005 ;
     RECT  2.16 22.275 84.24 22.545 ;
     RECT  2.16 22.815 84.24 23.085 ;
     RECT  2.16 23.355 84.24 23.625 ;
     RECT  2.16 23.895 84.24 24.165 ;
     RECT  2.16 24.435 84.24 24.705 ;
     RECT  2.16 24.975 84.24 25.245 ;
     RECT  2.16 25.515 84.24 25.785 ;
     RECT  2.16 26.055 84.24 26.325 ;
     RECT  2.16 26.595 84.24 26.865 ;
     RECT  2.16 27.135 84.24 27.405 ;
     RECT  2.16 27.675 84.24 27.945 ;
     RECT  2.16 28.215 84.24 28.485 ;
     RECT  2.16 28.755 84.24 29.025 ;
     RECT  2.16 29.295 84.24 29.565 ;
     RECT  2.16 29.835 84.24 30.105 ;
     RECT  2.16 30.375 84.24 30.645 ;
     RECT  2.16 30.915 84.24 31.185 ;
     RECT  2.16 31.455 84.24 31.725 ;
     RECT  2.16 31.995 84.24 32.265 ;
     RECT  2.16 32.535 84.24 32.805 ;
     RECT  2.16 33.075 84.24 33.345 ;
     RECT  2.16 33.615 84.24 33.885 ;
     RECT  2.16 34.155 84.24 34.425 ;
     RECT  2.16 34.695 84.24 34.965 ;
     RECT  2.16 35.235 84.24 35.505 ;
     RECT  2.16 35.775 84.24 36.045 ;
     RECT  2.16 36.315 84.24 36.585 ;
     RECT  2.16 36.855 84.24 37.125 ;
     RECT  2.16 37.395 84.24 37.665 ;
     RECT  2.16 37.935 84.24 38.205 ;
     RECT  2.16 38.475 84.24 38.745 ;
     RECT  2.16 39.015 84.24 39.285 ;
     RECT  2.16 39.555 84.24 39.825 ;
     RECT  2.16 40.095 84.24 40.365 ;
     RECT  2.16 40.635 84.24 40.905 ;
     RECT  2.16 41.175 84.24 41.445 ;
     RECT  2.16 41.715 84.24 41.985 ;
     RECT  2.16 42.255 84.24 42.525 ;
     RECT  2.16 42.795 84.24 43.065 ;
     RECT  2.16 43.335 84.24 43.605 ;
     RECT  2.16 43.875 84.24 44.145 ;
     RECT  2.16 44.415 84.24 44.685 ;
     RECT  2.16 44.955 84.24 45.225 ;
     RECT  2.16 45.495 84.24 45.765 ;
     RECT  2.16 46.035 84.24 46.305 ;
     RECT  2.16 46.575 84.24 46.845 ;
     RECT  2.16 47.115 84.24 47.385 ;
     RECT  2.16 47.655 84.24 47.925 ;
     RECT  2.16 48.195 84.24 48.465 ;
     RECT  2.16 48.735 84.24 49.005 ;
     RECT  2.16 49.275 84.24 49.545 ;
     RECT  2.16 49.815 84.24 50.085 ;
     RECT  2.16 50.355 84.24 50.625 ;
     RECT  2.16 50.895 84.24 51.165 ;
     RECT  2.16 51.435 84.24 51.705 ;
     RECT  2.16 51.975 84.24 52.245 ;
     RECT  2.16 52.515 84.24 52.785 ;
     RECT  2.16 53.055 84.24 53.325 ;
     RECT  2.16 53.595 84.24 53.865 ;
     RECT  2.16 54.135 84.24 54.405 ;
     RECT  2.16 54.675 84.24 54.945 ;
     RECT  2.16 55.215 84.24 55.485 ;
     RECT  2.16 55.755 84.24 56.025 ;
     RECT  2.16 56.295 84.24 56.565 ;
     RECT  2.16 56.835 84.24 57.105 ;
     RECT  2.16 57.375 84.24 57.645 ;
     RECT  2.16 57.915 84.24 58.185 ;
     RECT  2.16 58.455 84.24 58.725 ;
     RECT  2.16 58.995 84.24 59.265 ;
     RECT  2.16 59.535 84.24 59.805 ;
     RECT  2.16 60.075 84.24 60.345 ;
     RECT  2.16 60.615 84.24 60.885 ;
     RECT  2.16 61.155 84.24 61.425 ;
     RECT  2.16 61.695 84.24 61.965 ;
     RECT  2.16 62.235 84.24 62.505 ;
     RECT  2.16 62.775 84.24 63.045 ;
     RECT  2.16 63.315 84.24 63.585 ;
     RECT  2.16 63.855 84.24 64.125 ;
     RECT  2.16 64.395 84.24 64.665 ;
     RECT  2.16 64.935 84.24 65.205 ;
     RECT  2.16 65.475 84.24 65.745 ;
     RECT  2.16 66.015 84.24 66.285 ;
     RECT  2.16 66.555 84.24 66.825 ;
     RECT  2.16 67.095 84.24 67.365 ;
     RECT  2.16 67.635 84.24 67.905 ;
     RECT  2.16 68.175 84.24 68.445 ;
     RECT  2.16 68.715 84.24 68.985 ;
     RECT  2.16 69.255 84.24 69.525 ;
     RECT  2.16 69.795 84.24 70.065 ;
     RECT  2.16 70.335 84.24 70.605 ;
     RECT  2.16 70.875 84.24 71.145 ;
     RECT  2.16 71.415 84.24 71.685 ;
     RECT  2.16 71.955 84.24 72.225 ;
     RECT  2.16 72.495 84.24 72.765 ;
     RECT  2.16 73.035 84.24 73.305 ;
     RECT  2.16 73.575 84.24 73.845 ;
     RECT  2.16 74.115 84.24 74.385 ;
     RECT  2.16 74.655 84.24 74.925 ;
     RECT  2.16 75.195 84.24 75.465 ;
     RECT  2.16 75.735 84.24 76.005 ;
     RECT  2.16 76.275 84.24 76.545 ;
     RECT  2.16 76.815 84.24 77.085 ;
     RECT  2.16 77.355 84.24 77.625 ;
     RECT  2.16 77.895 84.24 78.165 ;
     RECT  2.16 78.435 84.24 78.705 ;
     RECT  2.16 78.975 84.24 79.245 ;
     RECT  2.16 79.515 84.24 79.785 ;
     RECT  2.16 80.055 84.24 80.325 ;
     RECT  2.16 80.595 84.24 80.865 ;
     RECT  2.16 81.135 84.24 81.405 ;
     RECT  2.16 81.675 84.24 81.945 ;
     RECT  2.16 82.215 84.24 82.485 ;
     RECT  2.16 82.755 84.24 83.025 ;
     RECT  2.16 83.295 84.24 83.565 ;
     RECT  2.16 83.835 84.24 84.105 ;
    LAYER M1 ;
     RECT  2.16 2.151 84.24 84.249 ;
    LAYER M2 ;
     RECT  0.103 47.511 0.139 47.529 ;
     RECT  0.103 77.562 0.139 77.58 ;
     RECT  0.103 78.372 0.139 78.39 ;
     RECT  0.103 79.182 0.175 79.2 ;
     RECT  0.103 33.93 0.203 33.948 ;
     RECT  0.103 40.95 0.203 41.589 ;
     RECT  0.103 44.811 0.203 44.829 ;
     RECT  0.139 47.466 0.203 47.529 ;
     RECT  0.103 50.364 0.203 50.382 ;
     RECT  0.103 51.21 0.203 51.228 ;
     RECT  0.103 56.646 0.203 56.664 ;
     RECT  0.139 77.562 0.211 78.39 ;
     RECT  0.175 79.182 0.211 79.704 ;
     RECT  0.139 54.756 0.239 54.774 ;
     RECT  0.211 77.562 0.247 79.704 ;
     RECT  0.175 49.086 0.275 49.104 ;
     RECT  0.103 39.834 0.463 40.086 ;
     RECT  0.203 40.95 0.463 40.968 ;
     RECT  0.463 32.814 0.499 33.066 ;
     RECT  0.499 32.616 0.535 33.066 ;
     RECT  0.463 39.834 0.535 40.968 ;
     RECT  0.103 52.992 0.535 53.01 ;
     RECT  0.103 60.696 0.535 60.714 ;
     RECT  0.031 68.382 0.535 68.4 ;
     RECT  0.535 32.472 0.563 33.066 ;
     RECT  0.563 32.472 0.635 32.994 ;
     RECT  0.535 43.812 0.643 43.83 ;
     RECT  0.643 43.812 0.743 44.1 ;
     RECT  0.535 35.28 2.155 35.298 ;
     RECT  0.635 32.472 2.16 32.832 ;
     RECT  2.155 34.632 2.16 35.298 ;
     RECT  0.535 37.476 2.16 37.494 ;
     RECT  0.535 39.294 2.16 40.968 ;
     RECT  0.535 42.732 2.16 42.75 ;
     RECT  0.743 43.812 2.16 43.83 ;
     RECT  2.155 44.622 2.16 44.64 ;
     RECT  0.203 47.466 2.16 47.484 ;
     RECT  0.535 51.75 2.16 51.768 ;
     RECT  0.535 52.794 2.16 53.01 ;
     RECT  0.535 54.108 2.16 54.126 ;
     RECT  0.535 60.156 2.16 60.714 ;
     RECT  0.103 61.632 2.16 61.92 ;
     RECT  0.535 68.382 2.16 68.976 ;
     RECT  0.103 76.212 2.16 76.23 ;
     RECT  0.247 77.562 2.16 79.74 ;
     RECT  0.283 80.802 2.16 80.82 ;
     RECT  2.16 2.151 84.24 84.249 ;
     RECT  84.24 77.796 84.407 78.354 ;
     RECT  84.24 59.778 84.515 67.554 ;
     RECT  84.407 77.976 84.911 78.354 ;
     RECT  84.24 33.246 84.947 39.474 ;
     RECT  84.24 54.846 84.947 58.41 ;
     RECT  84.515 59.886 84.947 67.554 ;
     RECT  84.24 79.416 84.947 79.434 ;
     RECT  84.24 80.226 84.947 82.242 ;
     RECT  84.947 37.566 84.983 39.204 ;
     RECT  84.24 40.716 85.019 54.09 ;
     RECT  84.947 55.656 85.055 58.41 ;
     RECT  84.947 33.246 85.091 36.648 ;
     RECT  84.947 60.354 85.415 67.554 ;
     RECT  85.415 60.354 85.451 65.664 ;
     RECT  85.415 66.798 85.451 67.554 ;
     RECT  85.019 48.438 85.459 54.09 ;
     RECT  84.947 54.846 85.459 54.864 ;
     RECT  85.451 60.516 85.487 65.664 ;
     RECT  84.911 77.976 85.487 78.084 ;
     RECT  84.947 81.216 85.487 82.242 ;
     RECT  85.091 35.406 85.523 36.648 ;
     RECT  84.983 37.836 85.523 38.664 ;
     RECT  85.459 48.438 85.523 54.864 ;
     RECT  85.055 55.656 85.523 57.708 ;
     RECT  85.487 61.506 85.523 61.722 ;
     RECT  85.487 62.586 85.523 63.27 ;
     RECT  85.487 77.976 85.523 77.994 ;
     RECT  85.487 81.756 85.523 82.242 ;
     RECT  85.091 33.246 85.559 34.65 ;
     RECT  85.523 35.676 85.559 36.648 ;
     RECT  85.523 37.836 85.559 38.43 ;
     RECT  85.019 40.716 85.559 47.61 ;
     RECT  85.523 56.268 85.559 57.708 ;
     RECT  85.559 33.552 85.595 34.254 ;
     RECT  85.559 35.676 85.595 35.694 ;
     RECT  85.559 36.63 85.595 36.648 ;
     RECT  85.523 52.758 85.595 53.388 ;
     RECT  85.523 54.261 85.595 54.279 ;
     RECT  85.559 56.268 85.595 57.519 ;
     RECT  85.523 48.438 85.631 51.354 ;
     RECT  85.595 52.758 85.631 52.974 ;
     RECT  85.595 56.376 85.631 56.898 ;
     RECT  85.595 33.552 85.667 33.57 ;
     RECT  85.631 49.212 85.667 51.354 ;
     RECT  85.631 52.758 85.667 52.776 ;
     RECT  85.631 56.376 85.667 56.826 ;
     RECT  85.559 40.716 85.703 47.304 ;
     RECT  85.667 49.446 85.703 51.354 ;
     RECT  85.631 48.438 85.739 48.456 ;
     RECT  85.703 49.446 86.171 50.112 ;
     RECT  86.171 49.446 86.207 49.464 ;
     RECT  85.703 40.716 86.279 45.99 ;
     RECT  85.451 66.798 86.279 67.392 ;
     RECT  85.523 82.188 86.279 82.242 ;
     RECT  86.215 37.476 86.315 37.494 ;
     RECT  86.279 40.716 86.315 45.558 ;
     RECT  85.703 46.746 86.315 47.304 ;
     RECT  85.703 51.336 86.315 51.354 ;
     RECT  85.667 56.376 86.315 56.394 ;
     RECT  85.523 61.704 86.315 61.722 ;
     RECT  85.523 62.631 86.315 63.27 ;
     RECT  85.487 64.368 86.315 64.962 ;
     RECT  86.279 66.798 86.315 66.816 ;
     RECT  86.215 75.906 86.315 75.924 ;
     RECT  86.279 82.188 86.315 82.206 ;
     RECT  86.315 41.724 86.351 42.858 ;
     RECT  86.315 45.162 86.351 45.558 ;
     RECT  86.315 46.818 86.351 46.836 ;
     RECT  86.351 41.724 86.387 41.742 ;
     RECT  86.351 45.162 86.387 45.18 ;
    LAYER M3 ;
     RECT  2.415 2.143 2.505 2.413 ;
     RECT  7.815 2.143 7.905 2.413 ;
     RECT  13.215 2.143 13.305 2.413 ;
     RECT  18.615 2.143 18.705 2.413 ;
     RECT  24.015 2.143 24.105 2.413 ;
     RECT  29.415 2.143 29.505 2.413 ;
     RECT  34.815 2.143 34.905 2.413 ;
     RECT  40.215 2.143 40.305 2.413 ;
     RECT  45.615 2.143 45.705 2.413 ;
     RECT  51.015 2.143 51.105 2.413 ;
     RECT  56.415 2.143 56.505 2.413 ;
     RECT  61.815 2.143 61.905 2.413 ;
     RECT  67.215 2.143 67.305 2.413 ;
     RECT  72.615 2.143 72.705 2.413 ;
     RECT  78.015 2.143 78.105 2.413 ;
     RECT  83.415 2.143 83.505 2.413 ;
     RECT  7.815 2.413 8.097 32.539 ;
     RECT  0.54 32.467 0.558 32.611 ;
     RECT  6.84 32.539 6.858 32.611 ;
     RECT  7.704 32.539 8.097 32.611 ;
     RECT  6.624 32.611 6.858 32.701 ;
     RECT  4.464 32.431 4.482 32.737 ;
     RECT  6.084 32.701 6.858 32.765 ;
     RECT  6.336 32.765 6.858 32.773 ;
     RECT  7.704 32.611 8.298 32.773 ;
     RECT  0.504 32.611 0.558 32.809 ;
     RECT  40.215 2.413 40.497 32.809 ;
     RECT  4.14 32.737 4.482 32.813 ;
     RECT  2.415 2.413 2.697 32.872 ;
     RECT  5.256 32.845 5.274 32.875 ;
     RECT  2.304 32.872 2.697 32.881 ;
     RECT  0.468 32.809 0.558 32.971 ;
     RECT  43.164 32.737 43.182 32.971 ;
     RECT  44.136 32.881 44.154 32.971 ;
     RECT  2.304 32.881 3.402 32.999 ;
     RECT  4.176 32.813 4.482 32.999 ;
     RECT  9.144 32.881 9.162 32.999 ;
     RECT  38.772 32.845 38.79 32.999 ;
     RECT  2.304 32.999 3.258 33.005 ;
     RECT  5.256 32.875 5.346 33.007 ;
     RECT  0.468 32.971 0.63 33.053 ;
     RECT  0.468 33.053 0.558 33.101 ;
     RECT  43.164 32.971 44.154 33.115 ;
     RECT  42.192 33.043 42.21 33.143 ;
     RECT  4.32 32.999 4.482 33.151 ;
     RECT  5.256 33.007 5.598 33.151 ;
     RECT  6.336 32.773 8.298 33.241 ;
     RECT  46.656 33.151 46.674 33.277 ;
     RECT  43.164 33.115 44.478 33.313 ;
     RECT  45.615 2.413 45.897 33.313 ;
     RECT  46.656 33.277 46.818 33.349 ;
     RECT  39.924 32.809 40.497 33.377 ;
     RECT  10.764 33.349 10.782 33.421 ;
     RECT  43.164 33.313 45.897 33.421 ;
     RECT  80.964 33.277 80.982 33.421 ;
     RECT  46.656 33.349 46.89 33.449 ;
     RECT  85.536 33.241 85.554 33.511 ;
     RECT  6.336 33.241 8.478 33.539 ;
     RECT  85.5 33.511 85.554 33.547 ;
     RECT  9.324 33.421 9.342 33.575 ;
     RECT  80.388 33.421 80.982 33.581 ;
     RECT  4.32 33.151 5.598 33.583 ;
     RECT  6.336 33.539 8.298 33.583 ;
     RECT  4.32 33.583 8.298 33.611 ;
     RECT  10.764 33.421 10.854 33.611 ;
     RECT  0.468 33.101 0.522 33.739 ;
     RECT  83.415 2.413 83.697 33.781 ;
     RECT  41.328 33.547 41.346 33.809 ;
     RECT  0.144 33.739 0.522 33.916 ;
     RECT  2.304 33.005 2.826 33.961 ;
     RECT  42.804 33.421 45.897 33.961 ;
     RECT  46.656 33.449 46.674 33.961 ;
     RECT  80.388 33.581 80.406 33.965 ;
     RECT  0.108 33.916 0.522 34.061 ;
     RECT  85.5 33.547 85.662 34.061 ;
     RECT  4.32 33.611 6.102 34.079 ;
     RECT  6.876 33.611 8.298 34.079 ;
     RECT  10.908 33.961 10.926 34.115 ;
     RECT  2.304 33.961 2.934 34.123 ;
     RECT  4.32 34.079 5.742 34.123 ;
     RECT  38.808 34.087 38.826 34.123 ;
     RECT  85.5 34.061 85.59 34.123 ;
     RECT  9.108 33.889 9.126 34.151 ;
     RECT  0.18 34.061 0.522 34.157 ;
     RECT  83.415 33.781 83.826 34.195 ;
     RECT  84.924 34.123 85.59 34.195 ;
     RECT  2.304 34.123 5.742 34.205 ;
     RECT  38.808 34.123 38.898 34.231 ;
     RECT  41.616 34.051 41.634 34.231 ;
     RECT  42.804 33.961 46.674 34.231 ;
     RECT  37.044 33.781 37.062 34.259 ;
     RECT  38.772 34.231 38.898 34.259 ;
     RECT  38.772 34.259 38.826 34.349 ;
     RECT  40.215 33.377 40.497 34.357 ;
     RECT  41.616 34.231 46.674 34.421 ;
     RECT  6.876 34.079 8.226 34.457 ;
     RECT  9.324 34.321 9.486 34.457 ;
     RECT  6.876 34.457 7.074 34.501 ;
     RECT  9.324 34.457 9.414 34.529 ;
     RECT  41.94 34.421 46.674 34.529 ;
     RECT  83.415 34.195 85.59 34.541 ;
     RECT  46.656 34.529 46.674 34.591 ;
     RECT  2.304 34.205 5.67 34.603 ;
     RECT  83.415 34.541 85.554 34.637 ;
     RECT  2.16 34.603 5.67 34.655 ;
     RECT  9.324 34.529 9.342 34.655 ;
     RECT  40.215 34.357 40.626 34.691 ;
     RECT  46.656 34.591 46.818 34.691 ;
     RECT  6.84 34.501 7.074 34.771 ;
     RECT  7.815 34.457 8.226 34.933 ;
     RECT  40.215 34.691 40.554 35.033 ;
     RECT  7.815 34.933 8.37 35.159 ;
     RECT  10.836 35.041 10.854 35.159 ;
     RECT  41.94 34.529 45.897 35.159 ;
     RECT  9.216 35.041 9.234 35.195 ;
     RECT  2.304 34.655 3.51 35.231 ;
     RECT  0.144 34.795 0.162 35.275 ;
     RECT  4.32 34.655 5.67 35.401 ;
     RECT  6.588 34.771 7.074 35.401 ;
     RECT  0.144 35.275 0.558 35.405 ;
     RECT  4.32 35.401 7.074 35.429 ;
     RECT  46.836 35.401 46.962 35.473 ;
     RECT  83.415 34.637 83.697 35.473 ;
     RECT  84.42 34.637 85.554 35.473 ;
     RECT  83.415 35.473 85.554 35.501 ;
     RECT  38.808 34.349 38.826 35.509 ;
     RECT  4.428 35.429 7.074 35.515 ;
     RECT  7.815 35.159 8.154 35.515 ;
     RECT  2.304 35.231 3.402 35.563 ;
     RECT  4.428 35.515 8.154 35.573 ;
     RECT  85.5 35.501 85.554 35.671 ;
     RECT  0.144 35.405 0.162 35.693 ;
     RECT  2.268 35.563 3.402 35.699 ;
     RECT  38.808 35.509 38.862 35.699 ;
     RECT  42.408 35.159 45.897 35.699 ;
     RECT  4.464 35.573 8.154 35.735 ;
     RECT  38.772 35.707 38.79 35.807 ;
     RECT  46.764 35.473 46.962 35.843 ;
     RECT  43.56 35.699 45.897 35.879 ;
     RECT  4.464 35.735 7.002 35.969 ;
     RECT  4.464 35.969 6.966 36.029 ;
     RECT  41.616 35.203 41.634 36.049 ;
     RECT  42.408 35.699 42.534 36.049 ;
     RECT  45 35.879 45.897 36.121 ;
     RECT  41.616 36.049 42.534 36.239 ;
     RECT  40.215 35.033 40.497 36.283 ;
     RECT  85.5 35.671 85.59 36.283 ;
     RECT  9.144 35.941 9.162 36.391 ;
     RECT  45 36.121 46.674 36.419 ;
     RECT  9.072 36.391 9.162 36.472 ;
     RECT  42.192 36.239 42.534 36.481 ;
     RECT  43.56 35.879 43.866 36.481 ;
     RECT  83.415 35.501 84.438 36.481 ;
     RECT  85.464 36.283 86.238 36.481 ;
     RECT  40.215 36.283 40.554 36.509 ;
     RECT  42.192 36.481 43.866 36.509 ;
     RECT  8.964 36.472 9.162 36.581 ;
     RECT  82.08 36.121 82.098 36.589 ;
     RECT  83.415 36.481 86.238 36.653 ;
     RECT  2.268 35.699 2.79 36.661 ;
     RECT  4.464 36.029 5.634 36.661 ;
     RECT  7.812 35.735 8.154 36.661 ;
     RECT  45 36.419 46.53 36.751 ;
     RECT  4.392 36.661 5.634 36.763 ;
     RECT  82.08 36.589 82.134 36.787 ;
     RECT  6.408 36.029 6.966 36.811 ;
     RECT  9.324 36.661 9.414 36.815 ;
     RECT  41.364 36.481 41.382 36.815 ;
     RECT  42.444 36.509 43.866 36.823 ;
     RECT  0.144 36.715 0.162 36.893 ;
     RECT  6.408 36.811 7.002 36.895 ;
     RECT  7.812 36.661 8.478 36.895 ;
     RECT  42.444 36.823 43.902 36.895 ;
     RECT  44.784 36.751 46.53 36.895 ;
     RECT  82.08 36.787 82.17 36.895 ;
     RECT  38.772 36.787 38.79 36.923 ;
     RECT  4.248 36.763 5.634 36.931 ;
     RECT  82.08 36.895 82.242 36.941 ;
     RECT  9.432 36.823 9.45 36.959 ;
     RECT  4.212 36.931 5.634 37.021 ;
     RECT  6.408 36.895 8.478 37.021 ;
     RECT  82.116 36.941 82.242 37.133 ;
     RECT  10.8 36.931 10.818 37.327 ;
     RECT  41.508 37.327 41.67 37.363 ;
     RECT  42.444 36.895 46.53 37.363 ;
     RECT  2.268 36.661 3.474 37.387 ;
     RECT  4.212 37.021 8.478 37.387 ;
     RECT  2.268 37.387 8.478 37.391 ;
     RECT  82.152 37.133 82.242 37.421 ;
     RECT  2.268 37.391 8.298 37.427 ;
     RECT  84.924 36.653 86.238 37.471 ;
     RECT  84.924 37.471 86.31 37.499 ;
     RECT  86.292 37.499 86.31 37.517 ;
     RECT  82.224 37.421 82.242 37.613 ;
     RECT  41.508 37.363 46.53 37.669 ;
     RECT  2.304 37.427 8.298 37.733 ;
     RECT  9.288 37.669 9.306 37.741 ;
     RECT  40.215 36.509 40.497 37.741 ;
     RECT  41.508 37.669 46.818 37.741 ;
     RECT  9.216 37.741 9.306 37.769 ;
     RECT  2.304 37.733 4.554 37.859 ;
     RECT  40.215 37.741 46.818 37.867 ;
     RECT  9.216 37.769 9.234 37.895 ;
     RECT  0.54 37.471 0.558 37.901 ;
     RECT  40.104 37.867 46.818 37.901 ;
     RECT  82.656 37.741 82.674 37.997 ;
     RECT  43.704 37.901 46.818 38.129 ;
     RECT  5.472 37.733 8.298 38.165 ;
     RECT  2.304 37.859 4.482 38.201 ;
     RECT  40.104 37.901 42.858 38.201 ;
     RECT  79.236 38.173 79.254 38.285 ;
     RECT  37.62 37.903 37.638 38.309 ;
     RECT  40.104 38.201 42.102 38.399 ;
     RECT  43.704 38.129 45.897 38.435 ;
     RECT  83.415 36.653 83.697 38.443 ;
     RECT  84.924 37.499 85.554 38.443 ;
     RECT  10.8 37.327 10.854 38.471 ;
     RECT  2.304 38.201 3.618 38.477 ;
     RECT  5.472 38.165 6.03 38.491 ;
     RECT  0.144 38.347 0.162 38.525 ;
     RECT  10.836 38.471 10.854 38.543 ;
     RECT  40.215 38.399 42.102 38.543 ;
     RECT  40.215 38.543 41.238 38.579 ;
     RECT  4.392 38.201 4.482 38.641 ;
     RECT  5.256 38.491 6.03 38.641 ;
     RECT  3.456 38.477 3.618 38.669 ;
     RECT  38.772 38.407 38.79 38.669 ;
     RECT  83.415 38.443 85.554 38.669 ;
     RECT  4.392 38.641 6.03 38.705 ;
     RECT  7.02 38.165 8.298 38.785 ;
     RECT  9.216 38.749 9.234 38.821 ;
     RECT  43.704 38.435 44.514 38.821 ;
     RECT  9.216 38.821 9.306 38.849 ;
     RECT  83.415 38.669 85.518 38.861 ;
     RECT  56.415 2.413 56.697 38.911 ;
     RECT  61.815 2.413 62.097 38.911 ;
     RECT  67.215 2.413 67.497 38.911 ;
     RECT  78.015 2.413 78.297 38.911 ;
     RECT  9.288 38.849 9.306 38.939 ;
     RECT  46.8 38.129 46.818 38.947 ;
     RECT  41.22 38.579 41.238 38.957 ;
     RECT  45.504 38.435 45.897 38.957 ;
     RECT  56.304 38.911 56.697 38.957 ;
     RECT  67.104 38.911 67.497 38.957 ;
     RECT  77.904 38.911 78.297 38.957 ;
     RECT  2.304 38.477 2.697 38.975 ;
     RECT  7.02 38.785 8.37 38.975 ;
     RECT  43.488 38.821 44.514 39.011 ;
     RECT  54.72 38.911 54.738 39.011 ;
     RECT  61.815 38.911 62.73 39.011 ;
     RECT  74.664 38.911 74.682 39.011 ;
     RECT  46.764 38.947 46.818 39.047 ;
     RECT  83.415 38.861 84.978 39.053 ;
     RECT  5.94 38.705 6.03 39.055 ;
     RECT  5.004 38.705 5.202 39.101 ;
     RECT  9.324 38.983 9.342 39.119 ;
     RECT  43.488 39.011 43.902 39.119 ;
     RECT  46.8 39.047 46.818 39.119 ;
     RECT  83.415 39.053 83.826 39.149 ;
     RECT  43.488 39.119 43.758 39.181 ;
     RECT  42.084 38.543 42.102 39.209 ;
     RECT  43.416 39.181 43.758 39.245 ;
     RECT  79.812 38.821 79.83 39.245 ;
     RECT  84.924 39.053 84.978 39.437 ;
     RECT  43.416 39.245 43.686 39.515 ;
     RECT  7.02 38.975 8.154 39.523 ;
     RECT  43.416 39.515 43.434 39.523 ;
     RECT  42.768 39.523 43.434 39.533 ;
     RECT  5.94 39.055 6.102 39.559 ;
     RECT  3.852 39.361 3.87 39.595 ;
     RECT  42.768 39.533 42.786 39.623 ;
     RECT  84.924 39.437 84.942 39.629 ;
     RECT  2.415 38.975 2.697 39.721 ;
     RECT  3.708 39.595 3.87 39.721 ;
     RECT  0.54 39.289 0.558 39.739 ;
     RECT  0.18 39.739 0.558 39.787 ;
     RECT  5.58 39.559 6.102 39.787 ;
     RECT  6.84 39.523 8.154 39.787 ;
     RECT  4.644 39.631 4.662 39.829 ;
     RECT  45.615 38.957 45.897 39.829 ;
     RECT  2.415 39.721 3.87 39.865 ;
     RECT  4.644 39.829 4.698 39.865 ;
     RECT  45.036 39.829 45.897 39.865 ;
     RECT  5.58 39.787 8.154 39.991 ;
     RECT  2.415 39.865 4.698 40.027 ;
     RECT  45.036 39.865 45.954 40.063 ;
     RECT  5.58 39.991 8.298 40.163 ;
     RECT  44.604 40.063 45.954 40.171 ;
     RECT  2.304 40.027 4.698 40.261 ;
     RECT  5.58 40.163 6.03 40.261 ;
     RECT  44.604 40.171 46.062 40.261 ;
     RECT  2.304 40.261 6.03 40.442 ;
     RECT  6.768 40.163 8.298 40.469 ;
     RECT  0.108 39.787 0.558 40.493 ;
     RECT  83.415 39.149 83.697 40.531 ;
     RECT  0.108 40.493 0.486 40.589 ;
     RECT  83.415 40.531 83.826 40.589 ;
     RECT  44.46 40.261 46.062 40.639 ;
     RECT  40.215 38.579 40.497 40.651 ;
     RECT  41.652 40.567 41.67 40.651 ;
     RECT  2.304 40.442 4.554 40.685 ;
     RECT  9.324 40.603 9.342 40.711 ;
     RECT  40.215 40.651 41.67 40.711 ;
     RECT  9.324 40.711 9.414 40.801 ;
     RECT  78.015 38.957 78.297 40.873 ;
     RECT  85.5 40.837 85.518 40.877 ;
     RECT  47.808 40.837 47.826 40.909 ;
     RECT  9.324 40.801 9.486 40.937 ;
     RECT  40.215 40.711 41.886 40.939 ;
     RECT  6.84 40.469 8.298 41.071 ;
     RECT  44.46 40.639 46.206 41.071 ;
     RECT  40.215 40.939 42.21 41.107 ;
     RECT  40.215 41.107 42.786 41.131 ;
     RECT  40.215 41.131 43.182 41.143 ;
     RECT  44.1 41.071 46.206 41.143 ;
     RECT  10.836 40.531 10.854 41.215 ;
     RECT  6.84 41.071 8.55 41.251 ;
     RECT  10.836 41.215 10.926 41.251 ;
     RECT  5.292 40.442 6.03 41.341 ;
     RECT  6.804 41.251 8.55 41.341 ;
     RECT  84.888 41.323 84.906 41.341 ;
     RECT  10.8 41.251 10.926 41.369 ;
     RECT  0.108 40.589 0.126 41.371 ;
     RECT  84.816 41.341 84.906 41.405 ;
     RECT  5.292 41.341 8.55 41.413 ;
     RECT  40.215 41.143 46.206 41.419 ;
     RECT  10.8 41.369 10.854 41.441 ;
     RECT  5.292 41.413 9.198 41.485 ;
     RECT  56.415 38.957 56.697 41.512 ;
     RECT  67.215 38.957 67.497 41.512 ;
     RECT  78.015 40.873 78.354 41.512 ;
     RECT  38.808 41.071 38.826 41.521 ;
     RECT  47.808 40.909 48.114 41.521 ;
     RECT  0.108 41.371 0.162 41.548 ;
     RECT  56.304 41.512 56.697 41.549 ;
     RECT  67.104 41.512 67.497 41.549 ;
     RECT  77.904 41.512 78.354 41.549 ;
     RECT  2.304 40.685 4.518 41.611 ;
     RECT  5.256 41.485 9.198 41.611 ;
     RECT  84.888 41.405 84.906 41.647 ;
     RECT  38.196 41.521 38.826 41.683 ;
     RECT  84.888 41.647 85.518 41.683 ;
     RECT  86.292 40.459 86.31 41.683 ;
     RECT  10.836 41.441 10.854 41.711 ;
     RECT  84.888 41.683 86.31 41.719 ;
     RECT  2.304 41.611 9.198 41.755 ;
     RECT  0.108 41.548 0.198 41.789 ;
     RECT  40.215 41.419 46.746 41.791 ;
     RECT  47.664 41.521 48.114 41.791 ;
     RECT  83.415 40.589 83.79 41.791 ;
     RECT  0.108 41.789 0.126 41.837 ;
     RECT  84.888 41.719 86.382 41.837 ;
     RECT  2.304 41.755 9.27 41.899 ;
     RECT  38.196 41.683 39.366 41.909 ;
     RECT  83.415 41.791 83.826 41.933 ;
     RECT  40.176 41.791 48.114 42.025 ;
     RECT  38.772 41.909 39.366 42.259 ;
     RECT  40.176 42.025 48.186 42.259 ;
     RECT  38.772 42.259 48.186 42.331 ;
     RECT  84.888 41.837 84.906 42.493 ;
     RECT  84.636 42.493 84.906 42.571 ;
     RECT  86.112 41.837 86.382 42.571 ;
     RECT  84.636 42.571 86.382 42.593 ;
     RECT  10.8 42.565 10.818 42.719 ;
     RECT  2.304 41.899 9.378 42.755 ;
     RECT  0.54 42.727 0.558 42.797 ;
     RECT  38.772 42.331 48.546 42.799 ;
     RECT  51.015 2.413 51.297 42.799 ;
     RECT  3.852 42.755 9.378 42.835 ;
     RECT  50.688 42.799 51.297 42.871 ;
     RECT  83.415 41.933 83.79 42.955 ;
     RECT  34.815 2.413 35.097 42.961 ;
     RECT  83.415 42.955 83.826 42.961 ;
     RECT  38.412 42.799 48.546 42.989 ;
     RECT  10.692 42.871 10.782 43.025 ;
     RECT  39.996 42.989 48.546 43.099 ;
     RECT  39.996 43.099 48.618 43.105 ;
     RECT  50.652 42.871 51.297 43.133 ;
     RECT  2.304 42.755 2.97 43.141 ;
     RECT  50.688 43.133 51.297 43.169 ;
     RECT  13.215 2.413 13.497 43.231 ;
     RECT  24.015 2.413 24.297 43.231 ;
     RECT  34.776 42.961 35.097 43.231 ;
     RECT  56.415 41.549 56.697 43.243 ;
     RECT  67.215 41.549 67.497 43.243 ;
     RECT  78.015 41.549 78.354 43.243 ;
     RECT  2.268 43.141 2.97 43.277 ;
     RECT  13.104 43.231 13.497 43.277 ;
     RECT  23.904 43.231 24.297 43.277 ;
     RECT  34.704 43.231 35.097 43.277 ;
     RECT  56.304 43.243 56.697 43.295 ;
     RECT  67.104 43.243 67.497 43.295 ;
     RECT  77.904 43.243 78.354 43.295 ;
     RECT  83.196 42.961 83.826 43.303 ;
     RECT  38.772 42.989 38.97 43.331 ;
     RECT  84.636 42.593 84.654 43.339 ;
     RECT  85.464 42.593 86.382 43.339 ;
     RECT  38.772 43.331 38.934 43.34 ;
     RECT  34.776 43.277 35.097 43.403 ;
     RECT  37.044 40.297 37.062 43.403 ;
     RECT  82.656 43.303 83.826 43.411 ;
     RECT  84.636 43.339 86.382 43.411 ;
     RECT  2.304 43.277 2.97 43.501 ;
     RECT  10.728 43.025 10.782 43.501 ;
     RECT  2.304 43.501 3.042 43.601 ;
     RECT  38.772 43.34 38.898 43.601 ;
     RECT  80.64 41.989 80.658 43.645 ;
     RECT  3.852 42.835 9.414 43.681 ;
     RECT  10.728 43.501 10.818 43.709 ;
     RECT  38.772 43.601 38.862 43.799 ;
     RECT  0.144 43.723 0.162 43.807 ;
     RECT  39.996 43.105 48.834 43.819 ;
     RECT  3.816 43.681 9.414 43.835 ;
     RECT  39.996 43.819 48.87 43.843 ;
     RECT  39.96 43.843 48.87 43.871 ;
     RECT  0.144 43.807 0.558 43.901 ;
     RECT  0.54 43.901 0.558 43.915 ;
     RECT  0.54 43.915 0.666 43.949 ;
     RECT  82.656 43.411 86.382 43.949 ;
     RECT  83.232 43.949 86.382 43.979 ;
     RECT  0.648 43.949 0.666 44.059 ;
     RECT  39.96 43.871 48.834 44.069 ;
     RECT  0.648 44.059 0.738 44.105 ;
     RECT  0.648 44.105 0.666 44.141 ;
     RECT  39.96 44.069 47.934 44.141 ;
     RECT  78.015 43.295 78.354 44.141 ;
     RECT  43.2 44.141 47.934 44.177 ;
     RECT  13.215 43.277 13.497 44.203 ;
     RECT  24.015 43.277 24.297 44.203 ;
     RECT  34.815 43.403 35.097 44.203 ;
     RECT  38.808 43.799 38.862 44.222 ;
     RECT  80.388 43.645 80.658 44.237 ;
     RECT  13.104 44.203 13.497 44.249 ;
     RECT  23.904 44.203 24.297 44.249 ;
     RECT  34.704 44.203 35.097 44.249 ;
     RECT  48.672 44.069 48.762 44.249 ;
     RECT  2.304 43.601 2.934 44.299 ;
     RECT  10.836 44.041 10.926 44.339 ;
     RECT  3.852 43.835 9.414 44.375 ;
     RECT  80.388 44.237 80.406 44.429 ;
     RECT  38.808 44.222 38.826 44.581 ;
     RECT  2.268 44.299 2.934 44.587 ;
     RECT  2.16 44.587 2.934 44.645 ;
     RECT  2.304 44.645 2.934 44.761 ;
     RECT  43.2 44.177 47.466 44.789 ;
     RECT  83.232 43.979 84.654 44.813 ;
     RECT  0.108 44.806 0.198 44.909 ;
     RECT  2.304 44.761 3.114 44.951 ;
     RECT  0.18 44.909 0.198 44.957 ;
     RECT  38.772 44.581 38.826 44.987 ;
     RECT  2.304 44.951 3.006 45.185 ;
     RECT  43.2 44.789 46.854 45.185 ;
     RECT  85.5 43.979 86.382 45.185 ;
     RECT  39.96 44.141 42.354 45.229 ;
     RECT  43.2 45.185 46.818 45.229 ;
     RECT  2.304 45.185 2.934 45.257 ;
     RECT  39.96 45.229 46.818 45.329 ;
     RECT  10.836 44.339 10.854 45.427 ;
     RECT  39.96 45.329 46.782 45.427 ;
     RECT  39.924 45.427 46.782 45.491 ;
     RECT  83.232 44.813 83.697 45.499 ;
     RECT  10.764 45.427 10.854 45.563 ;
     RECT  84.636 44.813 84.654 45.581 ;
     RECT  2.304 45.257 2.862 45.599 ;
     RECT  39.924 45.491 41.094 45.725 ;
     RECT  38.196 45.463 38.214 45.733 ;
     RECT  82.728 45.499 83.697 45.733 ;
     RECT  10.836 45.563 10.854 45.761 ;
     RECT  41.868 45.491 46.782 45.761 ;
     RECT  2.304 45.599 2.718 45.835 ;
     RECT  41.868 45.761 46.71 45.869 ;
     RECT  82.728 45.733 83.826 45.931 ;
     RECT  39.96 45.725 41.094 45.959 ;
     RECT  2.268 45.835 2.718 45.995 ;
     RECT  0.324 45.931 0.342 46.061 ;
     RECT  82.728 45.931 83.862 46.075 ;
     RECT  82.08 46.075 83.862 46.301 ;
     RECT  2.304 45.995 2.718 46.345 ;
     RECT  3.852 44.375 9.378 46.345 ;
     RECT  38.196 45.733 38.79 46.381 ;
     RECT  40.176 45.959 41.094 46.471 ;
     RECT  41.868 45.869 46.638 46.471 ;
     RECT  10.8 46.381 10.818 46.499 ;
     RECT  38.196 46.381 38.862 46.499 ;
     RECT  2.304 46.345 9.378 46.643 ;
     RECT  0.144 46.555 0.162 46.733 ;
     RECT  40.176 46.471 46.638 46.741 ;
     RECT  85.5 45.185 86.346 46.841 ;
     RECT  82.692 46.301 83.862 46.925 ;
     RECT  40.176 46.741 47.214 47.011 ;
     RECT  40.176 47.011 47.25 47.111 ;
     RECT  0.324 46.987 0.342 47.117 ;
     RECT  38.196 46.499 38.826 47.147 ;
     RECT  41.616 47.111 47.25 47.155 ;
     RECT  38.196 47.147 38.322 47.183 ;
     RECT  83.415 46.925 83.862 47.191 ;
     RECT  41.616 47.155 47.322 47.345 ;
     RECT  47.304 47.345 47.322 47.489 ;
     RECT  0.144 47.461 0.198 47.5 ;
     RECT  41.616 47.345 46.314 47.579 ;
     RECT  0.108 47.5 0.198 47.597 ;
     RECT  40.176 47.111 40.554 47.623 ;
     RECT  0.144 47.597 0.198 47.645 ;
     RECT  79.236 46.849 79.254 47.693 ;
     RECT  10.764 47.623 10.782 47.731 ;
     RECT  10.764 47.731 10.854 47.759 ;
     RECT  83.415 47.191 84.402 47.789 ;
     RECT  85.5 46.841 86.31 47.821 ;
     RECT  10.836 47.759 10.854 47.849 ;
     RECT  38.196 47.183 38.25 47.849 ;
     RECT  80.388 46.813 80.406 47.885 ;
     RECT  2.304 46.643 9.306 48.001 ;
     RECT  2.268 48.001 9.306 48.077 ;
     RECT  39.924 47.623 40.554 48.163 ;
     RECT  2.304 48.077 9.306 48.557 ;
     RECT  41.976 47.579 46.314 48.631 ;
     RECT  0.144 47.645 0.162 48.653 ;
     RECT  3.672 48.557 9.306 48.659 ;
     RECT  3.744 48.659 9.306 48.695 ;
     RECT  83.415 47.789 83.79 48.703 ;
     RECT  84.924 47.821 86.31 48.703 ;
     RECT  10.908 47.965 10.926 49.001 ;
     RECT  3.852 48.695 9.306 49.009 ;
     RECT  3.852 49.009 9.342 49.045 ;
     RECT  38.232 47.849 38.25 49.045 ;
     RECT  0.18 49.051 0.27 49.109 ;
     RECT  38.232 49.045 38.79 49.109 ;
     RECT  0.18 49.109 0.198 49.133 ;
     RECT  83.415 48.703 86.31 49.133 ;
     RECT  1.116 49.003 1.134 49.181 ;
     RECT  3.852 49.045 9.414 49.199 ;
     RECT  39.924 48.163 41.094 49.199 ;
     RECT  41.976 48.631 46.674 49.207 ;
     RECT  74.664 47.155 74.682 49.229 ;
     RECT  39.996 49.199 41.094 49.351 ;
     RECT  41.976 49.207 46.782 49.351 ;
     RECT  39.996 49.351 46.782 49.379 ;
     RECT  38.772 49.109 38.79 49.469 ;
     RECT  39.996 49.379 46.746 49.469 ;
     RECT  2.304 48.557 2.898 49.477 ;
     RECT  3.852 49.199 9.306 49.477 ;
     RECT  83.415 49.133 83.826 49.517 ;
     RECT  2.304 49.477 9.306 49.675 ;
     RECT  82.656 48.973 82.674 49.711 ;
     RECT  83.415 49.517 83.697 49.711 ;
     RECT  82.656 49.711 83.697 49.805 ;
     RECT  2.268 49.675 9.306 49.847 ;
     RECT  39.996 49.469 41.31 50.089 ;
     RECT  2.304 49.847 9.306 50.161 ;
     RECT  56.415 43.295 56.697 50.251 ;
     RECT  67.215 43.295 67.497 50.251 ;
     RECT  78.015 44.141 78.297 50.251 ;
     RECT  56.304 50.251 56.697 50.288 ;
     RECT  67.104 50.251 67.497 50.288 ;
     RECT  77.904 50.251 78.297 50.288 ;
     RECT  42.192 49.469 46.746 50.323 ;
     RECT  78.015 50.288 78.297 50.323 ;
     RECT  2.304 50.161 9.414 50.333 ;
     RECT  7.704 50.333 9.414 50.351 ;
     RECT  0.18 50.107 0.198 50.359 ;
     RECT  10.8 49.747 10.818 50.423 ;
     RECT  78.015 50.323 78.75 50.423 ;
     RECT  39.6 50.089 41.31 50.665 ;
     RECT  7.704 50.351 9.342 50.729 ;
     RECT  39.348 50.665 41.31 50.791 ;
     RECT  42.192 50.323 46.818 50.791 ;
     RECT  78.015 50.423 78.678 50.957 ;
     RECT  39.348 50.791 46.818 50.963 ;
     RECT  37.656 50.971 37.674 51.097 ;
     RECT  2.304 50.333 6.966 51.163 ;
     RECT  7.704 50.729 9.306 51.163 ;
     RECT  2.304 51.163 9.306 51.233 ;
     RECT  0.108 50.359 0.198 51.341 ;
     RECT  37.62 51.097 37.674 51.359 ;
     RECT  84.924 49.133 86.31 51.359 ;
     RECT  39.348 50.963 46.782 51.367 ;
     RECT  83.232 49.805 83.697 51.367 ;
     RECT  0.18 51.341 0.198 51.389 ;
     RECT  82.08 50.287 82.098 51.389 ;
     RECT  84.924 51.359 86.238 51.629 ;
     RECT  38.808 51.367 46.782 51.637 ;
     RECT  38.772 51.637 46.782 51.809 ;
     RECT  39.348 51.809 46.782 51.899 ;
     RECT  0.54 51.745 0.558 51.917 ;
     RECT  84.924 51.629 86.202 51.917 ;
     RECT  2.304 51.233 2.862 52.015 ;
     RECT  3.852 51.233 9.306 52.015 ;
     RECT  29.415 2.413 29.697 52.141 ;
     RECT  40.176 51.899 46.782 52.169 ;
     RECT  83.232 51.367 83.826 52.177 ;
     RECT  10.908 52.213 10.926 52.249 ;
     RECT  29.16 52.141 29.697 52.267 ;
     RECT  40.176 52.169 46.746 52.277 ;
     RECT  10.8 52.249 10.926 52.313 ;
     RECT  28.836 52.267 29.697 52.313 ;
     RECT  10.8 52.313 10.818 52.349 ;
     RECT  2.304 52.015 9.306 52.363 ;
     RECT  2.268 52.363 9.306 52.439 ;
     RECT  40.176 52.277 45.897 52.439 ;
     RECT  2.268 52.439 8.154 52.547 ;
     RECT  2.304 52.547 8.154 52.589 ;
     RECT  82.728 52.177 83.826 52.589 ;
     RECT  39.348 51.899 39.366 52.619 ;
     RECT  56.415 50.288 56.697 52.681 ;
     RECT  61.815 39.011 62.097 52.681 ;
     RECT  67.215 50.288 67.497 52.681 ;
     RECT  78.015 50.957 78.297 52.681 ;
     RECT  54.72 52.681 54.738 52.753 ;
     RECT  61.815 52.681 62.73 52.753 ;
     RECT  74.664 52.681 74.682 52.753 ;
     RECT  54.72 52.753 54.81 52.781 ;
     RECT  56.415 52.681 56.754 52.781 ;
     RECT  67.215 52.681 67.554 52.781 ;
     RECT  74.664 52.753 74.754 52.781 ;
     RECT  78.015 52.681 78.354 52.781 ;
     RECT  84.924 51.917 86.166 52.795 ;
     RECT  56.415 52.781 56.697 52.843 ;
     RECT  67.215 52.781 67.497 52.843 ;
     RECT  78.015 52.781 78.297 52.843 ;
     RECT  35.928 52.249 35.946 52.853 ;
     RECT  83.415 52.589 83.826 52.861 ;
     RECT  84.924 52.795 86.238 52.861 ;
     RECT  54.792 52.781 54.81 52.889 ;
     RECT  56.304 52.843 56.697 52.889 ;
     RECT  61.815 52.753 62.802 52.889 ;
     RECT  67.104 52.843 67.497 52.889 ;
     RECT  74.736 52.781 74.754 52.889 ;
     RECT  77.904 52.843 78.297 52.889 ;
     RECT  0.54 52.789 0.558 52.939 ;
     RECT  0.54 52.939 0.594 52.951 ;
     RECT  83.415 52.861 86.238 52.973 ;
     RECT  31.032 42.529 31.05 52.979 ;
     RECT  40.215 52.439 45.897 52.979 ;
     RECT  46.656 52.277 46.746 52.979 ;
     RECT  0.54 52.951 0.666 52.987 ;
     RECT  46.728 52.979 46.746 53.015 ;
     RECT  0.108 52.987 0.666 53.021 ;
     RECT  0.108 53.021 0.558 53.069 ;
     RECT  37.656 51.359 37.674 53.159 ;
     RECT  0.108 53.069 0.162 53.165 ;
     RECT  41.616 52.979 45.897 53.285 ;
     RECT  2.304 52.589 7.002 53.32 ;
     RECT  7.776 52.589 8.154 53.32 ;
     RECT  82.656 53.257 82.674 53.393 ;
     RECT  46.8 53.293 46.818 53.429 ;
     RECT  2.304 53.32 8.154 53.519 ;
     RECT  41.616 53.285 42.318 53.519 ;
     RECT  2.304 53.519 5.778 53.549 ;
     RECT  2.304 53.549 3.258 53.555 ;
     RECT  42.192 53.519 42.318 53.591 ;
     RECT  83.415 52.973 85.698 53.741 ;
     RECT  2.412 53.555 3.258 53.795 ;
     RECT  42.3 53.591 42.318 53.825 ;
     RECT  2.412 53.795 2.826 53.837 ;
     RECT  83.415 53.741 85.626 53.837 ;
     RECT  6.588 53.519 8.154 53.905 ;
     RECT  8.928 52.439 9.306 53.905 ;
     RECT  0.144 53.165 0.162 54.029 ;
     RECT  6.588 53.905 9.306 54.059 ;
     RECT  0.216 54.103 0.558 54.221 ;
     RECT  2.412 53.837 2.697 54.283 ;
     RECT  4.14 53.549 5.778 54.301 ;
     RECT  84.924 53.837 85.626 54.317 ;
     RECT  7.815 54.059 9.306 54.329 ;
     RECT  7.815 54.329 9.09 54.365 ;
     RECT  43.092 53.285 45.897 54.365 ;
     RECT  56.415 52.889 56.697 54.472 ;
     RECT  67.215 52.889 67.497 54.472 ;
     RECT  78.015 52.889 78.297 54.472 ;
     RECT  3.924 54.301 5.778 54.473 ;
     RECT  6.588 54.059 7.074 54.509 ;
     RECT  2.304 54.283 2.697 54.523 ;
     RECT  4.428 54.473 5.778 54.599 ;
     RECT  46.728 54.427 46.746 54.605 ;
     RECT  2.232 54.523 2.697 54.607 ;
     RECT  2.232 54.607 3.222 54.635 ;
     RECT  0.216 54.221 0.342 54.701 ;
     RECT  43.2 54.365 45.897 54.701 ;
     RECT  0.216 54.701 0.234 54.751 ;
     RECT  0.144 54.751 0.234 54.779 ;
     RECT  0.144 54.779 0.162 54.797 ;
     RECT  9.072 54.365 9.09 54.869 ;
     RECT  6.588 54.509 6.822 54.949 ;
     RECT  7.815 54.365 8.154 54.949 ;
     RECT  46.8 54.841 46.818 54.977 ;
     RECT  83.415 53.837 83.697 55.003 ;
     RECT  4.5 54.599 5.778 55.013 ;
     RECT  6.516 54.949 6.822 55.049 ;
     RECT  56.304 54.472 56.697 55.049 ;
     RECT  67.104 54.472 67.497 55.049 ;
     RECT  77.904 54.472 78.297 55.049 ;
     RECT  83.304 55.003 83.697 55.049 ;
     RECT  85.5 54.317 85.626 55.111 ;
     RECT  6.588 55.049 6.822 55.139 ;
     RECT  40.215 52.979 40.497 55.147 ;
     RECT  6.732 55.139 6.822 55.181 ;
     RECT  43.2 54.701 44.01 55.181 ;
     RECT  81.54 54.877 81.558 55.183 ;
     RECT  4.5 55.013 5.706 55.198 ;
     RECT  2.304 54.635 3.222 55.255 ;
     RECT  84.924 55.111 85.626 55.277 ;
     RECT  7.704 54.949 8.154 55.291 ;
     RECT  85.5 55.277 85.626 55.339 ;
     RECT  4.5 55.198 5.634 55.381 ;
     RECT  42.264 55.183 42.282 55.417 ;
     RECT  43.2 55.181 43.794 55.417 ;
     RECT  81.504 55.183 81.558 55.517 ;
     RECT  85.5 55.339 86.238 55.517 ;
     RECT  44.748 54.701 45.897 55.525 ;
     RECT  2.304 55.255 3.618 55.531 ;
     RECT  4.464 55.381 5.634 55.531 ;
     RECT  1.152 55.579 1.17 55.627 ;
     RECT  38.808 55.561 38.826 55.678 ;
     RECT  2.304 55.531 5.634 55.679 ;
     RECT  38.808 55.678 38.862 55.679 ;
     RECT  42.264 55.417 43.794 55.679 ;
     RECT  3.996 55.679 5.634 55.715 ;
     RECT  1.152 55.627 1.278 55.757 ;
     RECT  81.54 55.517 81.558 55.757 ;
     RECT  83.415 55.049 83.697 55.759 ;
     RECT  38.844 55.679 38.862 55.787 ;
     RECT  2.304 55.679 2.97 55.915 ;
     RECT  51.015 43.169 51.297 55.921 ;
     RECT  4.032 55.715 5.634 55.993 ;
     RECT  7.236 55.291 8.154 55.993 ;
     RECT  83.415 55.759 83.826 55.993 ;
     RECT  83.415 55.993 84.402 56.029 ;
     RECT  82.656 55.723 82.674 56.045 ;
     RECT  83.415 56.029 84.474 56.065 ;
     RECT  85.5 55.517 85.626 56.065 ;
     RECT  4.032 55.993 5.706 56.093 ;
     RECT  50.652 55.921 51.297 56.093 ;
     RECT  7.092 55.993 8.154 56.101 ;
     RECT  40.215 55.147 41.058 56.129 ;
     RECT  7.02 56.101 8.154 56.219 ;
     RECT  7.815 56.219 8.154 56.227 ;
     RECT  8.892 56.101 8.91 56.227 ;
     RECT  44.712 55.525 45.897 56.227 ;
     RECT  83.415 56.065 85.626 56.237 ;
     RECT  42.3 55.679 43.794 56.255 ;
     RECT  2.196 55.915 2.97 56.327 ;
     RECT  44.532 56.227 45.897 56.327 ;
     RECT  84.456 56.237 85.626 56.333 ;
     RECT  4.068 56.093 5.706 56.335 ;
     RECT  84.924 56.333 85.626 56.347 ;
     RECT  43.524 56.255 43.794 56.371 ;
     RECT  84.924 56.347 86.238 56.371 ;
     RECT  80.388 56.101 80.406 56.381 ;
     RECT  0.18 56.347 0.198 56.395 ;
     RECT  84.924 56.371 86.31 56.429 ;
     RECT  46.656 55.993 46.674 56.461 ;
     RECT  4.068 56.335 6.102 56.489 ;
     RECT  42.3 56.255 42.786 56.489 ;
     RECT  44.784 56.327 45.897 56.491 ;
     RECT  46.656 56.461 46.854 56.491 ;
     RECT  7.02 56.219 7.074 56.497 ;
     RECT  83.415 56.237 83.697 56.497 ;
     RECT  5.472 56.489 6.102 56.533 ;
     RECT  6.84 56.497 7.074 56.533 ;
     RECT  10.728 56.569 10.746 56.641 ;
     RECT  10.728 56.641 10.818 56.669 ;
     RECT  0.108 56.395 0.198 56.684 ;
     RECT  40.215 56.129 40.662 56.759 ;
     RECT  83.232 56.497 83.697 56.813 ;
     RECT  7.815 56.227 8.91 56.911 ;
     RECT  44.784 56.491 46.854 56.911 ;
     RECT  44.784 56.911 47.286 56.939 ;
     RECT  4.068 56.489 4.698 57.001 ;
     RECT  7.815 56.911 9.234 57.001 ;
     RECT  46.728 56.939 47.286 57.001 ;
     RECT  5.472 56.533 7.074 57.037 ;
     RECT  7.815 57.001 9.27 57.037 ;
     RECT  42.696 56.489 42.786 57.073 ;
     RECT  43.524 56.371 43.866 57.073 ;
     RECT  46.728 57.001 47.538 57.101 ;
     RECT  81.504 56.839 81.522 57.101 ;
     RECT  42.696 57.073 43.866 57.109 ;
     RECT  44.784 56.939 45.897 57.109 ;
     RECT  5.472 57.037 9.306 57.149 ;
     RECT  2.304 56.327 2.97 57.163 ;
     RECT  2.268 57.163 2.97 57.181 ;
     RECT  3.708 57.001 4.698 57.181 ;
     RECT  83.415 56.813 83.697 57.181 ;
     RECT  42.696 57.109 45.897 57.271 ;
     RECT  84.924 56.429 85.662 57.293 ;
     RECT  83.415 57.181 83.826 57.307 ;
     RECT  84.924 57.293 85.626 57.307 ;
     RECT  2.268 57.181 4.698 57.335 ;
     RECT  5.472 57.149 9.198 57.389 ;
     RECT  83.415 57.307 85.626 57.389 ;
     RECT  2.304 57.335 4.698 57.415 ;
     RECT  5.472 57.389 9.126 57.415 ;
     RECT  46.764 57.101 47.538 57.443 ;
     RECT  47.484 57.443 47.538 57.451 ;
     RECT  2.304 57.415 9.126 57.479 ;
     RECT  47.484 57.451 47.574 57.479 ;
     RECT  83.415 57.389 85.59 57.485 ;
     RECT  2.304 57.479 9.09 57.569 ;
     RECT  47.556 57.479 47.574 57.569 ;
     RECT  0.144 56.684 0.162 57.581 ;
     RECT  2.304 57.569 8.154 57.605 ;
     RECT  42.624 57.271 45.897 57.649 ;
     RECT  41.472 57.343 41.49 57.685 ;
     RECT  42.372 57.649 45.897 57.713 ;
     RECT  3.528 57.605 8.154 57.749 ;
     RECT  41.4 57.685 41.49 57.749 ;
     RECT  0.216 57.595 0.234 57.773 ;
     RECT  42.372 57.713 43.686 57.839 ;
     RECT  3.528 57.749 5.814 57.875 ;
     RECT  10.8 56.669 10.818 57.947 ;
     RECT  38.808 57.883 38.826 57.983 ;
     RECT  2.304 57.605 2.79 58.013 ;
     RECT  4.536 57.875 5.814 58.019 ;
     RECT  9 57.569 9.09 58.019 ;
     RECT  46.728 57.847 46.746 58.019 ;
     RECT  4.536 58.019 4.554 58.109 ;
     RECT  5.652 58.019 5.814 58.109 ;
     RECT  6.588 57.749 8.154 58.109 ;
     RECT  9.072 58.019 9.09 58.109 ;
     RECT  41.4 57.749 41.418 58.109 ;
     RECT  42.372 57.839 43.614 58.109 ;
     RECT  81 57.847 81.018 58.117 ;
     RECT  2.304 58.013 2.697 58.145 ;
     RECT  3.528 57.875 3.618 58.145 ;
     RECT  5.652 58.109 5.67 58.145 ;
     RECT  6.66 58.109 8.154 58.145 ;
     RECT  44.604 57.713 45.897 58.145 ;
     RECT  7.056 58.145 8.154 58.157 ;
     RECT  85.5 57.485 85.59 58.157 ;
     RECT  80.964 58.117 81.018 58.205 ;
     RECT  3.528 58.145 3.546 58.253 ;
     RECT  7.308 58.157 8.154 58.253 ;
     RECT  83.415 57.485 84.51 58.253 ;
     RECT  45.108 58.145 45.897 58.289 ;
     RECT  86.22 58.171 86.238 58.349 ;
     RECT  46.8 58.261 46.818 58.351 ;
     RECT  42.372 58.109 43.362 58.379 ;
     RECT  46.8 58.351 46.89 58.379 ;
     RECT  42.408 58.379 43.362 58.415 ;
     RECT  81 58.205 81.018 58.445 ;
     RECT  42.408 58.415 42.786 58.523 ;
     RECT  42.408 58.523 42.426 58.541 ;
     RECT  46.872 58.379 46.89 58.559 ;
     RECT  84.924 58.261 85.05 58.637 ;
     RECT  7.308 58.253 8.097 58.685 ;
     RECT  84.96 58.637 85.05 58.733 ;
     RECT  85.032 58.733 85.05 58.829 ;
     RECT  83.415 58.253 83.697 59.701 ;
     RECT  83.415 59.701 83.754 59.737 ;
     RECT  80.964 59.701 80.982 59.845 ;
     RECT  83.268 59.737 83.754 59.845 ;
     RECT  84.492 59.773 84.51 59.845 ;
     RECT  78.015 55.049 78.297 59.881 ;
     RECT  79.2 59.701 80.19 59.881 ;
     RECT  80.964 59.845 81.702 59.881 ;
     RECT  83.268 59.845 84.51 59.881 ;
     RECT  80.964 59.881 82.53 59.971 ;
     RECT  83.268 59.881 84.942 59.971 ;
     RECT  78.015 59.881 80.19 60.079 ;
     RECT  80.964 59.971 84.942 60.079 ;
     RECT  4.608 60.151 4.77 60.269 ;
     RECT  61.815 52.889 62.097 60.277 ;
     RECT  72.615 2.413 72.897 60.277 ;
     RECT  3.816 59.851 3.834 60.305 ;
     RECT  2.415 58.145 2.697 60.331 ;
     RECT  78.015 60.079 84.942 60.349 ;
     RECT  4.608 60.269 4.626 60.377 ;
     RECT  61.02 60.241 61.038 60.377 ;
     RECT  61.815 60.277 62.118 60.377 ;
     RECT  0.54 60.151 0.558 60.461 ;
     RECT  13.215 44.249 13.497 60.511 ;
     RECT  24.015 44.249 24.297 60.511 ;
     RECT  34.815 44.249 35.097 60.511 ;
     RECT  45.615 58.289 45.897 60.511 ;
     RECT  59.04 60.421 59.058 60.511 ;
     RECT  77.436 60.349 85.446 60.511 ;
     RECT  51.015 56.093 51.297 60.523 ;
     RECT  56.415 55.049 56.697 60.547 ;
     RECT  76.068 60.421 76.086 60.547 ;
     RECT  75.96 60.547 76.086 60.583 ;
     RECT  58.68 60.511 59.058 60.611 ;
     RECT  50.832 60.523 51.297 60.619 ;
     RECT  77.436 60.511 85.482 60.619 ;
     RECT  75.744 60.583 76.086 60.655 ;
     RECT  53.964 60.619 54.09 60.656 ;
     RECT  55.836 60.547 56.697 60.719 ;
     RECT  0.108 60.691 0.126 60.749 ;
     RECT  77.076 60.619 85.482 60.808 ;
     RECT  75.564 60.655 76.086 60.817 ;
     RECT  57.6 60.781 57.618 60.845 ;
     RECT  50.724 60.619 51.297 60.893 ;
     RECT  54.072 60.656 54.09 60.893 ;
     RECT  58.428 60.817 58.446 60.907 ;
     RECT  58.14 60.907 58.446 60.917 ;
     RECT  58.14 60.917 58.266 60.953 ;
     RECT  72.615 60.277 72.99 60.953 ;
     RECT  75.492 60.817 76.086 60.961 ;
     RECT  76.968 60.808 85.482 60.961 ;
     RECT  34.704 60.511 35.097 61.045 ;
     RECT  54.936 60.619 55.026 61.051 ;
     RECT  2.304 60.331 2.697 61.079 ;
     RECT  34.632 61.045 35.097 61.085 ;
     RECT  54.72 61.051 55.026 61.087 ;
     RECT  13.104 60.511 13.497 61.088 ;
     RECT  23.904 60.511 24.297 61.088 ;
     RECT  45.504 60.511 45.897 61.088 ;
     RECT  54.72 61.087 55.17 61.133 ;
     RECT  75.492 60.961 85.482 61.159 ;
     RECT  54.72 61.133 54.738 61.181 ;
     RECT  59.364 61.123 59.382 61.181 ;
     RECT  52.74 61.189 52.758 61.229 ;
     RECT  75.276 61.159 85.482 61.349 ;
     RECT  58.14 60.953 58.158 61.421 ;
     RECT  61.02 61.321 61.038 61.493 ;
     RECT  83.016 61.349 85.482 61.501 ;
     RECT  0.108 61.483 0.126 61.579 ;
     RECT  61.815 60.377 62.097 61.591 ;
     RECT  83.016 61.501 85.518 61.619 ;
     RECT  0.108 61.579 0.162 61.691 ;
     RECT  61.452 61.591 62.097 61.763 ;
     RECT  83.052 61.619 85.518 61.805 ;
     RECT  0.108 61.691 0.126 61.925 ;
     RECT  75.276 61.349 82.278 61.925 ;
     RECT  75.312 61.925 82.278 62.093 ;
     RECT  75.42 62.093 82.278 62.401 ;
     RECT  83.052 61.805 85.482 62.401 ;
     RECT  75.42 62.401 85.482 62.539 ;
     RECT  75.42 62.539 85.518 62.609 ;
     RECT  75.42 62.609 85.482 62.969 ;
     RECT  80.892 62.969 85.482 63.149 ;
     RECT  83.016 63.149 85.482 63.239 ;
     RECT  86.292 61.699 86.31 63.341 ;
     RECT  80.892 63.149 82.278 64.021 ;
     RECT  83.052 63.239 85.482 64.021 ;
     RECT  80.892 64.021 85.482 64.049 ;
     RECT  75.42 62.969 80.118 64.193 ;
     RECT  76.248 64.193 80.118 64.229 ;
     RECT  80.928 64.049 85.482 64.319 ;
     RECT  84.816 64.319 85.482 64.685 ;
     RECT  76.248 64.229 80.046 65.011 ;
     RECT  80.928 64.319 83.898 65.165 ;
     RECT  86.292 64.075 86.31 65.165 ;
     RECT  76.248 65.011 80.154 65.209 ;
     RECT  76.248 65.209 80.19 65.245 ;
     RECT  80.928 65.165 83.79 65.245 ;
     RECT  84.852 64.685 85.482 65.611 ;
     RECT  84.816 65.611 85.482 65.707 ;
     RECT  84.78 65.707 85.482 65.803 ;
     RECT  76.248 65.245 83.79 66.125 ;
     RECT  86.292 65.995 86.31 66.187 ;
     RECT  75.42 64.193 75.438 66.317 ;
     RECT  86.256 66.187 86.31 66.821 ;
     RECT  76.248 66.125 83.754 66.857 ;
     RECT  76.248 66.857 83.697 66.929 ;
     RECT  76.428 66.929 83.697 67.019 ;
     RECT  79.2 67.019 83.697 67.127 ;
     RECT  76.608 67.019 78.462 67.181 ;
     RECT  84.744 65.803 85.482 67.199 ;
     RECT  79.2 67.127 81.63 67.289 ;
     RECT  82.44 67.127 83.697 67.289 ;
     RECT  85.428 67.199 85.482 67.289 ;
     RECT  86.256 66.821 86.274 67.397 ;
     RECT  79.2 67.289 81.522 67.469 ;
     RECT  51.015 60.893 51.297 67.531 ;
     RECT  56.415 60.719 56.697 67.531 ;
     RECT  67.215 55.049 67.497 67.531 ;
     RECT  80.676 67.469 81.522 67.559 ;
     RECT  85.428 67.289 85.446 67.559 ;
     RECT  56.304 67.531 56.697 67.568 ;
     RECT  67.104 67.531 67.497 67.568 ;
     RECT  79.2 67.469 79.794 67.631 ;
     RECT  74.664 67.531 74.682 67.661 ;
     RECT  79.2 67.631 79.218 67.661 ;
     RECT  80.676 67.559 80.694 67.739 ;
     RECT  82.692 67.289 83.697 67.739 ;
     RECT  51.015 67.531 51.966 67.915 ;
     RECT  50.832 67.915 51.966 68.099 ;
     RECT  50.832 68.099 51.297 68.107 ;
     RECT  76.608 67.181 78.354 68.107 ;
     RECT  76.464 68.107 78.354 68.243 ;
     RECT  50.76 68.107 51.297 68.369 ;
     RECT  76.464 68.243 78.297 68.395 ;
     RECT  2.415 61.079 2.697 68.521 ;
     RECT  2.415 68.521 3.15 68.611 ;
     RECT  76.032 68.395 78.297 68.639 ;
     RECT  0.036 68.377 0.054 68.731 ;
     RECT  5.904 68.521 5.922 68.731 ;
     RECT  2.415 68.611 3.222 68.755 ;
     RECT  40.215 56.759 40.497 68.755 ;
     RECT  41.616 68.611 41.634 68.755 ;
     RECT  5.436 68.731 5.922 68.791 ;
     RECT  2.304 68.755 3.222 68.819 ;
     RECT  6.696 68.755 6.714 68.917 ;
     RECT  3.924 68.917 3.942 68.923 ;
     RECT  4.86 68.791 5.922 68.923 ;
     RECT  76.608 68.639 78.297 68.945 ;
     RECT  0.036 68.731 0.162 68.953 ;
     RECT  3.924 68.923 5.922 68.957 ;
     RECT  0.036 68.953 0.558 69.005 ;
     RECT  2.304 68.819 2.697 69.163 ;
     RECT  4.464 68.957 5.922 69.215 ;
     RECT  6.696 68.917 7.074 69.223 ;
     RECT  7.815 58.685 8.097 69.223 ;
     RECT  6.696 69.223 8.097 69.259 ;
     RECT  42.444 68.917 42.462 69.295 ;
     RECT  5.04 69.215 5.922 69.331 ;
     RECT  6.66 69.259 8.097 69.331 ;
     RECT  42.444 69.295 42.858 69.331 ;
     RECT  5.04 69.331 8.097 69.449 ;
     RECT  40.215 68.755 41.634 69.449 ;
     RECT  6.66 69.449 8.097 69.457 ;
     RECT  2.268 69.163 2.697 69.485 ;
     RECT  6.66 69.457 8.406 69.485 ;
     RECT  38.772 69.295 38.79 69.485 ;
     RECT  7.2 69.485 8.406 69.533 ;
     RECT  42.444 69.331 43.254 69.601 ;
     RECT  43.992 69.151 44.01 69.601 ;
     RECT  5.4 69.449 5.67 69.719 ;
     RECT  7.2 69.533 8.097 69.719 ;
     RECT  41.616 69.449 41.634 69.989 ;
     RECT  0.036 69.005 0.054 72.379 ;
     RECT  0.036 72.379 0.126 72.413 ;
     RECT  0.108 72.413 0.126 72.557 ;
     RECT  42.444 69.601 44.01 73.229 ;
     RECT  76.608 68.945 76.734 73.571 ;
     RECT  29.415 52.313 29.697 74.047 ;
     RECT  29.415 74.047 29.79 74.093 ;
     RECT  42.84 73.229 44.01 74.551 ;
     RECT  5.4 69.719 5.418 75.029 ;
     RECT  83.415 67.739 83.697 75.091 ;
     RECT  42.84 74.551 44.19 75.119 ;
     RECT  42.948 75.119 44.19 75.485 ;
     RECT  42.948 75.485 43.074 75.533 ;
     RECT  43.848 75.485 44.19 75.725 ;
     RECT  44.064 75.725 44.19 75.821 ;
     RECT  86.22 75.451 86.238 75.883 ;
     RECT  83.415 75.091 83.826 75.901 ;
     RECT  86.22 75.883 86.31 75.929 ;
     RECT  42.948 75.533 42.966 75.965 ;
     RECT  44.064 75.821 44.082 75.965 ;
     RECT  86.22 75.929 86.238 75.965 ;
     RECT  83.415 75.901 83.862 76.109 ;
     RECT  0.108 75.499 0.126 76.235 ;
     RECT  77.616 68.945 78.297 76.351 ;
     RECT  0.108 77.419 0.126 77.515 ;
     RECT  77.616 76.351 78.642 77.701 ;
     RECT  81.504 67.559 81.522 77.701 ;
     RECT  83.415 76.109 83.697 77.791 ;
     RECT  77.508 77.701 78.642 77.827 ;
     RECT  0.108 77.515 0.198 77.995 ;
     RECT  85.5 77.971 85.518 78.029 ;
     RECT  82.62 77.971 82.638 78.089 ;
     RECT  0.108 77.995 0.234 78.091 ;
     RECT  77.508 77.827 79.362 78.091 ;
     RECT  83.415 77.791 84.402 78.125 ;
     RECT  0.108 78.091 0.27 78.187 ;
     RECT  85.464 78.061 85.482 78.187 ;
     RECT  81.252 77.701 81.522 78.205 ;
     RECT  13.215 61.088 13.497 78.232 ;
     RECT  24.015 61.088 24.297 78.232 ;
     RECT  34.815 61.085 35.097 78.232 ;
     RECT  45.615 61.088 45.897 78.232 ;
     RECT  56.415 67.568 56.697 78.232 ;
     RECT  67.215 67.568 67.497 78.232 ;
     RECT  2.415 69.485 2.697 78.241 ;
     RECT  84.888 78.187 85.482 78.317 ;
     RECT  81.072 78.205 81.522 78.359 ;
     RECT  84.888 78.317 84.906 78.359 ;
     RECT  81.072 78.359 81.09 78.413 ;
     RECT  77.508 78.091 79.47 78.418 ;
     RECT  2.304 78.241 2.697 78.809 ;
     RECT  13.104 78.232 13.497 78.809 ;
     RECT  23.904 78.232 24.297 78.809 ;
     RECT  34.704 78.232 35.097 78.809 ;
     RECT  45.504 78.232 45.897 78.809 ;
     RECT  56.304 78.232 56.697 78.809 ;
     RECT  67.104 78.232 67.497 78.809 ;
     RECT  0.108 78.187 0.306 78.859 ;
     RECT  0.108 78.859 0.342 78.899 ;
     RECT  0.108 78.899 0.306 79.205 ;
     RECT  77.508 78.418 79.362 79.447 ;
     RECT  80.172 79.285 80.19 79.447 ;
     RECT  77.508 79.447 80.19 79.591 ;
     RECT  81.36 79.519 81.378 79.591 ;
     RECT  74.664 79.591 74.682 79.681 ;
     RECT  76.608 73.571 76.662 79.681 ;
     RECT  77.472 79.591 80.19 79.681 ;
     RECT  0.18 79.205 0.306 79.709 ;
     RECT  0.252 79.709 0.306 79.745 ;
     RECT  74.664 79.681 74.754 79.745 ;
     RECT  81 79.591 81.378 79.753 ;
     RECT  82.44 79.321 82.458 79.753 ;
     RECT  74.736 79.745 74.754 79.781 ;
     RECT  76.608 79.681 80.19 79.979 ;
     RECT  78.015 79.979 80.19 80.131 ;
     RECT  81 79.753 82.458 80.131 ;
     RECT  83.415 78.125 83.697 80.365 ;
     RECT  83.34 80.365 83.697 80.563 ;
     RECT  84.924 79.411 84.942 80.563 ;
     RECT  86.112 80.491 86.13 80.621 ;
     RECT  78.015 80.131 82.458 80.671 ;
     RECT  83.34 80.563 84.942 80.671 ;
     RECT  78.015 80.671 84.942 80.789 ;
     RECT  0.288 79.745 0.306 80.825 ;
     RECT  76.608 79.979 76.914 80.897 ;
     RECT  80.82 80.789 84.942 80.909 ;
     RECT  78.015 80.789 80.082 80.941 ;
     RECT  77.832 80.941 80.082 80.957 ;
     RECT  80.82 80.909 83.754 80.957 ;
     RECT  77.832 80.957 79.902 81.059 ;
     RECT  84.78 80.909 84.942 81.163 ;
     RECT  78.012 81.059 79.758 81.329 ;
     RECT  81.072 80.957 83.754 81.329 ;
     RECT  81.072 81.329 81.198 81.679 ;
     RECT  82.224 81.329 83.754 81.679 ;
     RECT  84.78 81.163 85.518 81.679 ;
     RECT  80.784 81.679 81.198 81.715 ;
     RECT  82.224 81.679 85.518 81.779 ;
     RECT  76.608 80.897 76.626 81.869 ;
     RECT  78.015 81.329 79.758 81.869 ;
     RECT  82.224 81.779 85.482 81.869 ;
     RECT  79.056 81.869 79.758 81.905 ;
     RECT  82.224 81.869 83.754 81.905 ;
     RECT  86.292 81.643 86.31 81.931 ;
     RECT  74.664 81.877 74.682 81.977 ;
     RECT  80.568 81.715 81.198 82.013 ;
     RECT  79.2 81.905 79.758 82.019 ;
     RECT  82.224 81.905 83.697 82.049 ;
     RECT  84.816 81.869 84.834 82.049 ;
     RECT  79.596 82.019 79.758 82.139 ;
     RECT  80.568 82.013 80.946 82.139 ;
     RECT  82.224 82.049 82.674 82.139 ;
     RECT  2.415 78.809 2.697 82.147 ;
     RECT  80.928 82.139 80.946 82.175 ;
     RECT  79.74 82.139 79.758 82.211 ;
     RECT  86.256 81.931 86.31 82.211 ;
     RECT  2.415 82.147 2.79 82.219 ;
     RECT  86.256 82.211 86.274 82.247 ;
     RECT  2.415 82.219 2.826 82.603 ;
     RECT  2.304 82.603 2.826 82.985 ;
     RECT  2.34 82.985 2.826 83.219 ;
     RECT  78.015 81.869 78.297 83.227 ;
     RECT  2.34 83.219 2.697 83.255 ;
     RECT  78.015 83.227 78.462 83.641 ;
     RECT  77.184 82.021 77.202 83.669 ;
     RECT  83.415 82.049 83.697 83.755 ;
     RECT  78.015 83.641 78.606 83.759 ;
     RECT  78.015 83.759 78.462 83.795 ;
     RECT  83.415 83.755 83.79 83.795 ;
     RECT  2.415 83.255 2.697 83.987 ;
     RECT  7.815 69.719 8.097 83.987 ;
     RECT  13.215 78.809 13.497 83.987 ;
     RECT  18.615 2.413 18.897 83.987 ;
     RECT  24.015 78.809 24.297 83.987 ;
     RECT  29.415 74.093 29.697 83.987 ;
     RECT  34.815 78.809 35.097 83.987 ;
     RECT  40.215 69.449 40.497 83.987 ;
     RECT  45.615 78.809 45.897 83.987 ;
     RECT  51.015 68.369 51.297 83.987 ;
     RECT  56.415 78.809 56.697 83.987 ;
     RECT  61.815 61.763 62.097 83.987 ;
     RECT  67.215 78.809 67.497 83.987 ;
     RECT  72.615 60.953 72.897 83.987 ;
     RECT  78.015 83.795 78.297 83.987 ;
     RECT  83.415 83.795 83.697 83.987 ;
     RECT  2.415 83.987 2.505 84.257 ;
     RECT  7.815 83.987 7.905 84.257 ;
     RECT  13.215 83.987 13.305 84.257 ;
     RECT  18.615 83.987 18.705 84.257 ;
     RECT  24.015 83.987 24.105 84.257 ;
     RECT  29.415 83.987 29.505 84.257 ;
     RECT  34.815 83.987 34.905 84.257 ;
     RECT  40.215 83.987 40.305 84.257 ;
     RECT  45.615 83.987 45.705 84.257 ;
     RECT  51.015 83.987 51.105 84.257 ;
     RECT  56.415 83.987 56.505 84.257 ;
     RECT  61.815 83.987 61.905 84.257 ;
     RECT  67.215 83.987 67.305 84.257 ;
     RECT  72.615 83.987 72.705 84.257 ;
     RECT  78.015 83.987 78.105 84.257 ;
     RECT  83.415 83.987 83.505 84.257 ;
    LAYER M4 ;
     RECT  0.025 72.384 0.06 72.408 ;
     RECT  0.06 60.336 0.137 61.8 ;
     RECT  0.06 72.384 0.137 72.552 ;
     RECT  0.06 75.504 0.137 75.528 ;
     RECT  0.06 77.424 0.137 78.888 ;
     RECT  0.06 32.688 0.179 58.536 ;
     RECT  0.137 77.52 0.209 78.888 ;
     RECT  0.209 77.616 0.353 78.888 ;
     RECT  0.179 32.688 0.569 58.152 ;
     RECT  0.569 32.784 2.408 58.152 ;
     RECT  0.137 60.336 2.408 61.704 ;
     RECT  0.06 68.688 2.408 69.288 ;
     RECT  0.06 74.064 2.408 74.088 ;
     RECT  0.353 77.616 2.408 78.792 ;
     RECT  0.06 82.512 2.408 82.824 ;
     RECT  2.408 2.148 2.512 84.252 ;
     RECT  2.512 2.418 2.704 83.982 ;
     RECT  2.704 68.688 2.839 69.288 ;
     RECT  2.704 39.744 2.867 58.152 ;
     RECT  2.704 60.528 3.805 61.704 ;
     RECT  2.867 39.744 4.097 58.008 ;
     RECT  4.097 56.304 4.133 58.008 ;
     RECT  4.097 39.744 4.529 55.272 ;
     RECT  4.529 39.744 4.637 55.176 ;
     RECT  2.704 32.784 4.993 38.76 ;
     RECT  4.637 39.744 4.993 55.128 ;
     RECT  4.993 32.784 5.125 55.128 ;
     RECT  4.133 56.352 5.177 58.008 ;
     RECT  2.839 68.736 5.465 69.288 ;
     RECT  5.125 32.736 5.573 55.128 ;
     RECT  5.573 32.736 5.609 39.864 ;
     RECT  5.465 68.928 5.641 69.288 ;
     RECT  5.573 41.088 5.677 55.128 ;
     RECT  5.177 56.352 5.717 57.912 ;
     RECT  5.609 32.736 5.725 37.608 ;
     RECT  5.725 32.736 5.753 34.2 ;
     RECT  3.805 59.856 5.795 61.704 ;
     RECT  5.753 32.736 6.113 34.056 ;
     RECT  5.609 38.736 6.113 39.864 ;
     RECT  5.717 56.4 6.113 57.912 ;
     RECT  6.113 39.792 6.149 39.864 ;
     RECT  5.677 41.088 6.761 55.176 ;
     RECT  6.761 41.088 6.833 55.128 ;
     RECT  6.149 39.84 6.865 39.864 ;
     RECT  6.113 56.976 7.045 57.912 ;
     RECT  6.113 38.736 7.117 38.76 ;
     RECT  6.865 39.84 7.117 40.104 ;
     RECT  7.045 56.976 7.285 58.152 ;
     RECT  7.285 56.976 7.297 58.344 ;
     RECT  5.641 68.928 7.333 69.576 ;
     RECT  6.113 33.36 7.808 34.056 ;
     RECT  5.725 35.52 7.808 37.608 ;
     RECT  7.117 38.736 7.808 40.104 ;
     RECT  6.833 41.088 7.808 54.504 ;
     RECT  7.765 55.776 7.808 55.8 ;
     RECT  7.297 56.976 7.808 58.68 ;
     RECT  5.795 60.528 7.808 61.704 ;
     RECT  7.333 68.112 7.808 69.576 ;
     RECT  2.704 74.064 7.808 74.088 ;
     RECT  2.704 77.616 7.808 78.792 ;
     RECT  7.808 2.148 7.912 84.252 ;
     RECT  7.912 2.418 8.104 83.982 ;
     RECT  8.104 33.36 8.165 33.384 ;
     RECT  8.104 39.312 8.165 39.336 ;
     RECT  8.104 41.232 8.165 44.472 ;
     RECT  8.104 55.776 8.165 55.8 ;
     RECT  8.104 36.48 8.201 37.08 ;
     RECT  8.104 49.488 8.201 49.512 ;
     RECT  8.104 46.8 8.237 47.112 ;
     RECT  8.165 41.376 8.309 44.472 ;
     RECT  8.237 46.848 8.417 47.112 ;
     RECT  8.104 69.504 8.417 69.528 ;
     RECT  8.201 36.48 8.489 36.84 ;
     RECT  8.417 46.992 8.489 47.112 ;
     RECT  8.489 36.48 9.065 36.552 ;
     RECT  9.065 36.48 9.137 36.504 ;
     RECT  8.104 51.168 9.173 52.2 ;
     RECT  9.173 51.168 9.209 51.192 ;
     RECT  8.489 47.088 9.245 47.112 ;
     RECT  8.104 57.024 9.281 57.912 ;
     RECT  9.281 57.12 9.317 57.912 ;
     RECT  8.309 41.376 13.208 44.424 ;
     RECT  9.173 52.176 13.208 52.2 ;
     RECT  9.317 57.888 13.208 57.912 ;
     RECT  8.104 60.528 13.208 61.704 ;
     RECT  8.104 68.112 13.208 68.136 ;
     RECT  8.104 74.064 13.208 74.088 ;
     RECT  8.104 77.616 13.208 78.792 ;
     RECT  13.208 2.148 13.312 84.252 ;
     RECT  13.312 2.418 13.504 83.982 ;
     RECT  13.504 41.376 18.608 44.424 ;
     RECT  13.504 52.176 18.608 52.2 ;
     RECT  13.504 57.888 18.608 57.912 ;
     RECT  13.504 60.528 18.608 61.704 ;
     RECT  13.504 68.112 18.608 68.136 ;
     RECT  13.504 74.064 18.608 74.088 ;
     RECT  13.504 77.616 18.608 78.792 ;
     RECT  18.608 2.148 18.712 84.252 ;
     RECT  18.712 2.418 18.904 83.982 ;
     RECT  18.904 41.376 24.008 44.424 ;
     RECT  18.904 52.176 24.008 52.2 ;
     RECT  18.904 57.888 24.008 57.912 ;
     RECT  18.904 60.528 24.008 61.704 ;
     RECT  18.904 68.112 24.008 68.136 ;
     RECT  18.904 74.064 24.008 74.088 ;
     RECT  18.904 77.616 24.008 78.792 ;
     RECT  24.008 2.148 24.112 84.252 ;
     RECT  24.112 2.418 24.304 83.982 ;
     RECT  24.304 52.176 28.825 52.2 ;
     RECT  24.304 41.376 29.408 44.424 ;
     RECT  28.825 52.176 29.408 52.296 ;
     RECT  24.304 57.888 29.408 57.912 ;
     RECT  24.304 60.528 29.408 61.704 ;
     RECT  24.304 68.112 29.408 68.136 ;
     RECT  24.304 74.064 29.408 74.088 ;
     RECT  24.304 77.616 29.408 78.792 ;
     RECT  29.408 2.148 29.512 84.252 ;
     RECT  29.512 2.418 29.704 83.982 ;
     RECT  29.704 74.064 29.801 74.088 ;
     RECT  29.704 41.376 34.808 44.424 ;
     RECT  29.704 52.272 34.808 52.296 ;
     RECT  29.704 57.888 34.808 57.912 ;
     RECT  29.704 60.528 34.808 61.704 ;
     RECT  29.704 68.112 34.808 68.136 ;
     RECT  29.704 77.616 34.808 78.792 ;
     RECT  34.808 2.148 34.912 84.252 ;
     RECT  34.912 2.418 35.104 83.982 ;
     RECT  35.104 41.376 40.208 44.424 ;
     RECT  35.104 52.272 40.208 52.296 ;
     RECT  35.104 57.888 40.208 57.912 ;
     RECT  35.104 60.528 40.208 61.704 ;
     RECT  35.104 68.112 40.208 68.136 ;
     RECT  35.104 77.616 40.208 78.792 ;
     RECT  40.208 2.148 40.312 84.252 ;
     RECT  40.312 2.418 40.504 83.982 ;
     RECT  40.504 52.272 42.001 52.296 ;
     RECT  40.504 57.888 42.397 57.912 ;
     RECT  42.325 34.368 42.437 34.392 ;
     RECT  42.397 57.888 42.509 58.536 ;
     RECT  40.504 36.528 42.725 36.552 ;
     RECT  42.757 46.752 42.793 46.776 ;
     RECT  42.721 49.824 42.865 49.848 ;
     RECT  42.793 46.608 42.905 46.776 ;
     RECT  42.905 46.608 42.977 46.632 ;
     RECT  43.045 75.504 43.117 75.528 ;
     RECT  42.001 52.272 43.297 53.016 ;
     RECT  43.081 54.336 43.297 54.36 ;
     RECT  42.865 37.44 43.369 37.464 ;
     RECT  40.504 38.928 43.405 38.952 ;
     RECT  43.297 51.456 43.405 54.36 ;
     RECT  43.153 48.768 43.477 48.792 ;
     RECT  42.509 58.512 43.513 58.536 ;
     RECT  40.504 68.112 43.621 68.136 ;
     RECT  43.513 57.84 43.667 58.536 ;
     RECT  43.405 51.456 43.729 54.408 ;
     RECT  43.117 75.456 43.837 75.528 ;
     RECT  43.261 46.224 43.913 46.248 ;
     RECT  43.729 51.456 43.981 54.936 ;
     RECT  43.837 75.456 44.053 75.72 ;
     RECT  40.504 40.656 44.237 44.424 ;
     RECT  44.237 44.064 44.989 44.424 ;
     RECT  43.801 35.184 45.608 35.208 ;
     RECT  43.369 37.44 45.608 37.896 ;
     RECT  43.405 38.928 45.608 39.528 ;
     RECT  44.237 40.656 45.608 43.08 ;
     RECT  44.989 44.064 45.608 44.952 ;
     RECT  43.477 48.24 45.608 48.792 ;
     RECT  42.865 49.824 45.608 50.376 ;
     RECT  43.981 51.456 45.608 55.176 ;
     RECT  43.667 58.512 45.608 58.536 ;
     RECT  40.504 60.528 45.608 61.704 ;
     RECT  43.621 67.92 45.608 68.136 ;
     RECT  44.053 75.456 45.608 75.96 ;
     RECT  40.504 77.616 45.608 78.792 ;
     RECT  45.608 2.148 45.712 84.252 ;
     RECT  45.712 2.418 45.904 83.982 ;
     RECT  45.904 40.656 46.397 44.712 ;
     RECT  46.397 40.656 46.541 44.424 ;
     RECT  45.904 56.496 46.757 56.52 ;
     RECT  45.904 67.92 50.869 68.136 ;
     RECT  45.904 35.184 51.008 35.208 ;
     RECT  45.904 37.44 51.008 37.896 ;
     RECT  45.904 38.928 51.008 39.528 ;
     RECT  46.541 40.656 51.008 44.376 ;
     RECT  45.904 48.144 51.008 50.28 ;
     RECT  45.904 51.456 51.008 55.176 ;
     RECT  45.904 58.512 51.008 58.536 ;
     RECT  45.904 60.528 51.008 61.704 ;
     RECT  50.869 67.68 51.008 68.136 ;
     RECT  45.904 75.456 51.008 75.96 ;
     RECT  45.904 77.616 51.008 78.792 ;
     RECT  51.008 2.148 51.112 84.252 ;
     RECT  51.112 2.418 51.304 83.982 ;
     RECT  51.304 67.536 51.977 67.704 ;
     RECT  51.304 60.624 54.965 61.704 ;
     RECT  51.304 35.184 56.408 35.208 ;
     RECT  51.304 37.44 56.408 37.896 ;
     RECT  51.304 38.928 56.408 39.528 ;
     RECT  51.304 40.656 56.408 44.376 ;
     RECT  51.304 48.144 56.408 50.28 ;
     RECT  51.304 51.456 56.408 55.176 ;
     RECT  51.304 58.512 56.408 58.536 ;
     RECT  54.965 60.816 56.408 61.704 ;
     RECT  51.977 67.536 56.408 67.56 ;
     RECT  51.304 75.456 56.408 75.96 ;
     RECT  51.304 77.616 56.408 78.792 ;
     RECT  56.408 2.148 56.512 84.252 ;
     RECT  56.512 2.418 56.704 83.982 ;
     RECT  56.704 60.816 57.629 61.704 ;
     RECT  57.629 60.912 58.277 61.704 ;
     RECT  58.277 61.152 59.393 61.704 ;
     RECT  56.704 35.184 61.808 35.208 ;
     RECT  56.704 37.44 61.808 37.896 ;
     RECT  56.704 38.928 61.808 39.528 ;
     RECT  56.704 40.656 61.808 44.376 ;
     RECT  56.704 48.144 61.808 50.28 ;
     RECT  56.704 51.456 61.808 55.176 ;
     RECT  56.704 58.512 61.808 58.536 ;
     RECT  59.393 61.68 61.808 61.704 ;
     RECT  56.704 67.536 61.808 67.56 ;
     RECT  56.704 75.456 61.808 75.96 ;
     RECT  56.704 77.616 61.808 78.792 ;
     RECT  61.808 2.148 61.912 84.252 ;
     RECT  61.912 2.418 62.104 83.982 ;
     RECT  62.104 35.184 67.208 35.208 ;
     RECT  62.104 37.44 67.208 37.896 ;
     RECT  62.104 38.928 67.208 39.528 ;
     RECT  62.104 40.656 67.208 44.376 ;
     RECT  62.104 48.144 67.208 50.28 ;
     RECT  62.104 51.456 67.208 55.176 ;
     RECT  62.104 58.512 67.208 58.536 ;
     RECT  62.104 61.68 67.208 61.704 ;
     RECT  62.104 67.536 67.208 67.56 ;
     RECT  62.104 75.456 67.208 75.96 ;
     RECT  62.104 77.616 67.208 78.792 ;
     RECT  67.208 2.148 67.312 84.252 ;
     RECT  67.312 2.418 67.504 83.982 ;
     RECT  67.504 35.184 72.608 35.208 ;
     RECT  67.504 37.44 72.608 37.896 ;
     RECT  67.504 38.928 72.608 39.528 ;
     RECT  67.504 40.656 72.608 44.376 ;
     RECT  67.504 48.144 72.608 50.28 ;
     RECT  67.504 51.456 72.608 55.176 ;
     RECT  67.504 58.512 72.608 58.536 ;
     RECT  67.504 61.68 72.608 61.704 ;
     RECT  67.504 67.536 72.608 67.56 ;
     RECT  67.504 75.456 72.608 75.96 ;
     RECT  67.504 77.616 72.608 78.792 ;
     RECT  72.608 2.148 72.712 84.252 ;
     RECT  72.712 2.418 72.904 83.982 ;
     RECT  72.904 67.536 74.653 67.56 ;
     RECT  74.653 67.536 74.693 67.656 ;
     RECT  72.904 61.68 75.301 61.704 ;
     RECT  75.301 61.68 75.845 62.088 ;
     RECT  74.693 67.632 76.021 67.656 ;
     RECT  76.021 67.632 76.705 68.424 ;
     RECT  76.705 66.816 76.777 68.424 ;
     RECT  76.669 64.944 76.921 64.968 ;
     RECT  76.921 63.792 77.245 64.968 ;
     RECT  77.245 63.792 77.281 65.016 ;
     RECT  75.845 62.064 77.569 62.088 ;
     RECT  77.281 63.792 77.569 65.112 ;
     RECT  72.904 35.184 78.008 35.208 ;
     RECT  72.904 37.44 78.008 37.896 ;
     RECT  72.904 38.928 78.008 39.528 ;
     RECT  72.904 40.656 78.008 44.376 ;
     RECT  72.904 48.144 78.008 50.28 ;
     RECT  72.904 51.456 78.008 55.176 ;
     RECT  72.904 58.512 78.008 58.536 ;
     RECT  76.957 60.816 78.008 60.84 ;
     RECT  77.569 62.064 78.008 65.112 ;
     RECT  76.777 66.192 78.008 68.424 ;
     RECT  72.904 75.456 78.008 75.96 ;
     RECT  72.904 77.616 78.008 78.792 ;
     RECT  78.008 2.148 78.112 84.252 ;
     RECT  78.112 2.418 78.304 83.982 ;
     RECT  78.304 66.72 78.467 68.424 ;
     RECT  78.304 83.232 78.473 83.256 ;
     RECT  78.304 62.448 78.755 63.288 ;
     RECT  78.755 62.448 78.905 63 ;
     RECT  78.304 78.096 79.121 78.696 ;
     RECT  78.467 66.72 79.229 67.656 ;
     RECT  78.304 81.792 79.229 82.008 ;
     RECT  78.905 62.448 79.265 62.664 ;
     RECT  78.304 61.44 79.369 61.464 ;
     RECT  79.121 78.096 79.481 78.408 ;
     RECT  79.229 81.984 79.769 82.008 ;
     RECT  78.304 60.336 79.801 60.408 ;
     RECT  79.369 61.44 79.801 61.608 ;
     RECT  79.957 79.68 80.044 79.704 ;
     RECT  79.801 60.336 80.161 61.608 ;
     RECT  79.229 66.72 80.161 67.56 ;
     RECT  79.265 62.592 80.197 62.664 ;
     RECT  80.161 59.808 80.237 61.608 ;
     RECT  80.161 66.672 80.243 67.56 ;
     RECT  80.237 59.808 80.245 59.832 ;
     RECT  80.161 79.824 80.245 79.848 ;
     RECT  78.304 40.656 80.377 44.376 ;
     RECT  80.237 60.912 80.381 61.608 ;
     RECT  80.243 66.672 80.387 67.32 ;
     RECT  80.381 60.96 80.521 61.608 ;
     RECT  80.197 62.592 80.521 62.76 ;
     RECT  80.521 60.96 80.633 62.76 ;
     RECT  80.633 61.776 80.917 62.76 ;
     RECT  80.737 65.52 80.917 65.544 ;
     RECT  80.377 33.936 80.953 33.96 ;
     RECT  78.304 58.512 80.953 58.536 ;
     RECT  79.481 78.384 81.101 78.408 ;
     RECT  80.917 64.608 81.281 65.544 ;
     RECT  80.387 66.672 81.281 66.696 ;
     RECT  80.917 61.776 81.461 63.384 ;
     RECT  78.304 47.664 81.493 55.176 ;
     RECT  80.377 56.352 81.493 56.376 ;
     RECT  81.461 63.36 81.605 63.384 ;
     RECT  81.461 61.776 81.637 61.8 ;
     RECT  79.729 80.928 82.001 80.952 ;
     RECT  81.281 64.608 82.037 64.776 ;
     RECT  78.304 37.44 82.069 39.528 ;
     RECT  81.637 61.2 82.253 61.8 ;
     RECT  82.037 64.752 82.253 64.776 ;
     RECT  81.493 60.144 82.393 60.168 ;
     RECT  82.253 61.2 82.393 61.224 ;
     RECT  82.069 46.272 82.681 46.296 ;
     RECT  81.493 47.664 82.681 57.096 ;
     RECT  82.681 66.288 82.717 66.312 ;
     RECT  80.377 40.656 83.221 44.424 ;
     RECT  82.681 46.272 83.221 57.096 ;
     RECT  82.717 66 83.329 66.312 ;
     RECT  80.953 33.552 83.408 33.96 ;
     RECT  78.304 35.184 83.408 35.208 ;
     RECT  82.069 36.288 83.408 39.528 ;
     RECT  83.221 40.656 83.408 45 ;
     RECT  83.221 46.224 83.408 57.096 ;
     RECT  80.953 58.176 83.408 58.536 ;
     RECT  82.393 60.144 83.408 61.224 ;
     RECT  83.329 65.952 83.408 66.312 ;
     RECT  78.304 75.456 83.408 75.96 ;
     RECT  82.069 80.592 83.408 80.616 ;
     RECT  83.408 2.148 83.512 84.252 ;
     RECT  83.512 2.418 83.704 83.982 ;
     RECT  83.704 65.904 84.733 66.312 ;
     RECT  84.733 65.808 84.769 66.312 ;
     RECT  83.704 60.816 84.805 64.584 ;
     RECT  84.769 65.712 84.805 66.6 ;
     RECT  84.805 60.816 84.841 66.6 ;
     RECT  84.841 60.72 84.877 66.6 ;
     RECT  83.704 78.096 84.877 78.12 ;
     RECT  83.704 33.552 84.913 39.528 ;
     RECT  83.704 40.56 84.913 58.536 ;
     RECT  83.704 80.592 84.913 81.864 ;
     RECT  84.913 33.552 84.949 58.632 ;
     RECT  84.949 33.552 85.021 58.728 ;
     RECT  84.877 60.624 85.453 66.6 ;
     RECT  84.877 78.096 85.453 78.216 ;
     RECT  85.453 78.096 85.489 78.312 ;
     RECT  84.913 79.536 86.245 81.864 ;
     RECT  83.704 75.456 86.249 76.104 ;
     RECT  85.021 33.552 86.364 58.824 ;
     RECT  85.453 60.528 86.364 66.6 ;
     RECT  86.249 75.504 86.364 76.104 ;
     RECT  85.489 78 86.364 78.312 ;
     RECT  86.245 79.536 86.364 81.96 ;
     RECT  83.704 83.76 86.364 83.784 ;
    LAYER M5 ;
     RECT  2.4 2.137 2.52 2.151 ;
     RECT  7.8 2.137 7.92 2.151 ;
     RECT  13.2 2.137 13.32 2.151 ;
     RECT  18.6 2.137 18.72 2.151 ;
     RECT  24 2.137 24.12 2.151 ;
     RECT  29.4 2.137 29.52 2.151 ;
     RECT  34.8 2.137 34.92 2.151 ;
     RECT  40.2 2.137 40.32 2.151 ;
     RECT  45.6 2.137 45.72 2.151 ;
     RECT  51 2.137 51.12 2.151 ;
     RECT  56.4 2.137 56.52 2.151 ;
     RECT  61.8 2.137 61.92 2.151 ;
     RECT  67.2 2.137 67.32 2.151 ;
     RECT  72.6 2.137 72.72 2.151 ;
     RECT  78 2.137 78.12 2.151 ;
     RECT  83.4 2.137 83.52 2.151 ;
     RECT  5.136 32.725 5.16 34.165 ;
     RECT  2.4 2.151 2.712 34.453 ;
     RECT  2.304 34.453 2.712 34.643 ;
     RECT  5.136 34.165 5.688 34.835 ;
     RECT  5.136 34.835 5.16 35.845 ;
     RECT  5.136 35.845 5.592 36.611 ;
     RECT  2.4 34.643 2.712 40.789 ;
     RECT  2.4 40.789 2.856 40.931 ;
     RECT  5.568 36.611 5.592 41.797 ;
     RECT  5.568 41.797 5.688 41.843 ;
     RECT  5.616 41.843 5.688 43.717 ;
     RECT  5.088 43.717 5.688 43.763 ;
     RECT  7.8 2.151 8.112 43.813 ;
     RECT  6.864 43.813 8.112 44.435 ;
     RECT  2.4 40.931 2.712 44.437 ;
     RECT  2.304 44.437 2.712 44.915 ;
     RECT  5.088 43.763 5.4 45.589 ;
     RECT  5.088 45.589 5.736 45.635 ;
     RECT  5.712 45.635 5.736 46.741 ;
     RECT  0.144 45.781 0.168 47.123 ;
     RECT  5.712 46.741 5.784 47.939 ;
     RECT  6.768 48.901 6.792 49.043 ;
     RECT  0.144 48.997 0.168 49.187 ;
     RECT  5.712 47.939 5.736 50.003 ;
     RECT  0.192 50.101 0.216 50.339 ;
     RECT  2.4 44.915 2.712 51.637 ;
     RECT  2.304 51.637 2.712 51.827 ;
     RECT  5.76 50.101 5.784 51.877 ;
     RECT  5.76 51.877 6.024 51.923 ;
     RECT  6 51.923 6.024 53.075 ;
     RECT  0.144 54.517 0.168 54.707 ;
     RECT  7.8 44.435 8.112 56.965 ;
     RECT  2.4 51.827 2.712 57.877 ;
     RECT  2.4 57.877 2.856 58.163 ;
     RECT  7.296 56.965 8.112 58.355 ;
     RECT  0.144 58.117 0.168 58.547 ;
     RECT  5.76 56.389 5.784 59.891 ;
     RECT  78 2.151 78.312 62.677 ;
     RECT  80.208 59.797 80.232 62.725 ;
     RECT  80.208 62.725 80.376 62.771 ;
     RECT  78 62.677 78.744 63.299 ;
     RECT  78 63.299 78.312 67.141 ;
     RECT  80.352 62.771 80.376 67.285 ;
     RECT  80.208 67.285 80.376 67.331 ;
     RECT  51 2.151 51.312 67.669 ;
     RECT  43.632 52.261 43.656 67.955 ;
     RECT  50.88 67.669 51.312 68.147 ;
     RECT  78 67.141 78.456 68.435 ;
     RECT  7.344 58.355 8.112 69.587 ;
     RECT  80.208 67.331 80.232 78.373 ;
     RECT  79.968 78.373 80.232 79.715 ;
     RECT  80.208 79.715 80.232 79.859 ;
     RECT  86.208 80.437 86.232 80.627 ;
     RECT  78 68.435 78.312 81.781 ;
     RECT  78 81.781 78.456 83.267 ;
     RECT  2.4 58.163 2.712 84.249 ;
     RECT  7.8 69.587 8.112 84.249 ;
     RECT  13.2 2.151 13.512 84.249 ;
     RECT  18.6 2.151 18.912 84.249 ;
     RECT  24 2.151 24.312 84.249 ;
     RECT  29.4 2.151 29.712 84.249 ;
     RECT  34.8 2.151 35.112 84.249 ;
     RECT  40.2 2.151 40.512 84.249 ;
     RECT  45.6 2.151 45.912 84.249 ;
     RECT  51 68.147 51.312 84.249 ;
     RECT  56.4 2.151 56.712 84.249 ;
     RECT  61.8 2.151 62.112 84.249 ;
     RECT  67.2 2.151 67.512 84.249 ;
     RECT  72.6 2.151 72.912 84.249 ;
     RECT  78 83.267 78.312 84.249 ;
     RECT  83.4 2.151 83.712 84.249 ;
     RECT  2.4 84.249 2.52 84.263 ;
     RECT  7.8 84.249 7.92 84.263 ;
     RECT  13.2 84.249 13.32 84.263 ;
     RECT  18.6 84.249 18.72 84.263 ;
     RECT  24 84.249 24.12 84.263 ;
     RECT  29.4 84.249 29.52 84.263 ;
     RECT  34.8 84.249 34.92 84.263 ;
     RECT  40.2 84.249 40.32 84.263 ;
     RECT  45.6 84.249 45.72 84.263 ;
     RECT  51 84.249 51.12 84.263 ;
     RECT  56.4 84.249 56.52 84.263 ;
     RECT  61.8 84.249 61.92 84.263 ;
     RECT  67.2 84.249 67.32 84.263 ;
     RECT  72.6 84.249 72.72 84.263 ;
     RECT  78 84.249 78.12 84.263 ;
     RECT  83.4 84.249 83.52 84.263 ;
  END
END ot_hbm_su_programme_root_h
END LIBRARY
